VERSION 5.7 ;
  NOWIREEXTENSIONATPIN ON ;
  DIVIDERCHAR "/" ;
  BUSBITCHARS "[]" ;
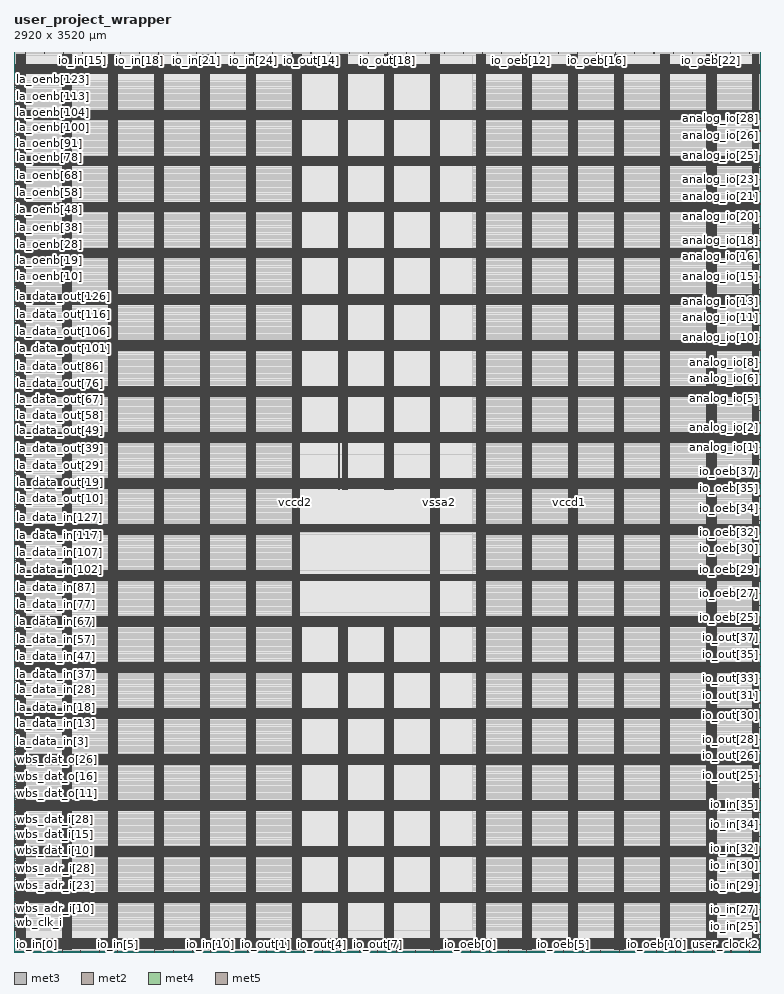
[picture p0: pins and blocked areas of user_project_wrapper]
MACRO user_project_wrapper
  CLASS BLOCK ;
  FOREIGN user_project_wrapper ;
  ORIGIN 0.000 0.000 ;
  SIZE 2920.000 BY 3520.000 ;
  PIN analog_io[0]
    DIRECTION INOUT ;
    USE SIGNAL ;
    PORT
      LAYER met3 ;
        RECT 2916.000 1925.800 2920.000 1926.400 ;
    END
  END analog_io[0]
  PIN analog_io[10]
    DIRECTION INOUT ;
    USE SIGNAL ;
    PORT
      LAYER met3 ;
        RECT 2916.000 2401.800 2920.000 2402.400 ;
    END
  END analog_io[10]
  PIN analog_io[11]
    DIRECTION INOUT ;
    USE SIGNAL ;
    PORT
      LAYER met3 ;
        RECT 2916.000 2449.400 2920.000 2450.000 ;
    END
  END analog_io[11]
  PIN analog_io[12]
    DIRECTION INOUT ;
    USE SIGNAL ;
    PORT
      LAYER met3 ;
        RECT 2916.000 2497.000 2920.000 2497.600 ;
    END
  END analog_io[12]
  PIN analog_io[13]
    DIRECTION INOUT ;
    USE SIGNAL ;
    PORT
      LAYER met3 ;
        RECT 2916.000 2544.600 2920.000 2545.200 ;
    END
  END analog_io[13]
  PIN analog_io[14]
    DIRECTION INOUT ;
    USE SIGNAL ;
    PORT
      LAYER met3 ;
        RECT 2916.000 2592.200 2920.000 2592.800 ;
    END
  END analog_io[14]
  PIN analog_io[15]
    DIRECTION INOUT ;
    USE SIGNAL ;
    PORT
      LAYER met3 ;
        RECT 2916.000 2639.800 2920.000 2640.400 ;
    END
  END analog_io[15]
  PIN analog_io[16]
    DIRECTION INOUT ;
    USE SIGNAL ;
    PORT
      LAYER met3 ;
        RECT 2916.000 2687.400 2920.000 2688.000 ;
    END
  END analog_io[16]
  PIN analog_io[17]
    DIRECTION INOUT ;
    USE SIGNAL ;
    PORT
      LAYER met3 ;
        RECT 2916.000 2735.000 2920.000 2735.600 ;
    END
  END analog_io[17]
  PIN analog_io[18]
    DIRECTION INOUT ;
    USE SIGNAL ;
    PORT
      LAYER met3 ;
        RECT 2916.000 2782.600 2920.000 2783.200 ;
    END
  END analog_io[18]
  PIN analog_io[19]
    DIRECTION INOUT ;
    USE SIGNAL ;
    PORT
      LAYER met3 ;
        RECT 2916.000 2830.200 2920.000 2830.800 ;
    END
  END analog_io[19]
  PIN analog_io[1]
    DIRECTION INOUT ;
    USE SIGNAL ;
    PORT
      LAYER met3 ;
        RECT 2916.000 1973.400 2920.000 1974.000 ;
    END
  END analog_io[1]
  PIN analog_io[20]
    DIRECTION INOUT ;
    USE SIGNAL ;
    PORT
      LAYER met3 ;
        RECT 2916.000 2877.800 2920.000 2878.400 ;
    END
  END analog_io[20]
  PIN analog_io[21]
    DIRECTION INOUT ;
    USE SIGNAL ;
    PORT
      LAYER met3 ;
        RECT 2916.000 2925.400 2920.000 2926.000 ;
    END
  END analog_io[21]
  PIN analog_io[22]
    DIRECTION INOUT ;
    USE SIGNAL ;
    PORT
      LAYER met3 ;
        RECT 2916.000 2973.000 2920.000 2973.600 ;
    END
  END analog_io[22]
  PIN analog_io[23]
    DIRECTION INOUT ;
    USE SIGNAL ;
    PORT
      LAYER met3 ;
        RECT 2916.000 3020.600 2920.000 3021.200 ;
    END
  END analog_io[23]
  PIN analog_io[24]
    DIRECTION INOUT ;
    USE SIGNAL ;
    PORT
      LAYER met3 ;
        RECT 2916.000 3068.200 2920.000 3068.800 ;
    END
  END analog_io[24]
  PIN analog_io[25]
    DIRECTION INOUT ;
    USE SIGNAL ;
    PORT
      LAYER met3 ;
        RECT 2916.000 3115.800 2920.000 3116.400 ;
    END
  END analog_io[25]
  PIN analog_io[26]
    DIRECTION INOUT ;
    USE SIGNAL ;
    PORT
      LAYER met3 ;
        RECT 2916.000 3163.400 2920.000 3164.000 ;
    END
  END analog_io[26]
  PIN analog_io[27]
    DIRECTION INOUT ;
    USE SIGNAL ;
    PORT
      LAYER met3 ;
        RECT 2916.000 3211.000 2920.000 3211.600 ;
    END
  END analog_io[27]
  PIN analog_io[28]
    DIRECTION INOUT ;
    USE SIGNAL ;
    PORT
      LAYER met3 ;
        RECT 2916.000 3258.600 2920.000 3259.200 ;
    END
  END analog_io[28]
  PIN analog_io[2]
    DIRECTION INOUT ;
    USE SIGNAL ;
    PORT
      LAYER met3 ;
        RECT 2916.000 2021.000 2920.000 2021.600 ;
    END
  END analog_io[2]
  PIN analog_io[3]
    DIRECTION INOUT ;
    USE SIGNAL ;
    PORT
      LAYER met3 ;
        RECT 2916.000 2068.600 2920.000 2069.200 ;
    END
  END analog_io[3]
  PIN analog_io[4]
    DIRECTION INOUT ;
    USE SIGNAL ;
    PORT
      LAYER met3 ;
        RECT 2916.000 2116.200 2920.000 2116.800 ;
    END
  END analog_io[4]
  PIN analog_io[5]
    DIRECTION INOUT ;
    USE SIGNAL ;
    PORT
      LAYER met3 ;
        RECT 2916.000 2163.800 2920.000 2164.400 ;
    END
  END analog_io[5]
  PIN analog_io[6]
    DIRECTION INOUT ;
    USE SIGNAL ;
    PORT
      LAYER met3 ;
        RECT 2916.000 2211.400 2920.000 2212.000 ;
    END
  END analog_io[6]
  PIN analog_io[7]
    DIRECTION INOUT ;
    USE SIGNAL ;
    PORT
      LAYER met3 ;
        RECT 2916.000 2259.000 2920.000 2259.600 ;
    END
  END analog_io[7]
  PIN analog_io[8]
    DIRECTION INOUT ;
    USE SIGNAL ;
    PORT
      LAYER met3 ;
        RECT 2916.000 2306.600 2920.000 2307.200 ;
    END
  END analog_io[8]
  PIN analog_io[9]
    DIRECTION INOUT ;
    USE SIGNAL ;
    PORT
      LAYER met3 ;
        RECT 2916.000 2354.200 2920.000 2354.800 ;
    END
  END analog_io[9]
  PIN io_in[0]
    DIRECTION INPUT ;
    USE SIGNAL ;
    PORT
      LAYER met2 ;
        RECT 42.410 0.000 42.690 4.000 ;
    END
  END io_in[0]
  PIN io_in[10]
    DIRECTION INPUT ;
    USE SIGNAL ;
    PORT
      LAYER met2 ;
        RECT 769.210 0.000 769.490 4.000 ;
    END
  END io_in[10]
  PIN io_in[11]
    DIRECTION INPUT ;
    USE SIGNAL ;
    PORT
      LAYER met2 ;
        RECT 841.890 0.000 842.170 4.000 ;
    END
  END io_in[11]
  PIN io_in[12]
    DIRECTION INPUT ;
    USE SIGNAL ;
    PORT
      LAYER met2 ;
        RECT 43.790 3516.000 44.070 3520.000 ;
    END
  END io_in[12]
  PIN io_in[13]
    DIRECTION INPUT ;
    USE SIGNAL ;
    PORT
      LAYER met2 ;
        RECT 118.310 3516.000 118.590 3520.000 ;
    END
  END io_in[13]
  PIN io_in[14]
    DIRECTION INPUT ;
    USE SIGNAL ;
    PORT
      LAYER met2 ;
        RECT 192.830 3516.000 193.110 3520.000 ;
    END
  END io_in[14]
  PIN io_in[15]
    DIRECTION INPUT ;
    USE SIGNAL ;
    PORT
      LAYER met2 ;
        RECT 267.350 3516.000 267.630 3520.000 ;
    END
  END io_in[15]
  PIN io_in[16]
    DIRECTION INPUT ;
    USE SIGNAL ;
    PORT
      LAYER met2 ;
        RECT 341.870 3516.000 342.150 3520.000 ;
    END
  END io_in[16]
  PIN io_in[17]
    DIRECTION INPUT ;
    USE SIGNAL ;
    PORT
      LAYER met2 ;
        RECT 416.390 3516.000 416.670 3520.000 ;
    END
  END io_in[17]
  PIN io_in[18]
    DIRECTION INPUT ;
    USE SIGNAL ;
    PORT
      LAYER met2 ;
        RECT 490.910 3516.000 491.190 3520.000 ;
    END
  END io_in[18]
  PIN io_in[19]
    DIRECTION INPUT ;
    USE SIGNAL ;
    PORT
      LAYER met2 ;
        RECT 565.430 3516.000 565.710 3520.000 ;
    END
  END io_in[19]
  PIN io_in[1]
    DIRECTION INPUT ;
    USE SIGNAL ;
    PORT
      LAYER met2 ;
        RECT 115.090 0.000 115.370 4.000 ;
    END
  END io_in[1]
  PIN io_in[20]
    DIRECTION INPUT ;
    USE SIGNAL ;
    PORT
      LAYER met2 ;
        RECT 639.950 3516.000 640.230 3520.000 ;
    END
  END io_in[20]
  PIN io_in[21]
    DIRECTION INPUT ;
    USE SIGNAL ;
    PORT
      LAYER met2 ;
        RECT 714.470 3516.000 714.750 3520.000 ;
    END
  END io_in[21]
  PIN io_in[22]
    DIRECTION INPUT ;
    USE SIGNAL ;
    PORT
      LAYER met2 ;
        RECT 788.990 3516.000 789.270 3520.000 ;
    END
  END io_in[22]
  PIN io_in[23]
    DIRECTION INPUT ;
    USE SIGNAL ;
    PORT
      LAYER met2 ;
        RECT 863.510 3516.000 863.790 3520.000 ;
    END
  END io_in[23]
  PIN io_in[24]
    DIRECTION INPUT ;
    USE SIGNAL ;
    PORT
      LAYER met2 ;
        RECT 938.030 3516.000 938.310 3520.000 ;
    END
  END io_in[24]
  PIN io_in[25]
    DIRECTION INPUT ;
    USE SIGNAL ;
    PORT
      LAYER met3 ;
        RECT 2916.000 69.400 2920.000 70.000 ;
    END
  END io_in[25]
  PIN io_in[26]
    DIRECTION INPUT ;
    USE SIGNAL ;
    PORT
      LAYER met3 ;
        RECT 2916.000 117.000 2920.000 117.600 ;
    END
  END io_in[26]
  PIN io_in[27]
    DIRECTION INPUT ;
    USE SIGNAL ;
    PORT
      LAYER met3 ;
        RECT 2916.000 164.600 2920.000 165.200 ;
    END
  END io_in[27]
  PIN io_in[28]
    DIRECTION INPUT ;
    USE SIGNAL ;
    PORT
      LAYER met3 ;
        RECT 2916.000 212.200 2920.000 212.800 ;
    END
  END io_in[28]
  PIN io_in[29]
    DIRECTION INPUT ;
    USE SIGNAL ;
    PORT
      LAYER met3 ;
        RECT 2916.000 259.800 2920.000 260.400 ;
    END
  END io_in[29]
  PIN io_in[2]
    DIRECTION INPUT ;
    USE SIGNAL ;
    PORT
      LAYER met2 ;
        RECT 187.770 0.000 188.050 4.000 ;
    END
  END io_in[2]
  PIN io_in[30]
    DIRECTION INPUT ;
    USE SIGNAL ;
    PORT
      LAYER met3 ;
        RECT 2916.000 307.400 2920.000 308.000 ;
    END
  END io_in[30]
  PIN io_in[31]
    DIRECTION INPUT ;
    USE SIGNAL ;
    PORT
      LAYER met3 ;
        RECT 2916.000 355.000 2920.000 355.600 ;
    END
  END io_in[31]
  PIN io_in[32]
    DIRECTION INPUT ;
    USE SIGNAL ;
    PORT
      LAYER met3 ;
        RECT 2916.000 402.600 2920.000 403.200 ;
    END
  END io_in[32]
  PIN io_in[33]
    DIRECTION INPUT ;
    USE SIGNAL ;
    PORT
      LAYER met3 ;
        RECT 2916.000 450.200 2920.000 450.800 ;
    END
  END io_in[33]
  PIN io_in[34]
    DIRECTION INPUT ;
    USE SIGNAL ;
    PORT
      LAYER met3 ;
        RECT 2916.000 497.800 2920.000 498.400 ;
    END
  END io_in[34]
  PIN io_in[35]
    DIRECTION INPUT ;
    USE SIGNAL ;
    PORT
      LAYER met3 ;
        RECT 2916.000 545.400 2920.000 546.000 ;
    END
  END io_in[35]
  PIN io_in[36]
    DIRECTION INPUT ;
    USE SIGNAL ;
    PORT
      LAYER met3 ;
        RECT 2916.000 593.000 2920.000 593.600 ;
    END
  END io_in[36]
  PIN io_in[37]
    DIRECTION INPUT ;
    USE SIGNAL ;
    PORT
      LAYER met3 ;
        RECT 2916.000 640.600 2920.000 641.200 ;
    END
  END io_in[37]
  PIN io_in[3]
    DIRECTION INPUT ;
    USE SIGNAL ;
    PORT
      LAYER met2 ;
        RECT 260.450 0.000 260.730 4.000 ;
    END
  END io_in[3]
  PIN io_in[4]
    DIRECTION INPUT ;
    USE SIGNAL ;
    PORT
      LAYER met2 ;
        RECT 333.130 0.000 333.410 4.000 ;
    END
  END io_in[4]
  PIN io_in[5]
    DIRECTION INPUT ;
    USE SIGNAL ;
    PORT
      LAYER met2 ;
        RECT 405.810 0.000 406.090 4.000 ;
    END
  END io_in[5]
  PIN io_in[6]
    DIRECTION INPUT ;
    USE SIGNAL ;
    PORT
      LAYER met2 ;
        RECT 478.490 0.000 478.770 4.000 ;
    END
  END io_in[6]
  PIN io_in[7]
    DIRECTION INPUT ;
    USE SIGNAL ;
    PORT
      LAYER met2 ;
        RECT 551.170 0.000 551.450 4.000 ;
    END
  END io_in[7]
  PIN io_in[8]
    DIRECTION INPUT ;
    USE SIGNAL ;
    PORT
      LAYER met2 ;
        RECT 623.850 0.000 624.130 4.000 ;
    END
  END io_in[8]
  PIN io_in[9]
    DIRECTION INPUT ;
    USE SIGNAL ;
    PORT
      LAYER met2 ;
        RECT 696.530 0.000 696.810 4.000 ;
    END
  END io_in[9]
  PIN io_oeb[0]
    DIRECTION OUTPUT ;
    USE SIGNAL ;
    ANTENNADIFFAREA 0.891000 ;
    PORT
      LAYER met2 ;
        RECT 1786.730 0.000 1787.010 4.000 ;
    END
  END io_oeb[0]
  PIN io_oeb[10]
    DIRECTION OUTPUT ;
    USE SIGNAL ;
    ANTENNADIFFAREA 0.891000 ;
    PORT
      LAYER met2 ;
        RECT 2513.530 0.000 2513.810 4.000 ;
    END
  END io_oeb[10]
  PIN io_oeb[11]
    DIRECTION OUTPUT ;
    USE SIGNAL ;
    ANTENNADIFFAREA 0.891000 ;
    PORT
      LAYER met2 ;
        RECT 2586.210 0.000 2586.490 4.000 ;
    END
  END io_oeb[11]
  PIN io_oeb[12]
    DIRECTION OUTPUT ;
    USE SIGNAL ;
    ANTENNADIFFAREA 0.891000 ;
    PORT
      LAYER met2 ;
        RECT 1981.310 3516.000 1981.590 3520.000 ;
    END
  END io_oeb[12]
  PIN io_oeb[13]
    DIRECTION OUTPUT ;
    USE SIGNAL ;
    ANTENNADIFFAREA 0.891000 ;
    PORT
      LAYER met2 ;
        RECT 2055.830 3516.000 2056.110 3520.000 ;
    END
  END io_oeb[13]
  PIN io_oeb[14]
    DIRECTION OUTPUT ;
    USE SIGNAL ;
    ANTENNADIFFAREA 0.891000 ;
    PORT
      LAYER met2 ;
        RECT 2130.350 3516.000 2130.630 3520.000 ;
    END
  END io_oeb[14]
  PIN io_oeb[15]
    DIRECTION OUTPUT ;
    USE SIGNAL ;
    ANTENNADIFFAREA 0.891000 ;
    PORT
      LAYER met2 ;
        RECT 2204.870 3516.000 2205.150 3520.000 ;
    END
  END io_oeb[15]
  PIN io_oeb[16]
    DIRECTION OUTPUT ;
    USE SIGNAL ;
    ANTENNADIFFAREA 0.891000 ;
    PORT
      LAYER met2 ;
        RECT 2279.390 3516.000 2279.670 3520.000 ;
    END
  END io_oeb[16]
  PIN io_oeb[17]
    DIRECTION OUTPUT ;
    USE SIGNAL ;
    ANTENNADIFFAREA 0.891000 ;
    PORT
      LAYER met2 ;
        RECT 2353.910 3516.000 2354.190 3520.000 ;
    END
  END io_oeb[17]
  PIN io_oeb[18]
    DIRECTION OUTPUT ;
    USE SIGNAL ;
    ANTENNADIFFAREA 0.891000 ;
    PORT
      LAYER met2 ;
        RECT 2428.430 3516.000 2428.710 3520.000 ;
    END
  END io_oeb[18]
  PIN io_oeb[19]
    DIRECTION OUTPUT ;
    USE SIGNAL ;
    ANTENNADIFFAREA 0.891000 ;
    PORT
      LAYER met2 ;
        RECT 2502.950 3516.000 2503.230 3520.000 ;
    END
  END io_oeb[19]
  PIN io_oeb[1]
    DIRECTION OUTPUT ;
    USE SIGNAL ;
    ANTENNADIFFAREA 0.891000 ;
    PORT
      LAYER met2 ;
        RECT 1859.410 0.000 1859.690 4.000 ;
    END
  END io_oeb[1]
  PIN io_oeb[20]
    DIRECTION OUTPUT ;
    USE SIGNAL ;
    ANTENNADIFFAREA 0.891000 ;
    PORT
      LAYER met2 ;
        RECT 2577.470 3516.000 2577.750 3520.000 ;
    END
  END io_oeb[20]
  PIN io_oeb[21]
    DIRECTION OUTPUT ;
    USE SIGNAL ;
    ANTENNADIFFAREA 0.891000 ;
    PORT
      LAYER met2 ;
        RECT 2651.990 3516.000 2652.270 3520.000 ;
    END
  END io_oeb[21]
  PIN io_oeb[22]
    DIRECTION OUTPUT ;
    USE SIGNAL ;
    ANTENNADIFFAREA 0.891000 ;
    PORT
      LAYER met2 ;
        RECT 2726.510 3516.000 2726.790 3520.000 ;
    END
  END io_oeb[22]
  PIN io_oeb[23]
    DIRECTION OUTPUT ;
    USE SIGNAL ;
    ANTENNADIFFAREA 0.891000 ;
    PORT
      LAYER met2 ;
        RECT 2801.030 3516.000 2801.310 3520.000 ;
    END
  END io_oeb[23]
  PIN io_oeb[24]
    DIRECTION OUTPUT ;
    USE SIGNAL ;
    ANTENNADIFFAREA 0.891000 ;
    PORT
      LAYER met2 ;
        RECT 2875.550 3516.000 2875.830 3520.000 ;
    END
  END io_oeb[24]
  PIN io_oeb[25]
    DIRECTION OUTPUT ;
    USE SIGNAL ;
    ANTENNADIFFAREA 0.891000 ;
    PORT
      LAYER met3 ;
        RECT 2916.000 1307.000 2920.000 1307.600 ;
    END
  END io_oeb[25]
  PIN io_oeb[26]
    DIRECTION OUTPUT ;
    USE SIGNAL ;
    ANTENNADIFFAREA 0.891000 ;
    PORT
      LAYER met3 ;
        RECT 2916.000 1354.600 2920.000 1355.200 ;
    END
  END io_oeb[26]
  PIN io_oeb[27]
    DIRECTION OUTPUT ;
    USE SIGNAL ;
    ANTENNADIFFAREA 0.891000 ;
    PORT
      LAYER met3 ;
        RECT 2916.000 1402.200 2920.000 1402.800 ;
    END
  END io_oeb[27]
  PIN io_oeb[28]
    DIRECTION OUTPUT ;
    USE SIGNAL ;
    ANTENNADIFFAREA 0.891000 ;
    PORT
      LAYER met3 ;
        RECT 2916.000 1449.800 2920.000 1450.400 ;
    END
  END io_oeb[28]
  PIN io_oeb[29]
    DIRECTION OUTPUT ;
    USE SIGNAL ;
    ANTENNADIFFAREA 0.891000 ;
    PORT
      LAYER met3 ;
        RECT 2916.000 1497.400 2920.000 1498.000 ;
    END
  END io_oeb[29]
  PIN io_oeb[2]
    DIRECTION OUTPUT ;
    USE SIGNAL ;
    ANTENNADIFFAREA 0.891000 ;
    PORT
      LAYER met2 ;
        RECT 1932.090 0.000 1932.370 4.000 ;
    END
  END io_oeb[2]
  PIN io_oeb[30]
    DIRECTION OUTPUT ;
    USE SIGNAL ;
    ANTENNADIFFAREA 0.891000 ;
    PORT
      LAYER met3 ;
        RECT 2916.000 1545.000 2920.000 1545.600 ;
    END
  END io_oeb[30]
  PIN io_oeb[31]
    DIRECTION OUTPUT ;
    USE SIGNAL ;
    ANTENNADIFFAREA 0.891000 ;
    PORT
      LAYER met3 ;
        RECT 2916.000 1592.600 2920.000 1593.200 ;
    END
  END io_oeb[31]
  PIN io_oeb[32]
    DIRECTION OUTPUT ;
    USE SIGNAL ;
    ANTENNADIFFAREA 0.891000 ;
    PORT
      LAYER met3 ;
        RECT 2916.000 1640.200 2920.000 1640.800 ;
    END
  END io_oeb[32]
  PIN io_oeb[33]
    DIRECTION OUTPUT ;
    USE SIGNAL ;
    ANTENNADIFFAREA 0.891000 ;
    PORT
      LAYER met3 ;
        RECT 2916.000 1687.800 2920.000 1688.400 ;
    END
  END io_oeb[33]
  PIN io_oeb[34]
    DIRECTION OUTPUT ;
    USE SIGNAL ;
    ANTENNADIFFAREA 0.891000 ;
    PORT
      LAYER met3 ;
        RECT 2916.000 1735.400 2920.000 1736.000 ;
    END
  END io_oeb[34]
  PIN io_oeb[35]
    DIRECTION OUTPUT ;
    USE SIGNAL ;
    ANTENNADIFFAREA 0.891000 ;
    PORT
      LAYER met3 ;
        RECT 2916.000 1783.000 2920.000 1783.600 ;
    END
  END io_oeb[35]
  PIN io_oeb[36]
    DIRECTION OUTPUT ;
    USE SIGNAL ;
    ANTENNADIFFAREA 0.891000 ;
    PORT
      LAYER met3 ;
        RECT 2916.000 1830.600 2920.000 1831.200 ;
    END
  END io_oeb[36]
  PIN io_oeb[37]
    DIRECTION OUTPUT ;
    USE SIGNAL ;
    ANTENNADIFFAREA 0.891000 ;
    PORT
      LAYER met3 ;
        RECT 2916.000 1878.200 2920.000 1878.800 ;
    END
  END io_oeb[37]
  PIN io_oeb[3]
    DIRECTION OUTPUT ;
    USE SIGNAL ;
    ANTENNADIFFAREA 0.891000 ;
    PORT
      LAYER met2 ;
        RECT 2004.770 0.000 2005.050 4.000 ;
    END
  END io_oeb[3]
  PIN io_oeb[4]
    DIRECTION OUTPUT ;
    USE SIGNAL ;
    ANTENNADIFFAREA 0.891000 ;
    PORT
      LAYER met2 ;
        RECT 2077.450 0.000 2077.730 4.000 ;
    END
  END io_oeb[4]
  PIN io_oeb[5]
    DIRECTION OUTPUT ;
    USE SIGNAL ;
    ANTENNADIFFAREA 0.891000 ;
    PORT
      LAYER met2 ;
        RECT 2150.130 0.000 2150.410 4.000 ;
    END
  END io_oeb[5]
  PIN io_oeb[6]
    DIRECTION OUTPUT ;
    USE SIGNAL ;
    ANTENNADIFFAREA 0.891000 ;
    PORT
      LAYER met2 ;
        RECT 2222.810 0.000 2223.090 4.000 ;
    END
  END io_oeb[6]
  PIN io_oeb[7]
    DIRECTION OUTPUT ;
    USE SIGNAL ;
    ANTENNADIFFAREA 0.891000 ;
    PORT
      LAYER met2 ;
        RECT 2295.490 0.000 2295.770 4.000 ;
    END
  END io_oeb[7]
  PIN io_oeb[8]
    DIRECTION OUTPUT ;
    USE SIGNAL ;
    ANTENNADIFFAREA 0.891000 ;
    PORT
      LAYER met2 ;
        RECT 2368.170 0.000 2368.450 4.000 ;
    END
  END io_oeb[8]
  PIN io_oeb[9]
    DIRECTION OUTPUT ;
    USE SIGNAL ;
    ANTENNADIFFAREA 0.891000 ;
    PORT
      LAYER met2 ;
        RECT 2440.850 0.000 2441.130 4.000 ;
    END
  END io_oeb[9]
  PIN io_out[0]
    DIRECTION OUTPUT ;
    USE SIGNAL ;
    PORT
      LAYER met2 ;
        RECT 914.570 0.000 914.850 4.000 ;
    END
  END io_out[0]
  PIN io_out[10]
    DIRECTION OUTPUT ;
    USE SIGNAL ;
    ANTENNADIFFAREA 0.891000 ;
    PORT
      LAYER met2 ;
        RECT 1641.370 0.000 1641.650 4.000 ;
    END
  END io_out[10]
  PIN io_out[11]
    DIRECTION OUTPUT ;
    USE SIGNAL ;
    PORT
      LAYER met2 ;
        RECT 1714.050 0.000 1714.330 4.000 ;
    END
  END io_out[11]
  PIN io_out[12]
    DIRECTION OUTPUT ;
    USE SIGNAL ;
    ANTENNADIFFAREA 0.891000 ;
    PORT
      LAYER met2 ;
        RECT 1012.550 3516.000 1012.830 3520.000 ;
    END
  END io_out[12]
  PIN io_out[13]
    DIRECTION OUTPUT ;
    USE SIGNAL ;
    ANTENNADIFFAREA 0.891000 ;
    PORT
      LAYER met2 ;
        RECT 1087.070 3516.000 1087.350 3520.000 ;
    END
  END io_out[13]
  PIN io_out[14]
    DIRECTION OUTPUT ;
    USE SIGNAL ;
    ANTENNADIFFAREA 0.891000 ;
    PORT
      LAYER met2 ;
        RECT 1161.590 3516.000 1161.870 3520.000 ;
    END
  END io_out[14]
  PIN io_out[15]
    DIRECTION OUTPUT ;
    USE SIGNAL ;
    ANTENNADIFFAREA 0.891000 ;
    PORT
      LAYER met2 ;
        RECT 1236.110 3516.000 1236.390 3520.000 ;
    END
  END io_out[15]
  PIN io_out[16]
    DIRECTION OUTPUT ;
    USE SIGNAL ;
    ANTENNADIFFAREA 0.891000 ;
    PORT
      LAYER met2 ;
        RECT 1310.630 3516.000 1310.910 3520.000 ;
    END
  END io_out[16]
  PIN io_out[17]
    DIRECTION OUTPUT ;
    USE SIGNAL ;
    ANTENNADIFFAREA 0.891000 ;
    PORT
      LAYER met2 ;
        RECT 1385.150 3516.000 1385.430 3520.000 ;
    END
  END io_out[17]
  PIN io_out[18]
    DIRECTION OUTPUT ;
    USE SIGNAL ;
    ANTENNADIFFAREA 0.891000 ;
    PORT
      LAYER met2 ;
        RECT 1459.670 3516.000 1459.950 3520.000 ;
    END
  END io_out[18]
  PIN io_out[19]
    DIRECTION OUTPUT ;
    USE SIGNAL ;
    ANTENNADIFFAREA 0.891000 ;
    PORT
      LAYER met2 ;
        RECT 1534.190 3516.000 1534.470 3520.000 ;
    END
  END io_out[19]
  PIN io_out[1]
    DIRECTION OUTPUT ;
    USE SIGNAL ;
    PORT
      LAYER met2 ;
        RECT 987.250 0.000 987.530 4.000 ;
    END
  END io_out[1]
  PIN io_out[20]
    DIRECTION OUTPUT ;
    USE SIGNAL ;
    ANTENNADIFFAREA 0.891000 ;
    PORT
      LAYER met2 ;
        RECT 1608.710 3516.000 1608.990 3520.000 ;
    END
  END io_out[20]
  PIN io_out[21]
    DIRECTION OUTPUT ;
    USE SIGNAL ;
    PORT
      LAYER met2 ;
        RECT 1683.230 3516.000 1683.510 3520.000 ;
    END
  END io_out[21]
  PIN io_out[22]
    DIRECTION OUTPUT ;
    USE SIGNAL ;
    ANTENNADIFFAREA 0.891000 ;
    PORT
      LAYER met2 ;
        RECT 1757.750 3516.000 1758.030 3520.000 ;
    END
  END io_out[22]
  PIN io_out[23]
    DIRECTION OUTPUT ;
    USE SIGNAL ;
    ANTENNADIFFAREA 0.891000 ;
    PORT
      LAYER met2 ;
        RECT 1832.270 3516.000 1832.550 3520.000 ;
    END
  END io_out[23]
  PIN io_out[24]
    DIRECTION OUTPUT ;
    USE SIGNAL ;
    ANTENNADIFFAREA 0.891000 ;
    PORT
      LAYER met2 ;
        RECT 1906.790 3516.000 1907.070 3520.000 ;
    END
  END io_out[24]
  PIN io_out[25]
    DIRECTION OUTPUT ;
    USE SIGNAL ;
    PORT
      LAYER met3 ;
        RECT 2916.000 688.200 2920.000 688.800 ;
    END
  END io_out[25]
  PIN io_out[26]
    DIRECTION OUTPUT ;
    USE SIGNAL ;
    PORT
      LAYER met3 ;
        RECT 2916.000 735.800 2920.000 736.400 ;
    END
  END io_out[26]
  PIN io_out[27]
    DIRECTION OUTPUT ;
    USE SIGNAL ;
    PORT
      LAYER met3 ;
        RECT 2916.000 783.400 2920.000 784.000 ;
    END
  END io_out[27]
  PIN io_out[28]
    DIRECTION OUTPUT ;
    USE SIGNAL ;
    PORT
      LAYER met3 ;
        RECT 2916.000 831.000 2920.000 831.600 ;
    END
  END io_out[28]
  PIN io_out[29]
    DIRECTION OUTPUT ;
    USE SIGNAL ;
    PORT
      LAYER met3 ;
        RECT 2916.000 878.600 2920.000 879.200 ;
    END
  END io_out[29]
  PIN io_out[2]
    DIRECTION OUTPUT ;
    USE SIGNAL ;
    PORT
      LAYER met2 ;
        RECT 1059.930 0.000 1060.210 4.000 ;
    END
  END io_out[2]
  PIN io_out[30]
    DIRECTION OUTPUT ;
    USE SIGNAL ;
    PORT
      LAYER met3 ;
        RECT 2916.000 926.200 2920.000 926.800 ;
    END
  END io_out[30]
  PIN io_out[31]
    DIRECTION OUTPUT ;
    USE SIGNAL ;
    PORT
      LAYER met3 ;
        RECT 2916.000 973.800 2920.000 974.400 ;
    END
  END io_out[31]
  PIN io_out[32]
    DIRECTION OUTPUT ;
    USE SIGNAL ;
    PORT
      LAYER met3 ;
        RECT 2916.000 1021.400 2920.000 1022.000 ;
    END
  END io_out[32]
  PIN io_out[33]
    DIRECTION OUTPUT ;
    USE SIGNAL ;
    PORT
      LAYER met3 ;
        RECT 2916.000 1069.000 2920.000 1069.600 ;
    END
  END io_out[33]
  PIN io_out[34]
    DIRECTION OUTPUT ;
    USE SIGNAL ;
    PORT
      LAYER met3 ;
        RECT 2916.000 1116.600 2920.000 1117.200 ;
    END
  END io_out[34]
  PIN io_out[35]
    DIRECTION OUTPUT ;
    USE SIGNAL ;
    PORT
      LAYER met3 ;
        RECT 2916.000 1164.200 2920.000 1164.800 ;
    END
  END io_out[35]
  PIN io_out[36]
    DIRECTION OUTPUT ;
    USE SIGNAL ;
    PORT
      LAYER met3 ;
        RECT 2916.000 1211.800 2920.000 1212.400 ;
    END
  END io_out[36]
  PIN io_out[37]
    DIRECTION OUTPUT ;
    USE SIGNAL ;
    PORT
      LAYER met3 ;
        RECT 2916.000 1259.400 2920.000 1260.000 ;
    END
  END io_out[37]
  PIN io_out[3]
    DIRECTION OUTPUT ;
    USE SIGNAL ;
    PORT
      LAYER met2 ;
        RECT 1132.610 0.000 1132.890 4.000 ;
    END
  END io_out[3]
  PIN io_out[4]
    DIRECTION OUTPUT ;
    USE SIGNAL ;
    PORT
      LAYER met2 ;
        RECT 1205.290 0.000 1205.570 4.000 ;
    END
  END io_out[4]
  PIN io_out[5]
    DIRECTION OUTPUT ;
    USE SIGNAL ;
    PORT
      LAYER met2 ;
        RECT 1277.970 0.000 1278.250 4.000 ;
    END
  END io_out[5]
  PIN io_out[6]
    DIRECTION OUTPUT ;
    USE SIGNAL ;
    PORT
      LAYER met2 ;
        RECT 1350.650 0.000 1350.930 4.000 ;
    END
  END io_out[6]
  PIN io_out[7]
    DIRECTION OUTPUT ;
    USE SIGNAL ;
    PORT
      LAYER met2 ;
        RECT 1423.330 0.000 1423.610 4.000 ;
    END
  END io_out[7]
  PIN io_out[8]
    DIRECTION OUTPUT ;
    USE SIGNAL ;
    PORT
      LAYER met2 ;
        RECT 1496.010 0.000 1496.290 4.000 ;
    END
  END io_out[8]
  PIN io_out[9]
    DIRECTION OUTPUT ;
    USE SIGNAL ;
    PORT
      LAYER met2 ;
        RECT 1568.690 0.000 1568.970 4.000 ;
    END
  END io_out[9]
  PIN la_data_in[0]
    DIRECTION INPUT ;
    USE SIGNAL ;
    PORT
      LAYER met3 ;
        RECT 0.000 803.800 4.000 804.400 ;
    END
  END la_data_in[0]
  PIN la_data_in[100]
    DIRECTION INPUT ;
    USE SIGNAL ;
    PORT
      LAYER met3 ;
        RECT 0.000 1483.800 4.000 1484.400 ;
    END
  END la_data_in[100]
  PIN la_data_in[101]
    DIRECTION INPUT ;
    USE SIGNAL ;
    PORT
      LAYER met3 ;
        RECT 0.000 1490.600 4.000 1491.200 ;
    END
  END la_data_in[101]
  PIN la_data_in[102]
    DIRECTION INPUT ;
    USE SIGNAL ;
    PORT
      LAYER met3 ;
        RECT 0.000 1497.400 4.000 1498.000 ;
    END
  END la_data_in[102]
  PIN la_data_in[103]
    DIRECTION INPUT ;
    USE SIGNAL ;
    PORT
      LAYER met3 ;
        RECT 0.000 1504.200 4.000 1504.800 ;
    END
  END la_data_in[103]
  PIN la_data_in[104]
    DIRECTION INPUT ;
    USE SIGNAL ;
    PORT
      LAYER met3 ;
        RECT 0.000 1511.000 4.000 1511.600 ;
    END
  END la_data_in[104]
  PIN la_data_in[105]
    DIRECTION INPUT ;
    USE SIGNAL ;
    PORT
      LAYER met3 ;
        RECT 0.000 1517.800 4.000 1518.400 ;
    END
  END la_data_in[105]
  PIN la_data_in[106]
    DIRECTION INPUT ;
    USE SIGNAL ;
    PORT
      LAYER met3 ;
        RECT 0.000 1524.600 4.000 1525.200 ;
    END
  END la_data_in[106]
  PIN la_data_in[107]
    DIRECTION INPUT ;
    USE SIGNAL ;
    PORT
      LAYER met3 ;
        RECT 0.000 1531.400 4.000 1532.000 ;
    END
  END la_data_in[107]
  PIN la_data_in[108]
    DIRECTION INPUT ;
    USE SIGNAL ;
    PORT
      LAYER met3 ;
        RECT 0.000 1538.200 4.000 1538.800 ;
    END
  END la_data_in[108]
  PIN la_data_in[109]
    DIRECTION INPUT ;
    USE SIGNAL ;
    PORT
      LAYER met3 ;
        RECT 0.000 1545.000 4.000 1545.600 ;
    END
  END la_data_in[109]
  PIN la_data_in[10]
    DIRECTION INPUT ;
    USE SIGNAL ;
    PORT
      LAYER met3 ;
        RECT 0.000 871.800 4.000 872.400 ;
    END
  END la_data_in[10]
  PIN la_data_in[110]
    DIRECTION INPUT ;
    USE SIGNAL ;
    PORT
      LAYER met3 ;
        RECT 0.000 1551.800 4.000 1552.400 ;
    END
  END la_data_in[110]
  PIN la_data_in[111]
    DIRECTION INPUT ;
    USE SIGNAL ;
    PORT
      LAYER met3 ;
        RECT 0.000 1558.600 4.000 1559.200 ;
    END
  END la_data_in[111]
  PIN la_data_in[112]
    DIRECTION INPUT ;
    USE SIGNAL ;
    PORT
      LAYER met3 ;
        RECT 0.000 1565.400 4.000 1566.000 ;
    END
  END la_data_in[112]
  PIN la_data_in[113]
    DIRECTION INPUT ;
    USE SIGNAL ;
    PORT
      LAYER met3 ;
        RECT 0.000 1572.200 4.000 1572.800 ;
    END
  END la_data_in[113]
  PIN la_data_in[114]
    DIRECTION INPUT ;
    USE SIGNAL ;
    PORT
      LAYER met3 ;
        RECT 0.000 1579.000 4.000 1579.600 ;
    END
  END la_data_in[114]
  PIN la_data_in[115]
    DIRECTION INPUT ;
    USE SIGNAL ;
    PORT
      LAYER met3 ;
        RECT 0.000 1585.800 4.000 1586.400 ;
    END
  END la_data_in[115]
  PIN la_data_in[116]
    DIRECTION INPUT ;
    USE SIGNAL ;
    PORT
      LAYER met3 ;
        RECT 0.000 1592.600 4.000 1593.200 ;
    END
  END la_data_in[116]
  PIN la_data_in[117]
    DIRECTION INPUT ;
    USE SIGNAL ;
    PORT
      LAYER met3 ;
        RECT 0.000 1599.400 4.000 1600.000 ;
    END
  END la_data_in[117]
  PIN la_data_in[118]
    DIRECTION INPUT ;
    USE SIGNAL ;
    PORT
      LAYER met3 ;
        RECT 0.000 1606.200 4.000 1606.800 ;
    END
  END la_data_in[118]
  PIN la_data_in[119]
    DIRECTION INPUT ;
    USE SIGNAL ;
    PORT
      LAYER met3 ;
        RECT 0.000 1613.000 4.000 1613.600 ;
    END
  END la_data_in[119]
  PIN la_data_in[11]
    DIRECTION INPUT ;
    USE SIGNAL ;
    PORT
      LAYER met3 ;
        RECT 0.000 878.600 4.000 879.200 ;
    END
  END la_data_in[11]
  PIN la_data_in[120]
    DIRECTION INPUT ;
    USE SIGNAL ;
    PORT
      LAYER met3 ;
        RECT 0.000 1619.800 4.000 1620.400 ;
    END
  END la_data_in[120]
  PIN la_data_in[121]
    DIRECTION INPUT ;
    USE SIGNAL ;
    PORT
      LAYER met3 ;
        RECT 0.000 1626.600 4.000 1627.200 ;
    END
  END la_data_in[121]
  PIN la_data_in[122]
    DIRECTION INPUT ;
    USE SIGNAL ;
    PORT
      LAYER met3 ;
        RECT 0.000 1633.400 4.000 1634.000 ;
    END
  END la_data_in[122]
  PIN la_data_in[123]
    DIRECTION INPUT ;
    USE SIGNAL ;
    PORT
      LAYER met3 ;
        RECT 0.000 1640.200 4.000 1640.800 ;
    END
  END la_data_in[123]
  PIN la_data_in[124]
    DIRECTION INPUT ;
    USE SIGNAL ;
    PORT
      LAYER met3 ;
        RECT 0.000 1647.000 4.000 1647.600 ;
    END
  END la_data_in[124]
  PIN la_data_in[125]
    DIRECTION INPUT ;
    USE SIGNAL ;
    PORT
      LAYER met3 ;
        RECT 0.000 1653.800 4.000 1654.400 ;
    END
  END la_data_in[125]
  PIN la_data_in[126]
    DIRECTION INPUT ;
    USE SIGNAL ;
    PORT
      LAYER met3 ;
        RECT 0.000 1660.600 4.000 1661.200 ;
    END
  END la_data_in[126]
  PIN la_data_in[127]
    DIRECTION INPUT ;
    USE SIGNAL ;
    PORT
      LAYER met3 ;
        RECT 0.000 1667.400 4.000 1668.000 ;
    END
  END la_data_in[127]
  PIN la_data_in[12]
    DIRECTION INPUT ;
    USE SIGNAL ;
    PORT
      LAYER met3 ;
        RECT 0.000 885.400 4.000 886.000 ;
    END
  END la_data_in[12]
  PIN la_data_in[13]
    DIRECTION INPUT ;
    USE SIGNAL ;
    PORT
      LAYER met3 ;
        RECT 0.000 892.200 4.000 892.800 ;
    END
  END la_data_in[13]
  PIN la_data_in[14]
    DIRECTION INPUT ;
    USE SIGNAL ;
    PORT
      LAYER met3 ;
        RECT 0.000 899.000 4.000 899.600 ;
    END
  END la_data_in[14]
  PIN la_data_in[15]
    DIRECTION INPUT ;
    USE SIGNAL ;
    PORT
      LAYER met3 ;
        RECT 0.000 905.800 4.000 906.400 ;
    END
  END la_data_in[15]
  PIN la_data_in[16]
    DIRECTION INPUT ;
    USE SIGNAL ;
    PORT
      LAYER met3 ;
        RECT 0.000 912.600 4.000 913.200 ;
    END
  END la_data_in[16]
  PIN la_data_in[17]
    DIRECTION INPUT ;
    USE SIGNAL ;
    PORT
      LAYER met3 ;
        RECT 0.000 919.400 4.000 920.000 ;
    END
  END la_data_in[17]
  PIN la_data_in[18]
    DIRECTION INPUT ;
    USE SIGNAL ;
    PORT
      LAYER met3 ;
        RECT 0.000 926.200 4.000 926.800 ;
    END
  END la_data_in[18]
  PIN la_data_in[19]
    DIRECTION INPUT ;
    USE SIGNAL ;
    PORT
      LAYER met3 ;
        RECT 0.000 933.000 4.000 933.600 ;
    END
  END la_data_in[19]
  PIN la_data_in[1]
    DIRECTION INPUT ;
    USE SIGNAL ;
    PORT
      LAYER met3 ;
        RECT 0.000 810.600 4.000 811.200 ;
    END
  END la_data_in[1]
  PIN la_data_in[20]
    DIRECTION INPUT ;
    USE SIGNAL ;
    PORT
      LAYER met3 ;
        RECT 0.000 939.800 4.000 940.400 ;
    END
  END la_data_in[20]
  PIN la_data_in[21]
    DIRECTION INPUT ;
    USE SIGNAL ;
    PORT
      LAYER met3 ;
        RECT 0.000 946.600 4.000 947.200 ;
    END
  END la_data_in[21]
  PIN la_data_in[22]
    DIRECTION INPUT ;
    USE SIGNAL ;
    PORT
      LAYER met3 ;
        RECT 0.000 953.400 4.000 954.000 ;
    END
  END la_data_in[22]
  PIN la_data_in[23]
    DIRECTION INPUT ;
    USE SIGNAL ;
    PORT
      LAYER met3 ;
        RECT 0.000 960.200 4.000 960.800 ;
    END
  END la_data_in[23]
  PIN la_data_in[24]
    DIRECTION INPUT ;
    USE SIGNAL ;
    PORT
      LAYER met3 ;
        RECT 0.000 967.000 4.000 967.600 ;
    END
  END la_data_in[24]
  PIN la_data_in[25]
    DIRECTION INPUT ;
    USE SIGNAL ;
    PORT
      LAYER met3 ;
        RECT 0.000 973.800 4.000 974.400 ;
    END
  END la_data_in[25]
  PIN la_data_in[26]
    DIRECTION INPUT ;
    USE SIGNAL ;
    PORT
      LAYER met3 ;
        RECT 0.000 980.600 4.000 981.200 ;
    END
  END la_data_in[26]
  PIN la_data_in[27]
    DIRECTION INPUT ;
    USE SIGNAL ;
    PORT
      LAYER met3 ;
        RECT 0.000 987.400 4.000 988.000 ;
    END
  END la_data_in[27]
  PIN la_data_in[28]
    DIRECTION INPUT ;
    USE SIGNAL ;
    PORT
      LAYER met3 ;
        RECT 0.000 994.200 4.000 994.800 ;
    END
  END la_data_in[28]
  PIN la_data_in[29]
    DIRECTION INPUT ;
    USE SIGNAL ;
    PORT
      LAYER met3 ;
        RECT 0.000 1001.000 4.000 1001.600 ;
    END
  END la_data_in[29]
  PIN la_data_in[2]
    DIRECTION INPUT ;
    USE SIGNAL ;
    PORT
      LAYER met3 ;
        RECT 0.000 817.400 4.000 818.000 ;
    END
  END la_data_in[2]
  PIN la_data_in[30]
    DIRECTION INPUT ;
    USE SIGNAL ;
    PORT
      LAYER met3 ;
        RECT 0.000 1007.800 4.000 1008.400 ;
    END
  END la_data_in[30]
  PIN la_data_in[31]
    DIRECTION INPUT ;
    USE SIGNAL ;
    PORT
      LAYER met3 ;
        RECT 0.000 1014.600 4.000 1015.200 ;
    END
  END la_data_in[31]
  PIN la_data_in[32]
    DIRECTION INPUT ;
    USE SIGNAL ;
    PORT
      LAYER met3 ;
        RECT 0.000 1021.400 4.000 1022.000 ;
    END
  END la_data_in[32]
  PIN la_data_in[33]
    DIRECTION INPUT ;
    USE SIGNAL ;
    PORT
      LAYER met3 ;
        RECT 0.000 1028.200 4.000 1028.800 ;
    END
  END la_data_in[33]
  PIN la_data_in[34]
    DIRECTION INPUT ;
    USE SIGNAL ;
    PORT
      LAYER met3 ;
        RECT 0.000 1035.000 4.000 1035.600 ;
    END
  END la_data_in[34]
  PIN la_data_in[35]
    DIRECTION INPUT ;
    USE SIGNAL ;
    PORT
      LAYER met3 ;
        RECT 0.000 1041.800 4.000 1042.400 ;
    END
  END la_data_in[35]
  PIN la_data_in[36]
    DIRECTION INPUT ;
    USE SIGNAL ;
    PORT
      LAYER met3 ;
        RECT 0.000 1048.600 4.000 1049.200 ;
    END
  END la_data_in[36]
  PIN la_data_in[37]
    DIRECTION INPUT ;
    USE SIGNAL ;
    PORT
      LAYER met3 ;
        RECT 0.000 1055.400 4.000 1056.000 ;
    END
  END la_data_in[37]
  PIN la_data_in[38]
    DIRECTION INPUT ;
    USE SIGNAL ;
    PORT
      LAYER met3 ;
        RECT 0.000 1062.200 4.000 1062.800 ;
    END
  END la_data_in[38]
  PIN la_data_in[39]
    DIRECTION INPUT ;
    USE SIGNAL ;
    PORT
      LAYER met3 ;
        RECT 0.000 1069.000 4.000 1069.600 ;
    END
  END la_data_in[39]
  PIN la_data_in[3]
    DIRECTION INPUT ;
    USE SIGNAL ;
    PORT
      LAYER met3 ;
        RECT 0.000 824.200 4.000 824.800 ;
    END
  END la_data_in[3]
  PIN la_data_in[40]
    DIRECTION INPUT ;
    USE SIGNAL ;
    PORT
      LAYER met3 ;
        RECT 0.000 1075.800 4.000 1076.400 ;
    END
  END la_data_in[40]
  PIN la_data_in[41]
    DIRECTION INPUT ;
    USE SIGNAL ;
    PORT
      LAYER met3 ;
        RECT 0.000 1082.600 4.000 1083.200 ;
    END
  END la_data_in[41]
  PIN la_data_in[42]
    DIRECTION INPUT ;
    USE SIGNAL ;
    PORT
      LAYER met3 ;
        RECT 0.000 1089.400 4.000 1090.000 ;
    END
  END la_data_in[42]
  PIN la_data_in[43]
    DIRECTION INPUT ;
    USE SIGNAL ;
    PORT
      LAYER met3 ;
        RECT 0.000 1096.200 4.000 1096.800 ;
    END
  END la_data_in[43]
  PIN la_data_in[44]
    DIRECTION INPUT ;
    USE SIGNAL ;
    PORT
      LAYER met3 ;
        RECT 0.000 1103.000 4.000 1103.600 ;
    END
  END la_data_in[44]
  PIN la_data_in[45]
    DIRECTION INPUT ;
    USE SIGNAL ;
    PORT
      LAYER met3 ;
        RECT 0.000 1109.800 4.000 1110.400 ;
    END
  END la_data_in[45]
  PIN la_data_in[46]
    DIRECTION INPUT ;
    USE SIGNAL ;
    PORT
      LAYER met3 ;
        RECT 0.000 1116.600 4.000 1117.200 ;
    END
  END la_data_in[46]
  PIN la_data_in[47]
    DIRECTION INPUT ;
    USE SIGNAL ;
    PORT
      LAYER met3 ;
        RECT 0.000 1123.400 4.000 1124.000 ;
    END
  END la_data_in[47]
  PIN la_data_in[48]
    DIRECTION INPUT ;
    USE SIGNAL ;
    PORT
      LAYER met3 ;
        RECT 0.000 1130.200 4.000 1130.800 ;
    END
  END la_data_in[48]
  PIN la_data_in[49]
    DIRECTION INPUT ;
    USE SIGNAL ;
    PORT
      LAYER met3 ;
        RECT 0.000 1137.000 4.000 1137.600 ;
    END
  END la_data_in[49]
  PIN la_data_in[4]
    DIRECTION INPUT ;
    USE SIGNAL ;
    PORT
      LAYER met3 ;
        RECT 0.000 831.000 4.000 831.600 ;
    END
  END la_data_in[4]
  PIN la_data_in[50]
    DIRECTION INPUT ;
    USE SIGNAL ;
    PORT
      LAYER met3 ;
        RECT 0.000 1143.800 4.000 1144.400 ;
    END
  END la_data_in[50]
  PIN la_data_in[51]
    DIRECTION INPUT ;
    USE SIGNAL ;
    PORT
      LAYER met3 ;
        RECT 0.000 1150.600 4.000 1151.200 ;
    END
  END la_data_in[51]
  PIN la_data_in[52]
    DIRECTION INPUT ;
    USE SIGNAL ;
    PORT
      LAYER met3 ;
        RECT 0.000 1157.400 4.000 1158.000 ;
    END
  END la_data_in[52]
  PIN la_data_in[53]
    DIRECTION INPUT ;
    USE SIGNAL ;
    PORT
      LAYER met3 ;
        RECT 0.000 1164.200 4.000 1164.800 ;
    END
  END la_data_in[53]
  PIN la_data_in[54]
    DIRECTION INPUT ;
    USE SIGNAL ;
    PORT
      LAYER met3 ;
        RECT 0.000 1171.000 4.000 1171.600 ;
    END
  END la_data_in[54]
  PIN la_data_in[55]
    DIRECTION INPUT ;
    USE SIGNAL ;
    PORT
      LAYER met3 ;
        RECT 0.000 1177.800 4.000 1178.400 ;
    END
  END la_data_in[55]
  PIN la_data_in[56]
    DIRECTION INPUT ;
    USE SIGNAL ;
    PORT
      LAYER met3 ;
        RECT 0.000 1184.600 4.000 1185.200 ;
    END
  END la_data_in[56]
  PIN la_data_in[57]
    DIRECTION INPUT ;
    USE SIGNAL ;
    PORT
      LAYER met3 ;
        RECT 0.000 1191.400 4.000 1192.000 ;
    END
  END la_data_in[57]
  PIN la_data_in[58]
    DIRECTION INPUT ;
    USE SIGNAL ;
    PORT
      LAYER met3 ;
        RECT 0.000 1198.200 4.000 1198.800 ;
    END
  END la_data_in[58]
  PIN la_data_in[59]
    DIRECTION INPUT ;
    USE SIGNAL ;
    PORT
      LAYER met3 ;
        RECT 0.000 1205.000 4.000 1205.600 ;
    END
  END la_data_in[59]
  PIN la_data_in[5]
    DIRECTION INPUT ;
    USE SIGNAL ;
    PORT
      LAYER met3 ;
        RECT 0.000 837.800 4.000 838.400 ;
    END
  END la_data_in[5]
  PIN la_data_in[60]
    DIRECTION INPUT ;
    USE SIGNAL ;
    PORT
      LAYER met3 ;
        RECT 0.000 1211.800 4.000 1212.400 ;
    END
  END la_data_in[60]
  PIN la_data_in[61]
    DIRECTION INPUT ;
    USE SIGNAL ;
    PORT
      LAYER met3 ;
        RECT 0.000 1218.600 4.000 1219.200 ;
    END
  END la_data_in[61]
  PIN la_data_in[62]
    DIRECTION INPUT ;
    USE SIGNAL ;
    PORT
      LAYER met3 ;
        RECT 0.000 1225.400 4.000 1226.000 ;
    END
  END la_data_in[62]
  PIN la_data_in[63]
    DIRECTION INPUT ;
    USE SIGNAL ;
    PORT
      LAYER met3 ;
        RECT 0.000 1232.200 4.000 1232.800 ;
    END
  END la_data_in[63]
  PIN la_data_in[64]
    DIRECTION INPUT ;
    USE SIGNAL ;
    PORT
      LAYER met3 ;
        RECT 0.000 1239.000 4.000 1239.600 ;
    END
  END la_data_in[64]
  PIN la_data_in[65]
    DIRECTION INPUT ;
    USE SIGNAL ;
    PORT
      LAYER met3 ;
        RECT 0.000 1245.800 4.000 1246.400 ;
    END
  END la_data_in[65]
  PIN la_data_in[66]
    DIRECTION INPUT ;
    USE SIGNAL ;
    PORT
      LAYER met3 ;
        RECT 0.000 1252.600 4.000 1253.200 ;
    END
  END la_data_in[66]
  PIN la_data_in[67]
    DIRECTION INPUT ;
    USE SIGNAL ;
    PORT
      LAYER met3 ;
        RECT 0.000 1259.400 4.000 1260.000 ;
    END
  END la_data_in[67]
  PIN la_data_in[68]
    DIRECTION INPUT ;
    USE SIGNAL ;
    PORT
      LAYER met3 ;
        RECT 0.000 1266.200 4.000 1266.800 ;
    END
  END la_data_in[68]
  PIN la_data_in[69]
    DIRECTION INPUT ;
    USE SIGNAL ;
    PORT
      LAYER met3 ;
        RECT 0.000 1273.000 4.000 1273.600 ;
    END
  END la_data_in[69]
  PIN la_data_in[6]
    DIRECTION INPUT ;
    USE SIGNAL ;
    PORT
      LAYER met3 ;
        RECT 0.000 844.600 4.000 845.200 ;
    END
  END la_data_in[6]
  PIN la_data_in[70]
    DIRECTION INPUT ;
    USE SIGNAL ;
    PORT
      LAYER met3 ;
        RECT 0.000 1279.800 4.000 1280.400 ;
    END
  END la_data_in[70]
  PIN la_data_in[71]
    DIRECTION INPUT ;
    USE SIGNAL ;
    PORT
      LAYER met3 ;
        RECT 0.000 1286.600 4.000 1287.200 ;
    END
  END la_data_in[71]
  PIN la_data_in[72]
    DIRECTION INPUT ;
    USE SIGNAL ;
    PORT
      LAYER met3 ;
        RECT 0.000 1293.400 4.000 1294.000 ;
    END
  END la_data_in[72]
  PIN la_data_in[73]
    DIRECTION INPUT ;
    USE SIGNAL ;
    PORT
      LAYER met3 ;
        RECT 0.000 1300.200 4.000 1300.800 ;
    END
  END la_data_in[73]
  PIN la_data_in[74]
    DIRECTION INPUT ;
    USE SIGNAL ;
    PORT
      LAYER met3 ;
        RECT 0.000 1307.000 4.000 1307.600 ;
    END
  END la_data_in[74]
  PIN la_data_in[75]
    DIRECTION INPUT ;
    USE SIGNAL ;
    PORT
      LAYER met3 ;
        RECT 0.000 1313.800 4.000 1314.400 ;
    END
  END la_data_in[75]
  PIN la_data_in[76]
    DIRECTION INPUT ;
    USE SIGNAL ;
    PORT
      LAYER met3 ;
        RECT 0.000 1320.600 4.000 1321.200 ;
    END
  END la_data_in[76]
  PIN la_data_in[77]
    DIRECTION INPUT ;
    USE SIGNAL ;
    PORT
      LAYER met3 ;
        RECT 0.000 1327.400 4.000 1328.000 ;
    END
  END la_data_in[77]
  PIN la_data_in[78]
    DIRECTION INPUT ;
    USE SIGNAL ;
    PORT
      LAYER met3 ;
        RECT 0.000 1334.200 4.000 1334.800 ;
    END
  END la_data_in[78]
  PIN la_data_in[79]
    DIRECTION INPUT ;
    USE SIGNAL ;
    PORT
      LAYER met3 ;
        RECT 0.000 1341.000 4.000 1341.600 ;
    END
  END la_data_in[79]
  PIN la_data_in[7]
    DIRECTION INPUT ;
    USE SIGNAL ;
    PORT
      LAYER met3 ;
        RECT 0.000 851.400 4.000 852.000 ;
    END
  END la_data_in[7]
  PIN la_data_in[80]
    DIRECTION INPUT ;
    USE SIGNAL ;
    PORT
      LAYER met3 ;
        RECT 0.000 1347.800 4.000 1348.400 ;
    END
  END la_data_in[80]
  PIN la_data_in[81]
    DIRECTION INPUT ;
    USE SIGNAL ;
    PORT
      LAYER met3 ;
        RECT 0.000 1354.600 4.000 1355.200 ;
    END
  END la_data_in[81]
  PIN la_data_in[82]
    DIRECTION INPUT ;
    USE SIGNAL ;
    PORT
      LAYER met3 ;
        RECT 0.000 1361.400 4.000 1362.000 ;
    END
  END la_data_in[82]
  PIN la_data_in[83]
    DIRECTION INPUT ;
    USE SIGNAL ;
    PORT
      LAYER met3 ;
        RECT 0.000 1368.200 4.000 1368.800 ;
    END
  END la_data_in[83]
  PIN la_data_in[84]
    DIRECTION INPUT ;
    USE SIGNAL ;
    PORT
      LAYER met3 ;
        RECT 0.000 1375.000 4.000 1375.600 ;
    END
  END la_data_in[84]
  PIN la_data_in[85]
    DIRECTION INPUT ;
    USE SIGNAL ;
    PORT
      LAYER met3 ;
        RECT 0.000 1381.800 4.000 1382.400 ;
    END
  END la_data_in[85]
  PIN la_data_in[86]
    DIRECTION INPUT ;
    USE SIGNAL ;
    PORT
      LAYER met3 ;
        RECT 0.000 1388.600 4.000 1389.200 ;
    END
  END la_data_in[86]
  PIN la_data_in[87]
    DIRECTION INPUT ;
    USE SIGNAL ;
    PORT
      LAYER met3 ;
        RECT 0.000 1395.400 4.000 1396.000 ;
    END
  END la_data_in[87]
  PIN la_data_in[88]
    DIRECTION INPUT ;
    USE SIGNAL ;
    PORT
      LAYER met3 ;
        RECT 0.000 1402.200 4.000 1402.800 ;
    END
  END la_data_in[88]
  PIN la_data_in[89]
    DIRECTION INPUT ;
    USE SIGNAL ;
    PORT
      LAYER met3 ;
        RECT 0.000 1409.000 4.000 1409.600 ;
    END
  END la_data_in[89]
  PIN la_data_in[8]
    DIRECTION INPUT ;
    USE SIGNAL ;
    PORT
      LAYER met3 ;
        RECT 0.000 858.200 4.000 858.800 ;
    END
  END la_data_in[8]
  PIN la_data_in[90]
    DIRECTION INPUT ;
    USE SIGNAL ;
    PORT
      LAYER met3 ;
        RECT 0.000 1415.800 4.000 1416.400 ;
    END
  END la_data_in[90]
  PIN la_data_in[91]
    DIRECTION INPUT ;
    USE SIGNAL ;
    PORT
      LAYER met3 ;
        RECT 0.000 1422.600 4.000 1423.200 ;
    END
  END la_data_in[91]
  PIN la_data_in[92]
    DIRECTION INPUT ;
    USE SIGNAL ;
    PORT
      LAYER met3 ;
        RECT 0.000 1429.400 4.000 1430.000 ;
    END
  END la_data_in[92]
  PIN la_data_in[93]
    DIRECTION INPUT ;
    USE SIGNAL ;
    PORT
      LAYER met3 ;
        RECT 0.000 1436.200 4.000 1436.800 ;
    END
  END la_data_in[93]
  PIN la_data_in[94]
    DIRECTION INPUT ;
    USE SIGNAL ;
    PORT
      LAYER met3 ;
        RECT 0.000 1443.000 4.000 1443.600 ;
    END
  END la_data_in[94]
  PIN la_data_in[95]
    DIRECTION INPUT ;
    USE SIGNAL ;
    PORT
      LAYER met3 ;
        RECT 0.000 1449.800 4.000 1450.400 ;
    END
  END la_data_in[95]
  PIN la_data_in[96]
    DIRECTION INPUT ;
    USE SIGNAL ;
    PORT
      LAYER met3 ;
        RECT 0.000 1456.600 4.000 1457.200 ;
    END
  END la_data_in[96]
  PIN la_data_in[97]
    DIRECTION INPUT ;
    USE SIGNAL ;
    PORT
      LAYER met3 ;
        RECT 0.000 1463.400 4.000 1464.000 ;
    END
  END la_data_in[97]
  PIN la_data_in[98]
    DIRECTION INPUT ;
    USE SIGNAL ;
    PORT
      LAYER met3 ;
        RECT 0.000 1470.200 4.000 1470.800 ;
    END
  END la_data_in[98]
  PIN la_data_in[99]
    DIRECTION INPUT ;
    USE SIGNAL ;
    PORT
      LAYER met3 ;
        RECT 0.000 1477.000 4.000 1477.600 ;
    END
  END la_data_in[99]
  PIN la_data_in[9]
    DIRECTION INPUT ;
    USE SIGNAL ;
    PORT
      LAYER met3 ;
        RECT 0.000 865.000 4.000 865.600 ;
    END
  END la_data_in[9]
  PIN la_data_out[0]
    DIRECTION OUTPUT ;
    USE SIGNAL ;
    PORT
      LAYER met3 ;
        RECT 0.000 1674.200 4.000 1674.800 ;
    END
  END la_data_out[0]
  PIN la_data_out[100]
    DIRECTION OUTPUT ;
    USE SIGNAL ;
    PORT
      LAYER met3 ;
        RECT 0.000 2354.200 4.000 2354.800 ;
    END
  END la_data_out[100]
  PIN la_data_out[101]
    DIRECTION OUTPUT ;
    USE SIGNAL ;
    PORT
      LAYER met3 ;
        RECT 0.000 2361.000 4.000 2361.600 ;
    END
  END la_data_out[101]
  PIN la_data_out[102]
    DIRECTION OUTPUT ;
    USE SIGNAL ;
    PORT
      LAYER met3 ;
        RECT 0.000 2367.800 4.000 2368.400 ;
    END
  END la_data_out[102]
  PIN la_data_out[103]
    DIRECTION OUTPUT ;
    USE SIGNAL ;
    PORT
      LAYER met3 ;
        RECT 0.000 2374.600 4.000 2375.200 ;
    END
  END la_data_out[103]
  PIN la_data_out[104]
    DIRECTION OUTPUT ;
    USE SIGNAL ;
    PORT
      LAYER met3 ;
        RECT 0.000 2381.400 4.000 2382.000 ;
    END
  END la_data_out[104]
  PIN la_data_out[105]
    DIRECTION OUTPUT ;
    USE SIGNAL ;
    PORT
      LAYER met3 ;
        RECT 0.000 2388.200 4.000 2388.800 ;
    END
  END la_data_out[105]
  PIN la_data_out[106]
    DIRECTION OUTPUT ;
    USE SIGNAL ;
    PORT
      LAYER met3 ;
        RECT 0.000 2395.000 4.000 2395.600 ;
    END
  END la_data_out[106]
  PIN la_data_out[107]
    DIRECTION OUTPUT ;
    USE SIGNAL ;
    PORT
      LAYER met3 ;
        RECT 0.000 2401.800 4.000 2402.400 ;
    END
  END la_data_out[107]
  PIN la_data_out[108]
    DIRECTION OUTPUT ;
    USE SIGNAL ;
    PORT
      LAYER met3 ;
        RECT 0.000 2408.600 4.000 2409.200 ;
    END
  END la_data_out[108]
  PIN la_data_out[109]
    DIRECTION OUTPUT ;
    USE SIGNAL ;
    PORT
      LAYER met3 ;
        RECT 0.000 2415.400 4.000 2416.000 ;
    END
  END la_data_out[109]
  PIN la_data_out[10]
    DIRECTION OUTPUT ;
    USE SIGNAL ;
    PORT
      LAYER met3 ;
        RECT 0.000 1742.200 4.000 1742.800 ;
    END
  END la_data_out[10]
  PIN la_data_out[110]
    DIRECTION OUTPUT ;
    USE SIGNAL ;
    PORT
      LAYER met3 ;
        RECT 0.000 2422.200 4.000 2422.800 ;
    END
  END la_data_out[110]
  PIN la_data_out[111]
    DIRECTION OUTPUT ;
    USE SIGNAL ;
    PORT
      LAYER met3 ;
        RECT 0.000 2429.000 4.000 2429.600 ;
    END
  END la_data_out[111]
  PIN la_data_out[112]
    DIRECTION OUTPUT ;
    USE SIGNAL ;
    PORT
      LAYER met3 ;
        RECT 0.000 2435.800 4.000 2436.400 ;
    END
  END la_data_out[112]
  PIN la_data_out[113]
    DIRECTION OUTPUT ;
    USE SIGNAL ;
    PORT
      LAYER met3 ;
        RECT 0.000 2442.600 4.000 2443.200 ;
    END
  END la_data_out[113]
  PIN la_data_out[114]
    DIRECTION OUTPUT ;
    USE SIGNAL ;
    PORT
      LAYER met3 ;
        RECT 0.000 2449.400 4.000 2450.000 ;
    END
  END la_data_out[114]
  PIN la_data_out[115]
    DIRECTION OUTPUT ;
    USE SIGNAL ;
    PORT
      LAYER met3 ;
        RECT 0.000 2456.200 4.000 2456.800 ;
    END
  END la_data_out[115]
  PIN la_data_out[116]
    DIRECTION OUTPUT ;
    USE SIGNAL ;
    PORT
      LAYER met3 ;
        RECT 0.000 2463.000 4.000 2463.600 ;
    END
  END la_data_out[116]
  PIN la_data_out[117]
    DIRECTION OUTPUT ;
    USE SIGNAL ;
    PORT
      LAYER met3 ;
        RECT 0.000 2469.800 4.000 2470.400 ;
    END
  END la_data_out[117]
  PIN la_data_out[118]
    DIRECTION OUTPUT ;
    USE SIGNAL ;
    PORT
      LAYER met3 ;
        RECT 0.000 2476.600 4.000 2477.200 ;
    END
  END la_data_out[118]
  PIN la_data_out[119]
    DIRECTION OUTPUT ;
    USE SIGNAL ;
    PORT
      LAYER met3 ;
        RECT 0.000 2483.400 4.000 2484.000 ;
    END
  END la_data_out[119]
  PIN la_data_out[11]
    DIRECTION OUTPUT ;
    USE SIGNAL ;
    PORT
      LAYER met3 ;
        RECT 0.000 1749.000 4.000 1749.600 ;
    END
  END la_data_out[11]
  PIN la_data_out[120]
    DIRECTION OUTPUT ;
    USE SIGNAL ;
    PORT
      LAYER met3 ;
        RECT 0.000 2490.200 4.000 2490.800 ;
    END
  END la_data_out[120]
  PIN la_data_out[121]
    DIRECTION OUTPUT ;
    USE SIGNAL ;
    PORT
      LAYER met3 ;
        RECT 0.000 2497.000 4.000 2497.600 ;
    END
  END la_data_out[121]
  PIN la_data_out[122]
    DIRECTION OUTPUT ;
    USE SIGNAL ;
    PORT
      LAYER met3 ;
        RECT 0.000 2503.800 4.000 2504.400 ;
    END
  END la_data_out[122]
  PIN la_data_out[123]
    DIRECTION OUTPUT ;
    USE SIGNAL ;
    PORT
      LAYER met3 ;
        RECT 0.000 2510.600 4.000 2511.200 ;
    END
  END la_data_out[123]
  PIN la_data_out[124]
    DIRECTION OUTPUT ;
    USE SIGNAL ;
    PORT
      LAYER met3 ;
        RECT 0.000 2517.400 4.000 2518.000 ;
    END
  END la_data_out[124]
  PIN la_data_out[125]
    DIRECTION OUTPUT ;
    USE SIGNAL ;
    PORT
      LAYER met3 ;
        RECT 0.000 2524.200 4.000 2524.800 ;
    END
  END la_data_out[125]
  PIN la_data_out[126]
    DIRECTION OUTPUT ;
    USE SIGNAL ;
    PORT
      LAYER met3 ;
        RECT 0.000 2531.000 4.000 2531.600 ;
    END
  END la_data_out[126]
  PIN la_data_out[127]
    DIRECTION OUTPUT ;
    USE SIGNAL ;
    PORT
      LAYER met3 ;
        RECT 0.000 2537.800 4.000 2538.400 ;
    END
  END la_data_out[127]
  PIN la_data_out[12]
    DIRECTION OUTPUT ;
    USE SIGNAL ;
    PORT
      LAYER met3 ;
        RECT 0.000 1755.800 4.000 1756.400 ;
    END
  END la_data_out[12]
  PIN la_data_out[13]
    DIRECTION OUTPUT ;
    USE SIGNAL ;
    PORT
      LAYER met3 ;
        RECT 0.000 1762.600 4.000 1763.200 ;
    END
  END la_data_out[13]
  PIN la_data_out[14]
    DIRECTION OUTPUT ;
    USE SIGNAL ;
    PORT
      LAYER met3 ;
        RECT 0.000 1769.400 4.000 1770.000 ;
    END
  END la_data_out[14]
  PIN la_data_out[15]
    DIRECTION OUTPUT ;
    USE SIGNAL ;
    PORT
      LAYER met3 ;
        RECT 0.000 1776.200 4.000 1776.800 ;
    END
  END la_data_out[15]
  PIN la_data_out[16]
    DIRECTION OUTPUT ;
    USE SIGNAL ;
    PORT
      LAYER met3 ;
        RECT 0.000 1783.000 4.000 1783.600 ;
    END
  END la_data_out[16]
  PIN la_data_out[17]
    DIRECTION OUTPUT ;
    USE SIGNAL ;
    PORT
      LAYER met3 ;
        RECT 0.000 1789.800 4.000 1790.400 ;
    END
  END la_data_out[17]
  PIN la_data_out[18]
    DIRECTION OUTPUT ;
    USE SIGNAL ;
    PORT
      LAYER met3 ;
        RECT 0.000 1796.600 4.000 1797.200 ;
    END
  END la_data_out[18]
  PIN la_data_out[19]
    DIRECTION OUTPUT ;
    USE SIGNAL ;
    PORT
      LAYER met3 ;
        RECT 0.000 1803.400 4.000 1804.000 ;
    END
  END la_data_out[19]
  PIN la_data_out[1]
    DIRECTION OUTPUT ;
    USE SIGNAL ;
    PORT
      LAYER met3 ;
        RECT 0.000 1681.000 4.000 1681.600 ;
    END
  END la_data_out[1]
  PIN la_data_out[20]
    DIRECTION OUTPUT ;
    USE SIGNAL ;
    PORT
      LAYER met3 ;
        RECT 0.000 1810.200 4.000 1810.800 ;
    END
  END la_data_out[20]
  PIN la_data_out[21]
    DIRECTION OUTPUT ;
    USE SIGNAL ;
    PORT
      LAYER met3 ;
        RECT 0.000 1817.000 4.000 1817.600 ;
    END
  END la_data_out[21]
  PIN la_data_out[22]
    DIRECTION OUTPUT ;
    USE SIGNAL ;
    PORT
      LAYER met3 ;
        RECT 0.000 1823.800 4.000 1824.400 ;
    END
  END la_data_out[22]
  PIN la_data_out[23]
    DIRECTION OUTPUT ;
    USE SIGNAL ;
    PORT
      LAYER met3 ;
        RECT 0.000 1830.600 4.000 1831.200 ;
    END
  END la_data_out[23]
  PIN la_data_out[24]
    DIRECTION OUTPUT ;
    USE SIGNAL ;
    PORT
      LAYER met3 ;
        RECT 0.000 1837.400 4.000 1838.000 ;
    END
  END la_data_out[24]
  PIN la_data_out[25]
    DIRECTION OUTPUT ;
    USE SIGNAL ;
    PORT
      LAYER met3 ;
        RECT 0.000 1844.200 4.000 1844.800 ;
    END
  END la_data_out[25]
  PIN la_data_out[26]
    DIRECTION OUTPUT ;
    USE SIGNAL ;
    PORT
      LAYER met3 ;
        RECT 0.000 1851.000 4.000 1851.600 ;
    END
  END la_data_out[26]
  PIN la_data_out[27]
    DIRECTION OUTPUT ;
    USE SIGNAL ;
    PORT
      LAYER met3 ;
        RECT 0.000 1857.800 4.000 1858.400 ;
    END
  END la_data_out[27]
  PIN la_data_out[28]
    DIRECTION OUTPUT ;
    USE SIGNAL ;
    PORT
      LAYER met3 ;
        RECT 0.000 1864.600 4.000 1865.200 ;
    END
  END la_data_out[28]
  PIN la_data_out[29]
    DIRECTION OUTPUT ;
    USE SIGNAL ;
    PORT
      LAYER met3 ;
        RECT 0.000 1871.400 4.000 1872.000 ;
    END
  END la_data_out[29]
  PIN la_data_out[2]
    DIRECTION OUTPUT ;
    USE SIGNAL ;
    PORT
      LAYER met3 ;
        RECT 0.000 1687.800 4.000 1688.400 ;
    END
  END la_data_out[2]
  PIN la_data_out[30]
    DIRECTION OUTPUT ;
    USE SIGNAL ;
    PORT
      LAYER met3 ;
        RECT 0.000 1878.200 4.000 1878.800 ;
    END
  END la_data_out[30]
  PIN la_data_out[31]
    DIRECTION OUTPUT ;
    USE SIGNAL ;
    PORT
      LAYER met3 ;
        RECT 0.000 1885.000 4.000 1885.600 ;
    END
  END la_data_out[31]
  PIN la_data_out[32]
    DIRECTION OUTPUT ;
    USE SIGNAL ;
    PORT
      LAYER met3 ;
        RECT 0.000 1891.800 4.000 1892.400 ;
    END
  END la_data_out[32]
  PIN la_data_out[33]
    DIRECTION OUTPUT ;
    USE SIGNAL ;
    PORT
      LAYER met3 ;
        RECT 0.000 1898.600 4.000 1899.200 ;
    END
  END la_data_out[33]
  PIN la_data_out[34]
    DIRECTION OUTPUT ;
    USE SIGNAL ;
    PORT
      LAYER met3 ;
        RECT 0.000 1905.400 4.000 1906.000 ;
    END
  END la_data_out[34]
  PIN la_data_out[35]
    DIRECTION OUTPUT ;
    USE SIGNAL ;
    PORT
      LAYER met3 ;
        RECT 0.000 1912.200 4.000 1912.800 ;
    END
  END la_data_out[35]
  PIN la_data_out[36]
    DIRECTION OUTPUT ;
    USE SIGNAL ;
    PORT
      LAYER met3 ;
        RECT 0.000 1919.000 4.000 1919.600 ;
    END
  END la_data_out[36]
  PIN la_data_out[37]
    DIRECTION OUTPUT ;
    USE SIGNAL ;
    PORT
      LAYER met3 ;
        RECT 0.000 1925.800 4.000 1926.400 ;
    END
  END la_data_out[37]
  PIN la_data_out[38]
    DIRECTION OUTPUT ;
    USE SIGNAL ;
    PORT
      LAYER met3 ;
        RECT 0.000 1932.600 4.000 1933.200 ;
    END
  END la_data_out[38]
  PIN la_data_out[39]
    DIRECTION OUTPUT ;
    USE SIGNAL ;
    PORT
      LAYER met3 ;
        RECT 0.000 1939.400 4.000 1940.000 ;
    END
  END la_data_out[39]
  PIN la_data_out[3]
    DIRECTION OUTPUT ;
    USE SIGNAL ;
    PORT
      LAYER met3 ;
        RECT 0.000 1694.600 4.000 1695.200 ;
    END
  END la_data_out[3]
  PIN la_data_out[40]
    DIRECTION OUTPUT ;
    USE SIGNAL ;
    PORT
      LAYER met3 ;
        RECT 0.000 1946.200 4.000 1946.800 ;
    END
  END la_data_out[40]
  PIN la_data_out[41]
    DIRECTION OUTPUT ;
    USE SIGNAL ;
    PORT
      LAYER met3 ;
        RECT 0.000 1953.000 4.000 1953.600 ;
    END
  END la_data_out[41]
  PIN la_data_out[42]
    DIRECTION OUTPUT ;
    USE SIGNAL ;
    PORT
      LAYER met3 ;
        RECT 0.000 1959.800 4.000 1960.400 ;
    END
  END la_data_out[42]
  PIN la_data_out[43]
    DIRECTION OUTPUT ;
    USE SIGNAL ;
    PORT
      LAYER met3 ;
        RECT 0.000 1966.600 4.000 1967.200 ;
    END
  END la_data_out[43]
  PIN la_data_out[44]
    DIRECTION OUTPUT ;
    USE SIGNAL ;
    PORT
      LAYER met3 ;
        RECT 0.000 1973.400 4.000 1974.000 ;
    END
  END la_data_out[44]
  PIN la_data_out[45]
    DIRECTION OUTPUT ;
    USE SIGNAL ;
    PORT
      LAYER met3 ;
        RECT 0.000 1980.200 4.000 1980.800 ;
    END
  END la_data_out[45]
  PIN la_data_out[46]
    DIRECTION OUTPUT ;
    USE SIGNAL ;
    PORT
      LAYER met3 ;
        RECT 0.000 1987.000 4.000 1987.600 ;
    END
  END la_data_out[46]
  PIN la_data_out[47]
    DIRECTION OUTPUT ;
    USE SIGNAL ;
    PORT
      LAYER met3 ;
        RECT 0.000 1993.800 4.000 1994.400 ;
    END
  END la_data_out[47]
  PIN la_data_out[48]
    DIRECTION OUTPUT ;
    USE SIGNAL ;
    PORT
      LAYER met3 ;
        RECT 0.000 2000.600 4.000 2001.200 ;
    END
  END la_data_out[48]
  PIN la_data_out[49]
    DIRECTION OUTPUT ;
    USE SIGNAL ;
    PORT
      LAYER met3 ;
        RECT 0.000 2007.400 4.000 2008.000 ;
    END
  END la_data_out[49]
  PIN la_data_out[4]
    DIRECTION OUTPUT ;
    USE SIGNAL ;
    PORT
      LAYER met3 ;
        RECT 0.000 1701.400 4.000 1702.000 ;
    END
  END la_data_out[4]
  PIN la_data_out[50]
    DIRECTION OUTPUT ;
    USE SIGNAL ;
    PORT
      LAYER met3 ;
        RECT 0.000 2014.200 4.000 2014.800 ;
    END
  END la_data_out[50]
  PIN la_data_out[51]
    DIRECTION OUTPUT ;
    USE SIGNAL ;
    PORT
      LAYER met3 ;
        RECT 0.000 2021.000 4.000 2021.600 ;
    END
  END la_data_out[51]
  PIN la_data_out[52]
    DIRECTION OUTPUT ;
    USE SIGNAL ;
    PORT
      LAYER met3 ;
        RECT 0.000 2027.800 4.000 2028.400 ;
    END
  END la_data_out[52]
  PIN la_data_out[53]
    DIRECTION OUTPUT ;
    USE SIGNAL ;
    PORT
      LAYER met3 ;
        RECT 0.000 2034.600 4.000 2035.200 ;
    END
  END la_data_out[53]
  PIN la_data_out[54]
    DIRECTION OUTPUT ;
    USE SIGNAL ;
    PORT
      LAYER met3 ;
        RECT 0.000 2041.400 4.000 2042.000 ;
    END
  END la_data_out[54]
  PIN la_data_out[55]
    DIRECTION OUTPUT ;
    USE SIGNAL ;
    PORT
      LAYER met3 ;
        RECT 0.000 2048.200 4.000 2048.800 ;
    END
  END la_data_out[55]
  PIN la_data_out[56]
    DIRECTION OUTPUT ;
    USE SIGNAL ;
    PORT
      LAYER met3 ;
        RECT 0.000 2055.000 4.000 2055.600 ;
    END
  END la_data_out[56]
  PIN la_data_out[57]
    DIRECTION OUTPUT ;
    USE SIGNAL ;
    PORT
      LAYER met3 ;
        RECT 0.000 2061.800 4.000 2062.400 ;
    END
  END la_data_out[57]
  PIN la_data_out[58]
    DIRECTION OUTPUT ;
    USE SIGNAL ;
    PORT
      LAYER met3 ;
        RECT 0.000 2068.600 4.000 2069.200 ;
    END
  END la_data_out[58]
  PIN la_data_out[59]
    DIRECTION OUTPUT ;
    USE SIGNAL ;
    PORT
      LAYER met3 ;
        RECT 0.000 2075.400 4.000 2076.000 ;
    END
  END la_data_out[59]
  PIN la_data_out[5]
    DIRECTION OUTPUT ;
    USE SIGNAL ;
    PORT
      LAYER met3 ;
        RECT 0.000 1708.200 4.000 1708.800 ;
    END
  END la_data_out[5]
  PIN la_data_out[60]
    DIRECTION OUTPUT ;
    USE SIGNAL ;
    PORT
      LAYER met3 ;
        RECT 0.000 2082.200 4.000 2082.800 ;
    END
  END la_data_out[60]
  PIN la_data_out[61]
    DIRECTION OUTPUT ;
    USE SIGNAL ;
    PORT
      LAYER met3 ;
        RECT 0.000 2089.000 4.000 2089.600 ;
    END
  END la_data_out[61]
  PIN la_data_out[62]
    DIRECTION OUTPUT ;
    USE SIGNAL ;
    PORT
      LAYER met3 ;
        RECT 0.000 2095.800 4.000 2096.400 ;
    END
  END la_data_out[62]
  PIN la_data_out[63]
    DIRECTION OUTPUT ;
    USE SIGNAL ;
    PORT
      LAYER met3 ;
        RECT 0.000 2102.600 4.000 2103.200 ;
    END
  END la_data_out[63]
  PIN la_data_out[64]
    DIRECTION OUTPUT ;
    USE SIGNAL ;
    PORT
      LAYER met3 ;
        RECT 0.000 2109.400 4.000 2110.000 ;
    END
  END la_data_out[64]
  PIN la_data_out[65]
    DIRECTION OUTPUT ;
    USE SIGNAL ;
    PORT
      LAYER met3 ;
        RECT 0.000 2116.200 4.000 2116.800 ;
    END
  END la_data_out[65]
  PIN la_data_out[66]
    DIRECTION OUTPUT ;
    USE SIGNAL ;
    PORT
      LAYER met3 ;
        RECT 0.000 2123.000 4.000 2123.600 ;
    END
  END la_data_out[66]
  PIN la_data_out[67]
    DIRECTION OUTPUT ;
    USE SIGNAL ;
    PORT
      LAYER met3 ;
        RECT 0.000 2129.800 4.000 2130.400 ;
    END
  END la_data_out[67]
  PIN la_data_out[68]
    DIRECTION OUTPUT ;
    USE SIGNAL ;
    PORT
      LAYER met3 ;
        RECT 0.000 2136.600 4.000 2137.200 ;
    END
  END la_data_out[68]
  PIN la_data_out[69]
    DIRECTION OUTPUT ;
    USE SIGNAL ;
    PORT
      LAYER met3 ;
        RECT 0.000 2143.400 4.000 2144.000 ;
    END
  END la_data_out[69]
  PIN la_data_out[6]
    DIRECTION OUTPUT ;
    USE SIGNAL ;
    PORT
      LAYER met3 ;
        RECT 0.000 1715.000 4.000 1715.600 ;
    END
  END la_data_out[6]
  PIN la_data_out[70]
    DIRECTION OUTPUT ;
    USE SIGNAL ;
    PORT
      LAYER met3 ;
        RECT 0.000 2150.200 4.000 2150.800 ;
    END
  END la_data_out[70]
  PIN la_data_out[71]
    DIRECTION OUTPUT ;
    USE SIGNAL ;
    PORT
      LAYER met3 ;
        RECT 0.000 2157.000 4.000 2157.600 ;
    END
  END la_data_out[71]
  PIN la_data_out[72]
    DIRECTION OUTPUT ;
    USE SIGNAL ;
    PORT
      LAYER met3 ;
        RECT 0.000 2163.800 4.000 2164.400 ;
    END
  END la_data_out[72]
  PIN la_data_out[73]
    DIRECTION OUTPUT ;
    USE SIGNAL ;
    PORT
      LAYER met3 ;
        RECT 0.000 2170.600 4.000 2171.200 ;
    END
  END la_data_out[73]
  PIN la_data_out[74]
    DIRECTION OUTPUT ;
    USE SIGNAL ;
    PORT
      LAYER met3 ;
        RECT 0.000 2177.400 4.000 2178.000 ;
    END
  END la_data_out[74]
  PIN la_data_out[75]
    DIRECTION OUTPUT ;
    USE SIGNAL ;
    PORT
      LAYER met3 ;
        RECT 0.000 2184.200 4.000 2184.800 ;
    END
  END la_data_out[75]
  PIN la_data_out[76]
    DIRECTION OUTPUT ;
    USE SIGNAL ;
    PORT
      LAYER met3 ;
        RECT 0.000 2191.000 4.000 2191.600 ;
    END
  END la_data_out[76]
  PIN la_data_out[77]
    DIRECTION OUTPUT ;
    USE SIGNAL ;
    PORT
      LAYER met3 ;
        RECT 0.000 2197.800 4.000 2198.400 ;
    END
  END la_data_out[77]
  PIN la_data_out[78]
    DIRECTION OUTPUT ;
    USE SIGNAL ;
    PORT
      LAYER met3 ;
        RECT 0.000 2204.600 4.000 2205.200 ;
    END
  END la_data_out[78]
  PIN la_data_out[79]
    DIRECTION OUTPUT ;
    USE SIGNAL ;
    PORT
      LAYER met3 ;
        RECT 0.000 2211.400 4.000 2212.000 ;
    END
  END la_data_out[79]
  PIN la_data_out[7]
    DIRECTION OUTPUT ;
    USE SIGNAL ;
    PORT
      LAYER met3 ;
        RECT 0.000 1721.800 4.000 1722.400 ;
    END
  END la_data_out[7]
  PIN la_data_out[80]
    DIRECTION OUTPUT ;
    USE SIGNAL ;
    PORT
      LAYER met3 ;
        RECT 0.000 2218.200 4.000 2218.800 ;
    END
  END la_data_out[80]
  PIN la_data_out[81]
    DIRECTION OUTPUT ;
    USE SIGNAL ;
    PORT
      LAYER met3 ;
        RECT 0.000 2225.000 4.000 2225.600 ;
    END
  END la_data_out[81]
  PIN la_data_out[82]
    DIRECTION OUTPUT ;
    USE SIGNAL ;
    PORT
      LAYER met3 ;
        RECT 0.000 2231.800 4.000 2232.400 ;
    END
  END la_data_out[82]
  PIN la_data_out[83]
    DIRECTION OUTPUT ;
    USE SIGNAL ;
    PORT
      LAYER met3 ;
        RECT 0.000 2238.600 4.000 2239.200 ;
    END
  END la_data_out[83]
  PIN la_data_out[84]
    DIRECTION OUTPUT ;
    USE SIGNAL ;
    PORT
      LAYER met3 ;
        RECT 0.000 2245.400 4.000 2246.000 ;
    END
  END la_data_out[84]
  PIN la_data_out[85]
    DIRECTION OUTPUT ;
    USE SIGNAL ;
    PORT
      LAYER met3 ;
        RECT 0.000 2252.200 4.000 2252.800 ;
    END
  END la_data_out[85]
  PIN la_data_out[86]
    DIRECTION OUTPUT ;
    USE SIGNAL ;
    PORT
      LAYER met3 ;
        RECT 0.000 2259.000 4.000 2259.600 ;
    END
  END la_data_out[86]
  PIN la_data_out[87]
    DIRECTION OUTPUT ;
    USE SIGNAL ;
    PORT
      LAYER met3 ;
        RECT 0.000 2265.800 4.000 2266.400 ;
    END
  END la_data_out[87]
  PIN la_data_out[88]
    DIRECTION OUTPUT ;
    USE SIGNAL ;
    PORT
      LAYER met3 ;
        RECT 0.000 2272.600 4.000 2273.200 ;
    END
  END la_data_out[88]
  PIN la_data_out[89]
    DIRECTION OUTPUT ;
    USE SIGNAL ;
    PORT
      LAYER met3 ;
        RECT 0.000 2279.400 4.000 2280.000 ;
    END
  END la_data_out[89]
  PIN la_data_out[8]
    DIRECTION OUTPUT ;
    USE SIGNAL ;
    PORT
      LAYER met3 ;
        RECT 0.000 1728.600 4.000 1729.200 ;
    END
  END la_data_out[8]
  PIN la_data_out[90]
    DIRECTION OUTPUT ;
    USE SIGNAL ;
    PORT
      LAYER met3 ;
        RECT 0.000 2286.200 4.000 2286.800 ;
    END
  END la_data_out[90]
  PIN la_data_out[91]
    DIRECTION OUTPUT ;
    USE SIGNAL ;
    PORT
      LAYER met3 ;
        RECT 0.000 2293.000 4.000 2293.600 ;
    END
  END la_data_out[91]
  PIN la_data_out[92]
    DIRECTION OUTPUT ;
    USE SIGNAL ;
    PORT
      LAYER met3 ;
        RECT 0.000 2299.800 4.000 2300.400 ;
    END
  END la_data_out[92]
  PIN la_data_out[93]
    DIRECTION OUTPUT ;
    USE SIGNAL ;
    PORT
      LAYER met3 ;
        RECT 0.000 2306.600 4.000 2307.200 ;
    END
  END la_data_out[93]
  PIN la_data_out[94]
    DIRECTION OUTPUT ;
    USE SIGNAL ;
    PORT
      LAYER met3 ;
        RECT 0.000 2313.400 4.000 2314.000 ;
    END
  END la_data_out[94]
  PIN la_data_out[95]
    DIRECTION OUTPUT ;
    USE SIGNAL ;
    PORT
      LAYER met3 ;
        RECT 0.000 2320.200 4.000 2320.800 ;
    END
  END la_data_out[95]
  PIN la_data_out[96]
    DIRECTION OUTPUT ;
    USE SIGNAL ;
    PORT
      LAYER met3 ;
        RECT 0.000 2327.000 4.000 2327.600 ;
    END
  END la_data_out[96]
  PIN la_data_out[97]
    DIRECTION OUTPUT ;
    USE SIGNAL ;
    PORT
      LAYER met3 ;
        RECT 0.000 2333.800 4.000 2334.400 ;
    END
  END la_data_out[97]
  PIN la_data_out[98]
    DIRECTION OUTPUT ;
    USE SIGNAL ;
    PORT
      LAYER met3 ;
        RECT 0.000 2340.600 4.000 2341.200 ;
    END
  END la_data_out[98]
  PIN la_data_out[99]
    DIRECTION OUTPUT ;
    USE SIGNAL ;
    PORT
      LAYER met3 ;
        RECT 0.000 2347.400 4.000 2348.000 ;
    END
  END la_data_out[99]
  PIN la_data_out[9]
    DIRECTION OUTPUT ;
    USE SIGNAL ;
    PORT
      LAYER met3 ;
        RECT 0.000 1735.400 4.000 1736.000 ;
    END
  END la_data_out[9]
  PIN la_oenb[0]
    DIRECTION INPUT ;
    USE SIGNAL ;
    PORT
      LAYER met3 ;
        RECT 0.000 2544.600 4.000 2545.200 ;
    END
  END la_oenb[0]
  PIN la_oenb[100]
    DIRECTION INPUT ;
    USE SIGNAL ;
    PORT
      LAYER met3 ;
        RECT 0.000 3224.600 4.000 3225.200 ;
    END
  END la_oenb[100]
  PIN la_oenb[101]
    DIRECTION INPUT ;
    USE SIGNAL ;
    PORT
      LAYER met3 ;
        RECT 0.000 3231.400 4.000 3232.000 ;
    END
  END la_oenb[101]
  PIN la_oenb[102]
    DIRECTION INPUT ;
    USE SIGNAL ;
    PORT
      LAYER met3 ;
        RECT 0.000 3238.200 4.000 3238.800 ;
    END
  END la_oenb[102]
  PIN la_oenb[103]
    DIRECTION INPUT ;
    USE SIGNAL ;
    PORT
      LAYER met3 ;
        RECT 0.000 3245.000 4.000 3245.600 ;
    END
  END la_oenb[103]
  PIN la_oenb[104]
    DIRECTION INPUT ;
    USE SIGNAL ;
    PORT
      LAYER met3 ;
        RECT 0.000 3251.800 4.000 3252.400 ;
    END
  END la_oenb[104]
  PIN la_oenb[105]
    DIRECTION INPUT ;
    USE SIGNAL ;
    PORT
      LAYER met3 ;
        RECT 0.000 3258.600 4.000 3259.200 ;
    END
  END la_oenb[105]
  PIN la_oenb[106]
    DIRECTION INPUT ;
    USE SIGNAL ;
    PORT
      LAYER met3 ;
        RECT 0.000 3265.400 4.000 3266.000 ;
    END
  END la_oenb[106]
  PIN la_oenb[107]
    DIRECTION INPUT ;
    USE SIGNAL ;
    PORT
      LAYER met3 ;
        RECT 0.000 3272.200 4.000 3272.800 ;
    END
  END la_oenb[107]
  PIN la_oenb[108]
    DIRECTION INPUT ;
    USE SIGNAL ;
    PORT
      LAYER met3 ;
        RECT 0.000 3279.000 4.000 3279.600 ;
    END
  END la_oenb[108]
  PIN la_oenb[109]
    DIRECTION INPUT ;
    USE SIGNAL ;
    PORT
      LAYER met3 ;
        RECT 0.000 3285.800 4.000 3286.400 ;
    END
  END la_oenb[109]
  PIN la_oenb[10]
    DIRECTION INPUT ;
    USE SIGNAL ;
    PORT
      LAYER met3 ;
        RECT 0.000 2612.600 4.000 2613.200 ;
    END
  END la_oenb[10]
  PIN la_oenb[110]
    DIRECTION INPUT ;
    USE SIGNAL ;
    PORT
      LAYER met3 ;
        RECT 0.000 3292.600 4.000 3293.200 ;
    END
  END la_oenb[110]
  PIN la_oenb[111]
    DIRECTION INPUT ;
    USE SIGNAL ;
    PORT
      LAYER met3 ;
        RECT 0.000 3299.400 4.000 3300.000 ;
    END
  END la_oenb[111]
  PIN la_oenb[112]
    DIRECTION INPUT ;
    USE SIGNAL ;
    PORT
      LAYER met3 ;
        RECT 0.000 3306.200 4.000 3306.800 ;
    END
  END la_oenb[112]
  PIN la_oenb[113]
    DIRECTION INPUT ;
    USE SIGNAL ;
    PORT
      LAYER met3 ;
        RECT 0.000 3313.000 4.000 3313.600 ;
    END
  END la_oenb[113]
  PIN la_oenb[114]
    DIRECTION INPUT ;
    USE SIGNAL ;
    PORT
      LAYER met3 ;
        RECT 0.000 3319.800 4.000 3320.400 ;
    END
  END la_oenb[114]
  PIN la_oenb[115]
    DIRECTION INPUT ;
    USE SIGNAL ;
    PORT
      LAYER met3 ;
        RECT 0.000 3326.600 4.000 3327.200 ;
    END
  END la_oenb[115]
  PIN la_oenb[116]
    DIRECTION INPUT ;
    USE SIGNAL ;
    PORT
      LAYER met3 ;
        RECT 0.000 3333.400 4.000 3334.000 ;
    END
  END la_oenb[116]
  PIN la_oenb[117]
    DIRECTION INPUT ;
    USE SIGNAL ;
    PORT
      LAYER met3 ;
        RECT 0.000 3340.200 4.000 3340.800 ;
    END
  END la_oenb[117]
  PIN la_oenb[118]
    DIRECTION INPUT ;
    USE SIGNAL ;
    PORT
      LAYER met3 ;
        RECT 0.000 3347.000 4.000 3347.600 ;
    END
  END la_oenb[118]
  PIN la_oenb[119]
    DIRECTION INPUT ;
    USE SIGNAL ;
    PORT
      LAYER met3 ;
        RECT 0.000 3353.800 4.000 3354.400 ;
    END
  END la_oenb[119]
  PIN la_oenb[11]
    DIRECTION INPUT ;
    USE SIGNAL ;
    PORT
      LAYER met3 ;
        RECT 0.000 2619.400 4.000 2620.000 ;
    END
  END la_oenb[11]
  PIN la_oenb[120]
    DIRECTION INPUT ;
    USE SIGNAL ;
    PORT
      LAYER met3 ;
        RECT 0.000 3360.600 4.000 3361.200 ;
    END
  END la_oenb[120]
  PIN la_oenb[121]
    DIRECTION INPUT ;
    USE SIGNAL ;
    PORT
      LAYER met3 ;
        RECT 0.000 3367.400 4.000 3368.000 ;
    END
  END la_oenb[121]
  PIN la_oenb[122]
    DIRECTION INPUT ;
    USE SIGNAL ;
    PORT
      LAYER met3 ;
        RECT 0.000 3374.200 4.000 3374.800 ;
    END
  END la_oenb[122]
  PIN la_oenb[123]
    DIRECTION INPUT ;
    USE SIGNAL ;
    PORT
      LAYER met3 ;
        RECT 0.000 3381.000 4.000 3381.600 ;
    END
  END la_oenb[123]
  PIN la_oenb[124]
    DIRECTION INPUT ;
    USE SIGNAL ;
    PORT
      LAYER met3 ;
        RECT 0.000 3387.800 4.000 3388.400 ;
    END
  END la_oenb[124]
  PIN la_oenb[125]
    DIRECTION INPUT ;
    USE SIGNAL ;
    PORT
      LAYER met3 ;
        RECT 0.000 3394.600 4.000 3395.200 ;
    END
  END la_oenb[125]
  PIN la_oenb[126]
    DIRECTION INPUT ;
    USE SIGNAL ;
    PORT
      LAYER met3 ;
        RECT 0.000 3401.400 4.000 3402.000 ;
    END
  END la_oenb[126]
  PIN la_oenb[127]
    DIRECTION INPUT ;
    USE SIGNAL ;
    PORT
      LAYER met3 ;
        RECT 0.000 3408.200 4.000 3408.800 ;
    END
  END la_oenb[127]
  PIN la_oenb[12]
    DIRECTION INPUT ;
    USE SIGNAL ;
    PORT
      LAYER met3 ;
        RECT 0.000 2626.200 4.000 2626.800 ;
    END
  END la_oenb[12]
  PIN la_oenb[13]
    DIRECTION INPUT ;
    USE SIGNAL ;
    PORT
      LAYER met3 ;
        RECT 0.000 2633.000 4.000 2633.600 ;
    END
  END la_oenb[13]
  PIN la_oenb[14]
    DIRECTION INPUT ;
    USE SIGNAL ;
    PORT
      LAYER met3 ;
        RECT 0.000 2639.800 4.000 2640.400 ;
    END
  END la_oenb[14]
  PIN la_oenb[15]
    DIRECTION INPUT ;
    USE SIGNAL ;
    PORT
      LAYER met3 ;
        RECT 0.000 2646.600 4.000 2647.200 ;
    END
  END la_oenb[15]
  PIN la_oenb[16]
    DIRECTION INPUT ;
    USE SIGNAL ;
    PORT
      LAYER met3 ;
        RECT 0.000 2653.400 4.000 2654.000 ;
    END
  END la_oenb[16]
  PIN la_oenb[17]
    DIRECTION INPUT ;
    USE SIGNAL ;
    PORT
      LAYER met3 ;
        RECT 0.000 2660.200 4.000 2660.800 ;
    END
  END la_oenb[17]
  PIN la_oenb[18]
    DIRECTION INPUT ;
    USE SIGNAL ;
    PORT
      LAYER met3 ;
        RECT 0.000 2667.000 4.000 2667.600 ;
    END
  END la_oenb[18]
  PIN la_oenb[19]
    DIRECTION INPUT ;
    USE SIGNAL ;
    PORT
      LAYER met3 ;
        RECT 0.000 2673.800 4.000 2674.400 ;
    END
  END la_oenb[19]
  PIN la_oenb[1]
    DIRECTION INPUT ;
    USE SIGNAL ;
    PORT
      LAYER met3 ;
        RECT 0.000 2551.400 4.000 2552.000 ;
    END
  END la_oenb[1]
  PIN la_oenb[20]
    DIRECTION INPUT ;
    USE SIGNAL ;
    PORT
      LAYER met3 ;
        RECT 0.000 2680.600 4.000 2681.200 ;
    END
  END la_oenb[20]
  PIN la_oenb[21]
    DIRECTION INPUT ;
    USE SIGNAL ;
    PORT
      LAYER met3 ;
        RECT 0.000 2687.400 4.000 2688.000 ;
    END
  END la_oenb[21]
  PIN la_oenb[22]
    DIRECTION INPUT ;
    USE SIGNAL ;
    PORT
      LAYER met3 ;
        RECT 0.000 2694.200 4.000 2694.800 ;
    END
  END la_oenb[22]
  PIN la_oenb[23]
    DIRECTION INPUT ;
    USE SIGNAL ;
    PORT
      LAYER met3 ;
        RECT 0.000 2701.000 4.000 2701.600 ;
    END
  END la_oenb[23]
  PIN la_oenb[24]
    DIRECTION INPUT ;
    USE SIGNAL ;
    PORT
      LAYER met3 ;
        RECT 0.000 2707.800 4.000 2708.400 ;
    END
  END la_oenb[24]
  PIN la_oenb[25]
    DIRECTION INPUT ;
    USE SIGNAL ;
    PORT
      LAYER met3 ;
        RECT 0.000 2714.600 4.000 2715.200 ;
    END
  END la_oenb[25]
  PIN la_oenb[26]
    DIRECTION INPUT ;
    USE SIGNAL ;
    PORT
      LAYER met3 ;
        RECT 0.000 2721.400 4.000 2722.000 ;
    END
  END la_oenb[26]
  PIN la_oenb[27]
    DIRECTION INPUT ;
    USE SIGNAL ;
    PORT
      LAYER met3 ;
        RECT 0.000 2728.200 4.000 2728.800 ;
    END
  END la_oenb[27]
  PIN la_oenb[28]
    DIRECTION INPUT ;
    USE SIGNAL ;
    PORT
      LAYER met3 ;
        RECT 0.000 2735.000 4.000 2735.600 ;
    END
  END la_oenb[28]
  PIN la_oenb[29]
    DIRECTION INPUT ;
    USE SIGNAL ;
    PORT
      LAYER met3 ;
        RECT 0.000 2741.800 4.000 2742.400 ;
    END
  END la_oenb[29]
  PIN la_oenb[2]
    DIRECTION INPUT ;
    USE SIGNAL ;
    PORT
      LAYER met3 ;
        RECT 0.000 2558.200 4.000 2558.800 ;
    END
  END la_oenb[2]
  PIN la_oenb[30]
    DIRECTION INPUT ;
    USE SIGNAL ;
    PORT
      LAYER met3 ;
        RECT 0.000 2748.600 4.000 2749.200 ;
    END
  END la_oenb[30]
  PIN la_oenb[31]
    DIRECTION INPUT ;
    USE SIGNAL ;
    PORT
      LAYER met3 ;
        RECT 0.000 2755.400 4.000 2756.000 ;
    END
  END la_oenb[31]
  PIN la_oenb[32]
    DIRECTION INPUT ;
    USE SIGNAL ;
    PORT
      LAYER met3 ;
        RECT 0.000 2762.200 4.000 2762.800 ;
    END
  END la_oenb[32]
  PIN la_oenb[33]
    DIRECTION INPUT ;
    USE SIGNAL ;
    PORT
      LAYER met3 ;
        RECT 0.000 2769.000 4.000 2769.600 ;
    END
  END la_oenb[33]
  PIN la_oenb[34]
    DIRECTION INPUT ;
    USE SIGNAL ;
    PORT
      LAYER met3 ;
        RECT 0.000 2775.800 4.000 2776.400 ;
    END
  END la_oenb[34]
  PIN la_oenb[35]
    DIRECTION INPUT ;
    USE SIGNAL ;
    PORT
      LAYER met3 ;
        RECT 0.000 2782.600 4.000 2783.200 ;
    END
  END la_oenb[35]
  PIN la_oenb[36]
    DIRECTION INPUT ;
    USE SIGNAL ;
    PORT
      LAYER met3 ;
        RECT 0.000 2789.400 4.000 2790.000 ;
    END
  END la_oenb[36]
  PIN la_oenb[37]
    DIRECTION INPUT ;
    USE SIGNAL ;
    PORT
      LAYER met3 ;
        RECT 0.000 2796.200 4.000 2796.800 ;
    END
  END la_oenb[37]
  PIN la_oenb[38]
    DIRECTION INPUT ;
    USE SIGNAL ;
    PORT
      LAYER met3 ;
        RECT 0.000 2803.000 4.000 2803.600 ;
    END
  END la_oenb[38]
  PIN la_oenb[39]
    DIRECTION INPUT ;
    USE SIGNAL ;
    PORT
      LAYER met3 ;
        RECT 0.000 2809.800 4.000 2810.400 ;
    END
  END la_oenb[39]
  PIN la_oenb[3]
    DIRECTION INPUT ;
    USE SIGNAL ;
    PORT
      LAYER met3 ;
        RECT 0.000 2565.000 4.000 2565.600 ;
    END
  END la_oenb[3]
  PIN la_oenb[40]
    DIRECTION INPUT ;
    USE SIGNAL ;
    PORT
      LAYER met3 ;
        RECT 0.000 2816.600 4.000 2817.200 ;
    END
  END la_oenb[40]
  PIN la_oenb[41]
    DIRECTION INPUT ;
    USE SIGNAL ;
    PORT
      LAYER met3 ;
        RECT 0.000 2823.400 4.000 2824.000 ;
    END
  END la_oenb[41]
  PIN la_oenb[42]
    DIRECTION INPUT ;
    USE SIGNAL ;
    PORT
      LAYER met3 ;
        RECT 0.000 2830.200 4.000 2830.800 ;
    END
  END la_oenb[42]
  PIN la_oenb[43]
    DIRECTION INPUT ;
    USE SIGNAL ;
    PORT
      LAYER met3 ;
        RECT 0.000 2837.000 4.000 2837.600 ;
    END
  END la_oenb[43]
  PIN la_oenb[44]
    DIRECTION INPUT ;
    USE SIGNAL ;
    PORT
      LAYER met3 ;
        RECT 0.000 2843.800 4.000 2844.400 ;
    END
  END la_oenb[44]
  PIN la_oenb[45]
    DIRECTION INPUT ;
    USE SIGNAL ;
    PORT
      LAYER met3 ;
        RECT 0.000 2850.600 4.000 2851.200 ;
    END
  END la_oenb[45]
  PIN la_oenb[46]
    DIRECTION INPUT ;
    USE SIGNAL ;
    PORT
      LAYER met3 ;
        RECT 0.000 2857.400 4.000 2858.000 ;
    END
  END la_oenb[46]
  PIN la_oenb[47]
    DIRECTION INPUT ;
    USE SIGNAL ;
    PORT
      LAYER met3 ;
        RECT 0.000 2864.200 4.000 2864.800 ;
    END
  END la_oenb[47]
  PIN la_oenb[48]
    DIRECTION INPUT ;
    USE SIGNAL ;
    PORT
      LAYER met3 ;
        RECT 0.000 2871.000 4.000 2871.600 ;
    END
  END la_oenb[48]
  PIN la_oenb[49]
    DIRECTION INPUT ;
    USE SIGNAL ;
    PORT
      LAYER met3 ;
        RECT 0.000 2877.800 4.000 2878.400 ;
    END
  END la_oenb[49]
  PIN la_oenb[4]
    DIRECTION INPUT ;
    USE SIGNAL ;
    PORT
      LAYER met3 ;
        RECT 0.000 2571.800 4.000 2572.400 ;
    END
  END la_oenb[4]
  PIN la_oenb[50]
    DIRECTION INPUT ;
    USE SIGNAL ;
    PORT
      LAYER met3 ;
        RECT 0.000 2884.600 4.000 2885.200 ;
    END
  END la_oenb[50]
  PIN la_oenb[51]
    DIRECTION INPUT ;
    USE SIGNAL ;
    PORT
      LAYER met3 ;
        RECT 0.000 2891.400 4.000 2892.000 ;
    END
  END la_oenb[51]
  PIN la_oenb[52]
    DIRECTION INPUT ;
    USE SIGNAL ;
    PORT
      LAYER met3 ;
        RECT 0.000 2898.200 4.000 2898.800 ;
    END
  END la_oenb[52]
  PIN la_oenb[53]
    DIRECTION INPUT ;
    USE SIGNAL ;
    PORT
      LAYER met3 ;
        RECT 0.000 2905.000 4.000 2905.600 ;
    END
  END la_oenb[53]
  PIN la_oenb[54]
    DIRECTION INPUT ;
    USE SIGNAL ;
    PORT
      LAYER met3 ;
        RECT 0.000 2911.800 4.000 2912.400 ;
    END
  END la_oenb[54]
  PIN la_oenb[55]
    DIRECTION INPUT ;
    USE SIGNAL ;
    PORT
      LAYER met3 ;
        RECT 0.000 2918.600 4.000 2919.200 ;
    END
  END la_oenb[55]
  PIN la_oenb[56]
    DIRECTION INPUT ;
    USE SIGNAL ;
    PORT
      LAYER met3 ;
        RECT 0.000 2925.400 4.000 2926.000 ;
    END
  END la_oenb[56]
  PIN la_oenb[57]
    DIRECTION INPUT ;
    USE SIGNAL ;
    PORT
      LAYER met3 ;
        RECT 0.000 2932.200 4.000 2932.800 ;
    END
  END la_oenb[57]
  PIN la_oenb[58]
    DIRECTION INPUT ;
    USE SIGNAL ;
    PORT
      LAYER met3 ;
        RECT 0.000 2939.000 4.000 2939.600 ;
    END
  END la_oenb[58]
  PIN la_oenb[59]
    DIRECTION INPUT ;
    USE SIGNAL ;
    PORT
      LAYER met3 ;
        RECT 0.000 2945.800 4.000 2946.400 ;
    END
  END la_oenb[59]
  PIN la_oenb[5]
    DIRECTION INPUT ;
    USE SIGNAL ;
    PORT
      LAYER met3 ;
        RECT 0.000 2578.600 4.000 2579.200 ;
    END
  END la_oenb[5]
  PIN la_oenb[60]
    DIRECTION INPUT ;
    USE SIGNAL ;
    PORT
      LAYER met3 ;
        RECT 0.000 2952.600 4.000 2953.200 ;
    END
  END la_oenb[60]
  PIN la_oenb[61]
    DIRECTION INPUT ;
    USE SIGNAL ;
    PORT
      LAYER met3 ;
        RECT 0.000 2959.400 4.000 2960.000 ;
    END
  END la_oenb[61]
  PIN la_oenb[62]
    DIRECTION INPUT ;
    USE SIGNAL ;
    PORT
      LAYER met3 ;
        RECT 0.000 2966.200 4.000 2966.800 ;
    END
  END la_oenb[62]
  PIN la_oenb[63]
    DIRECTION INPUT ;
    USE SIGNAL ;
    PORT
      LAYER met3 ;
        RECT 0.000 2973.000 4.000 2973.600 ;
    END
  END la_oenb[63]
  PIN la_oenb[64]
    DIRECTION INPUT ;
    USE SIGNAL ;
    PORT
      LAYER met3 ;
        RECT 0.000 2979.800 4.000 2980.400 ;
    END
  END la_oenb[64]
  PIN la_oenb[65]
    DIRECTION INPUT ;
    USE SIGNAL ;
    PORT
      LAYER met3 ;
        RECT 0.000 2986.600 4.000 2987.200 ;
    END
  END la_oenb[65]
  PIN la_oenb[66]
    DIRECTION INPUT ;
    USE SIGNAL ;
    PORT
      LAYER met3 ;
        RECT 0.000 2993.400 4.000 2994.000 ;
    END
  END la_oenb[66]
  PIN la_oenb[67]
    DIRECTION INPUT ;
    USE SIGNAL ;
    PORT
      LAYER met3 ;
        RECT 0.000 3000.200 4.000 3000.800 ;
    END
  END la_oenb[67]
  PIN la_oenb[68]
    DIRECTION INPUT ;
    USE SIGNAL ;
    PORT
      LAYER met3 ;
        RECT 0.000 3007.000 4.000 3007.600 ;
    END
  END la_oenb[68]
  PIN la_oenb[69]
    DIRECTION INPUT ;
    USE SIGNAL ;
    PORT
      LAYER met3 ;
        RECT 0.000 3013.800 4.000 3014.400 ;
    END
  END la_oenb[69]
  PIN la_oenb[6]
    DIRECTION INPUT ;
    USE SIGNAL ;
    PORT
      LAYER met3 ;
        RECT 0.000 2585.400 4.000 2586.000 ;
    END
  END la_oenb[6]
  PIN la_oenb[70]
    DIRECTION INPUT ;
    USE SIGNAL ;
    PORT
      LAYER met3 ;
        RECT 0.000 3020.600 4.000 3021.200 ;
    END
  END la_oenb[70]
  PIN la_oenb[71]
    DIRECTION INPUT ;
    USE SIGNAL ;
    PORT
      LAYER met3 ;
        RECT 0.000 3027.400 4.000 3028.000 ;
    END
  END la_oenb[71]
  PIN la_oenb[72]
    DIRECTION INPUT ;
    USE SIGNAL ;
    PORT
      LAYER met3 ;
        RECT 0.000 3034.200 4.000 3034.800 ;
    END
  END la_oenb[72]
  PIN la_oenb[73]
    DIRECTION INPUT ;
    USE SIGNAL ;
    PORT
      LAYER met3 ;
        RECT 0.000 3041.000 4.000 3041.600 ;
    END
  END la_oenb[73]
  PIN la_oenb[74]
    DIRECTION INPUT ;
    USE SIGNAL ;
    PORT
      LAYER met3 ;
        RECT 0.000 3047.800 4.000 3048.400 ;
    END
  END la_oenb[74]
  PIN la_oenb[75]
    DIRECTION INPUT ;
    USE SIGNAL ;
    PORT
      LAYER met3 ;
        RECT 0.000 3054.600 4.000 3055.200 ;
    END
  END la_oenb[75]
  PIN la_oenb[76]
    DIRECTION INPUT ;
    USE SIGNAL ;
    PORT
      LAYER met3 ;
        RECT 0.000 3061.400 4.000 3062.000 ;
    END
  END la_oenb[76]
  PIN la_oenb[77]
    DIRECTION INPUT ;
    USE SIGNAL ;
    PORT
      LAYER met3 ;
        RECT 0.000 3068.200 4.000 3068.800 ;
    END
  END la_oenb[77]
  PIN la_oenb[78]
    DIRECTION INPUT ;
    USE SIGNAL ;
    PORT
      LAYER met3 ;
        RECT 0.000 3075.000 4.000 3075.600 ;
    END
  END la_oenb[78]
  PIN la_oenb[79]
    DIRECTION INPUT ;
    USE SIGNAL ;
    PORT
      LAYER met3 ;
        RECT 0.000 3081.800 4.000 3082.400 ;
    END
  END la_oenb[79]
  PIN la_oenb[7]
    DIRECTION INPUT ;
    USE SIGNAL ;
    PORT
      LAYER met3 ;
        RECT 0.000 2592.200 4.000 2592.800 ;
    END
  END la_oenb[7]
  PIN la_oenb[80]
    DIRECTION INPUT ;
    USE SIGNAL ;
    PORT
      LAYER met3 ;
        RECT 0.000 3088.600 4.000 3089.200 ;
    END
  END la_oenb[80]
  PIN la_oenb[81]
    DIRECTION INPUT ;
    USE SIGNAL ;
    PORT
      LAYER met3 ;
        RECT 0.000 3095.400 4.000 3096.000 ;
    END
  END la_oenb[81]
  PIN la_oenb[82]
    DIRECTION INPUT ;
    USE SIGNAL ;
    PORT
      LAYER met3 ;
        RECT 0.000 3102.200 4.000 3102.800 ;
    END
  END la_oenb[82]
  PIN la_oenb[83]
    DIRECTION INPUT ;
    USE SIGNAL ;
    PORT
      LAYER met3 ;
        RECT 0.000 3109.000 4.000 3109.600 ;
    END
  END la_oenb[83]
  PIN la_oenb[84]
    DIRECTION INPUT ;
    USE SIGNAL ;
    PORT
      LAYER met3 ;
        RECT 0.000 3115.800 4.000 3116.400 ;
    END
  END la_oenb[84]
  PIN la_oenb[85]
    DIRECTION INPUT ;
    USE SIGNAL ;
    PORT
      LAYER met3 ;
        RECT 0.000 3122.600 4.000 3123.200 ;
    END
  END la_oenb[85]
  PIN la_oenb[86]
    DIRECTION INPUT ;
    USE SIGNAL ;
    PORT
      LAYER met3 ;
        RECT 0.000 3129.400 4.000 3130.000 ;
    END
  END la_oenb[86]
  PIN la_oenb[87]
    DIRECTION INPUT ;
    USE SIGNAL ;
    PORT
      LAYER met3 ;
        RECT 0.000 3136.200 4.000 3136.800 ;
    END
  END la_oenb[87]
  PIN la_oenb[88]
    DIRECTION INPUT ;
    USE SIGNAL ;
    PORT
      LAYER met3 ;
        RECT 0.000 3143.000 4.000 3143.600 ;
    END
  END la_oenb[88]
  PIN la_oenb[89]
    DIRECTION INPUT ;
    USE SIGNAL ;
    PORT
      LAYER met3 ;
        RECT 0.000 3149.800 4.000 3150.400 ;
    END
  END la_oenb[89]
  PIN la_oenb[8]
    DIRECTION INPUT ;
    USE SIGNAL ;
    PORT
      LAYER met3 ;
        RECT 0.000 2599.000 4.000 2599.600 ;
    END
  END la_oenb[8]
  PIN la_oenb[90]
    DIRECTION INPUT ;
    USE SIGNAL ;
    PORT
      LAYER met3 ;
        RECT 0.000 3156.600 4.000 3157.200 ;
    END
  END la_oenb[90]
  PIN la_oenb[91]
    DIRECTION INPUT ;
    USE SIGNAL ;
    PORT
      LAYER met3 ;
        RECT 0.000 3163.400 4.000 3164.000 ;
    END
  END la_oenb[91]
  PIN la_oenb[92]
    DIRECTION INPUT ;
    USE SIGNAL ;
    PORT
      LAYER met3 ;
        RECT 0.000 3170.200 4.000 3170.800 ;
    END
  END la_oenb[92]
  PIN la_oenb[93]
    DIRECTION INPUT ;
    USE SIGNAL ;
    PORT
      LAYER met3 ;
        RECT 0.000 3177.000 4.000 3177.600 ;
    END
  END la_oenb[93]
  PIN la_oenb[94]
    DIRECTION INPUT ;
    USE SIGNAL ;
    PORT
      LAYER met3 ;
        RECT 0.000 3183.800 4.000 3184.400 ;
    END
  END la_oenb[94]
  PIN la_oenb[95]
    DIRECTION INPUT ;
    USE SIGNAL ;
    PORT
      LAYER met3 ;
        RECT 0.000 3190.600 4.000 3191.200 ;
    END
  END la_oenb[95]
  PIN la_oenb[96]
    DIRECTION INPUT ;
    USE SIGNAL ;
    PORT
      LAYER met3 ;
        RECT 0.000 3197.400 4.000 3198.000 ;
    END
  END la_oenb[96]
  PIN la_oenb[97]
    DIRECTION INPUT ;
    USE SIGNAL ;
    PORT
      LAYER met3 ;
        RECT 0.000 3204.200 4.000 3204.800 ;
    END
  END la_oenb[97]
  PIN la_oenb[98]
    DIRECTION INPUT ;
    USE SIGNAL ;
    PORT
      LAYER met3 ;
        RECT 0.000 3211.000 4.000 3211.600 ;
    END
  END la_oenb[98]
  PIN la_oenb[99]
    DIRECTION INPUT ;
    USE SIGNAL ;
    PORT
      LAYER met3 ;
        RECT 0.000 3217.800 4.000 3218.400 ;
    END
  END la_oenb[99]
  PIN la_oenb[9]
    DIRECTION INPUT ;
    USE SIGNAL ;
    PORT
      LAYER met3 ;
        RECT 0.000 2605.800 4.000 2606.400 ;
    END
  END la_oenb[9]
  PIN user_clock2
    DIRECTION INPUT ;
    USE SIGNAL ;
    PORT
      LAYER met2 ;
        RECT 2876.930 0.000 2877.210 4.000 ;
    END
  END user_clock2
  PIN user_irq[0]
    DIRECTION OUTPUT ;
    USE SIGNAL ;
    PORT
      LAYER met2 ;
        RECT 2658.890 0.000 2659.170 4.000 ;
    END
  END user_irq[0]
  PIN user_irq[1]
    DIRECTION OUTPUT ;
    USE SIGNAL ;
    PORT
      LAYER met2 ;
        RECT 2731.570 0.000 2731.850 4.000 ;
    END
  END user_irq[1]
  PIN user_irq[2]
    DIRECTION OUTPUT ;
    USE SIGNAL ;
    PORT
      LAYER met2 ;
        RECT 2804.250 0.000 2804.530 4.000 ;
    END
  END user_irq[2]
  PIN vccd1
    DIRECTION INOUT ;
    USE POWER ;
    PORT
      LAYER met4 ;
        RECT 8.970 10.880 12.070 3508.800 ;
    END
    PORT
      LAYER met4 ;
        RECT 188.970 10.880 192.070 3508.800 ;
    END
    PORT
      LAYER met4 ;
        RECT 368.970 10.880 372.070 3508.800 ;
    END
    PORT
      LAYER met4 ;
        RECT 548.970 10.880 552.070 3508.800 ;
    END
    PORT
      LAYER met4 ;
        RECT 728.970 10.880 732.070 3508.800 ;
    END
    PORT
      LAYER met4 ;
        RECT 908.970 10.880 912.070 3508.800 ;
    END
    PORT
      LAYER met4 ;
        RECT 1088.970 10.880 1092.070 3508.800 ;
    END
    PORT
      LAYER met4 ;
        RECT 1268.970 10.880 1272.070 1302.015 ;
    END
    PORT
      LAYER met4 ;
        RECT 1268.970 1807.305 1272.070 3508.800 ;
    END
    PORT
      LAYER met4 ;
        RECT 1448.970 10.880 1452.070 1302.015 ;
    END
    PORT
      LAYER met4 ;
        RECT 1448.970 1807.305 1452.070 3508.800 ;
    END
    PORT
      LAYER met4 ;
        RECT 1628.970 10.880 1632.070 3508.800 ;
    END
    PORT
      LAYER met4 ;
        RECT 1808.970 10.880 1812.070 3508.800 ;
    END
    PORT
      LAYER met4 ;
        RECT 1988.970 10.880 1992.070 3508.800 ;
    END
    PORT
      LAYER met4 ;
        RECT 2168.970 10.880 2172.070 3508.800 ;
    END
    PORT
      LAYER met4 ;
        RECT 2348.970 10.880 2352.070 3508.800 ;
    END
    PORT
      LAYER met4 ;
        RECT 2528.970 10.880 2532.070 3508.800 ;
    END
    PORT
      LAYER met4 ;
        RECT 2708.970 10.880 2712.070 3508.800 ;
    END
    PORT
      LAYER met4 ;
        RECT 2888.970 10.880 2892.070 3508.800 ;
    END
    PORT
      LAYER met5 ;
        RECT 5.520 14.330 2914.100 17.430 ;
    END
    PORT
      LAYER met5 ;
        RECT 5.520 194.330 2914.100 197.430 ;
    END
    PORT
      LAYER met5 ;
        RECT 5.520 374.330 2914.100 377.430 ;
    END
    PORT
      LAYER met5 ;
        RECT 5.520 554.330 2914.100 557.430 ;
    END
    PORT
      LAYER met5 ;
        RECT 5.520 734.330 2914.100 737.430 ;
    END
    PORT
      LAYER met5 ;
        RECT 5.520 914.330 2914.100 917.430 ;
    END
    PORT
      LAYER met5 ;
        RECT 5.520 1094.330 2914.100 1097.430 ;
    END
    PORT
      LAYER met5 ;
        RECT 5.520 1274.330 2914.100 1277.430 ;
    END
    PORT
      LAYER met5 ;
        RECT 5.520 1454.330 2914.100 1457.430 ;
    END
    PORT
      LAYER met5 ;
        RECT 5.520 1634.330 1092.080 1637.430 ;
    END
    PORT
      LAYER met5 ;
        RECT 5.520 1814.330 2914.100 1817.430 ;
    END
    PORT
      LAYER met5 ;
        RECT 5.520 1994.330 2914.100 1997.430 ;
    END
    PORT
      LAYER met5 ;
        RECT 5.520 2174.330 2914.100 2177.430 ;
    END
    PORT
      LAYER met5 ;
        RECT 5.520 2354.330 2914.100 2357.430 ;
    END
    PORT
      LAYER met5 ;
        RECT 5.520 2534.330 2914.100 2537.430 ;
    END
    PORT
      LAYER met5 ;
        RECT 5.520 2714.330 2914.100 2717.430 ;
    END
    PORT
      LAYER met5 ;
        RECT 5.520 2894.330 2914.100 2897.430 ;
    END
    PORT
      LAYER met5 ;
        RECT 5.520 3074.330 2914.100 3077.430 ;
    END
    PORT
      LAYER met5 ;
        RECT 5.520 3254.330 2914.100 3257.430 ;
    END
    PORT
      LAYER met5 ;
        RECT 5.520 3434.330 2914.100 3437.430 ;
    END
    PORT
      LAYER met5 ;
        RECT 1807.580 1634.330 2914.100 1637.430 ;
    END
  END vccd1
  PIN vccd2
    DIRECTION INOUT ;
    USE SIGNAL ;
    PORT
      LAYER met4 ;
        RECT 18.570 10.880 21.670 3508.800 ;
    END
    PORT
      LAYER met4 ;
        RECT 198.570 10.880 201.670 3508.800 ;
    END
    PORT
      LAYER met4 ;
        RECT 378.570 10.880 381.670 3508.800 ;
    END
    PORT
      LAYER met4 ;
        RECT 558.570 10.880 561.670 3508.800 ;
    END
    PORT
      LAYER met4 ;
        RECT 738.570 10.880 741.670 3508.800 ;
    END
    PORT
      LAYER met4 ;
        RECT 918.570 10.880 921.670 3508.800 ;
    END
    PORT
      LAYER met4 ;
        RECT 1098.570 10.880 1101.670 3508.800 ;
    END
    PORT
      LAYER met4 ;
        RECT 1278.570 10.880 1281.670 1299.940 ;
    END
    PORT
      LAYER met4 ;
        RECT 1278.570 1999.100 1281.670 3508.800 ;
    END
    PORT
      LAYER met4 ;
        RECT 1458.570 10.880 1461.670 1302.015 ;
    END
    PORT
      LAYER met4 ;
        RECT 1458.570 1807.305 1461.670 3508.800 ;
    END
    PORT
      LAYER met4 ;
        RECT 1638.570 10.880 1641.670 3508.800 ;
    END
    PORT
      LAYER met4 ;
        RECT 1818.570 10.880 1821.670 3508.800 ;
    END
    PORT
      LAYER met4 ;
        RECT 1998.570 10.880 2001.670 3508.800 ;
    END
    PORT
      LAYER met4 ;
        RECT 2178.570 10.880 2181.670 3508.800 ;
    END
    PORT
      LAYER met4 ;
        RECT 2358.570 10.880 2361.670 3508.800 ;
    END
    PORT
      LAYER met4 ;
        RECT 2538.570 10.880 2541.670 3508.800 ;
    END
    PORT
      LAYER met4 ;
        RECT 2718.570 10.880 2721.670 3508.800 ;
    END
    PORT
      LAYER met4 ;
        RECT 2898.570 10.880 2901.670 3508.800 ;
    END
    PORT
      LAYER met5 ;
        RECT 5.520 23.930 2914.100 27.030 ;
    END
    PORT
      LAYER met5 ;
        RECT 5.520 203.930 2914.100 207.030 ;
    END
    PORT
      LAYER met5 ;
        RECT 5.520 383.930 2914.100 387.030 ;
    END
    PORT
      LAYER met5 ;
        RECT 5.520 563.930 2914.100 567.030 ;
    END
    PORT
      LAYER met5 ;
        RECT 5.520 743.930 2914.100 747.030 ;
    END
    PORT
      LAYER met5 ;
        RECT 5.520 923.930 2914.100 927.030 ;
    END
    PORT
      LAYER met5 ;
        RECT 5.520 1103.930 2914.100 1107.030 ;
    END
    PORT
      LAYER met5 ;
        RECT 5.520 1283.930 2914.100 1287.030 ;
    END
    PORT
      LAYER met5 ;
        RECT 5.520 1463.930 2914.100 1467.030 ;
    END
    PORT
      LAYER met5 ;
        RECT 5.520 1643.930 2914.100 1647.030 ;
    END
    PORT
      LAYER met5 ;
        RECT 5.520 1823.930 2914.100 1827.030 ;
    END
    PORT
      LAYER met5 ;
        RECT 5.520 2003.930 2914.100 2007.030 ;
    END
    PORT
      LAYER met5 ;
        RECT 5.520 2183.930 2914.100 2187.030 ;
    END
    PORT
      LAYER met5 ;
        RECT 5.520 2363.930 2914.100 2367.030 ;
    END
    PORT
      LAYER met5 ;
        RECT 5.520 2543.930 2914.100 2547.030 ;
    END
    PORT
      LAYER met5 ;
        RECT 5.520 2723.930 2914.100 2727.030 ;
    END
    PORT
      LAYER met5 ;
        RECT 5.520 2903.930 2914.100 2907.030 ;
    END
    PORT
      LAYER met5 ;
        RECT 5.520 3083.930 2914.100 3087.030 ;
    END
    PORT
      LAYER met5 ;
        RECT 5.520 3263.930 2914.100 3267.030 ;
    END
    PORT
      LAYER met5 ;
        RECT 5.520 3443.930 2914.100 3447.030 ;
    END
  END vccd2
  PIN vdda1
    DIRECTION INOUT ;
    USE SIGNAL ;
    PORT
      LAYER met4 ;
        RECT 28.170 10.880 31.270 3508.800 ;
    END
    PORT
      LAYER met4 ;
        RECT 208.170 10.880 211.270 3508.800 ;
    END
    PORT
      LAYER met4 ;
        RECT 388.170 10.880 391.270 3508.800 ;
    END
    PORT
      LAYER met4 ;
        RECT 568.170 10.880 571.270 3508.800 ;
    END
    PORT
      LAYER met4 ;
        RECT 748.170 10.880 751.270 3508.800 ;
    END
    PORT
      LAYER met4 ;
        RECT 928.170 10.880 931.270 3508.800 ;
    END
    PORT
      LAYER met4 ;
        RECT 1108.170 10.880 1111.270 3508.800 ;
    END
    PORT
      LAYER met4 ;
        RECT 1288.170 10.880 1291.270 1302.015 ;
    END
    PORT
      LAYER met4 ;
        RECT 1288.170 1807.305 1291.270 3508.800 ;
    END
    PORT
      LAYER met4 ;
        RECT 1468.170 10.880 1471.270 1302.015 ;
    END
    PORT
      LAYER met4 ;
        RECT 1468.170 1807.305 1471.270 3508.800 ;
    END
    PORT
      LAYER met4 ;
        RECT 1648.170 10.880 1651.270 3508.800 ;
    END
    PORT
      LAYER met4 ;
        RECT 1828.170 10.880 1831.270 3508.800 ;
    END
    PORT
      LAYER met4 ;
        RECT 2008.170 10.880 2011.270 3508.800 ;
    END
    PORT
      LAYER met4 ;
        RECT 2188.170 10.880 2191.270 3508.800 ;
    END
    PORT
      LAYER met4 ;
        RECT 2368.170 10.880 2371.270 3508.800 ;
    END
    PORT
      LAYER met4 ;
        RECT 2548.170 10.880 2551.270 3508.800 ;
    END
    PORT
      LAYER met4 ;
        RECT 2728.170 10.880 2731.270 3508.800 ;
    END
    PORT
      LAYER met4 ;
        RECT 2908.170 10.880 2911.270 3508.800 ;
    END
    PORT
      LAYER met5 ;
        RECT 5.520 33.530 2914.100 36.630 ;
    END
    PORT
      LAYER met5 ;
        RECT 5.520 213.530 2914.100 216.630 ;
    END
    PORT
      LAYER met5 ;
        RECT 5.520 393.530 2914.100 396.630 ;
    END
    PORT
      LAYER met5 ;
        RECT 5.520 573.530 2914.100 576.630 ;
    END
    PORT
      LAYER met5 ;
        RECT 5.520 753.530 2914.100 756.630 ;
    END
    PORT
      LAYER met5 ;
        RECT 5.520 933.530 2914.100 936.630 ;
    END
    PORT
      LAYER met5 ;
        RECT 5.520 1113.530 2914.100 1116.630 ;
    END
    PORT
      LAYER met5 ;
        RECT 5.520 1293.530 2914.100 1296.630 ;
    END
    PORT
      LAYER met5 ;
        RECT 5.520 1473.530 2914.100 1476.630 ;
    END
    PORT
      LAYER met5 ;
        RECT 5.520 1653.530 2914.100 1656.630 ;
    END
    PORT
      LAYER met5 ;
        RECT 5.520 1833.530 2914.100 1836.630 ;
    END
    PORT
      LAYER met5 ;
        RECT 5.520 2013.530 2914.100 2016.630 ;
    END
    PORT
      LAYER met5 ;
        RECT 5.520 2193.530 2914.100 2196.630 ;
    END
    PORT
      LAYER met5 ;
        RECT 5.520 2373.530 2914.100 2376.630 ;
    END
    PORT
      LAYER met5 ;
        RECT 5.520 2553.530 2914.100 2556.630 ;
    END
    PORT
      LAYER met5 ;
        RECT 5.520 2733.530 2914.100 2736.630 ;
    END
    PORT
      LAYER met5 ;
        RECT 5.520 2913.530 2914.100 2916.630 ;
    END
    PORT
      LAYER met5 ;
        RECT 5.520 3093.530 2914.100 3096.630 ;
    END
    PORT
      LAYER met5 ;
        RECT 5.520 3273.530 2914.100 3276.630 ;
    END
    PORT
      LAYER met5 ;
        RECT 5.520 3453.530 2914.100 3456.630 ;
    END
  END vdda1
  PIN vdda2
    DIRECTION INOUT ;
    USE SIGNAL ;
    PORT
      LAYER met4 ;
        RECT 37.770 10.880 40.870 3508.800 ;
    END
    PORT
      LAYER met4 ;
        RECT 217.770 10.880 220.870 3508.800 ;
    END
    PORT
      LAYER met4 ;
        RECT 397.770 10.880 400.870 3508.800 ;
    END
    PORT
      LAYER met4 ;
        RECT 577.770 10.880 580.870 3508.800 ;
    END
    PORT
      LAYER met4 ;
        RECT 757.770 10.880 760.870 3508.800 ;
    END
    PORT
      LAYER met4 ;
        RECT 937.770 10.880 940.870 3508.800 ;
    END
    PORT
      LAYER met4 ;
        RECT 1117.770 10.880 1120.870 1299.940 ;
    END
    PORT
      LAYER met4 ;
        RECT 1117.770 1999.100 1120.870 3508.800 ;
    END
    PORT
      LAYER met4 ;
        RECT 1297.770 10.880 1300.870 1302.015 ;
    END
    PORT
      LAYER met4 ;
        RECT 1297.770 1807.305 1300.870 3508.800 ;
    END
    PORT
      LAYER met4 ;
        RECT 1477.770 10.880 1480.870 1302.015 ;
    END
    PORT
      LAYER met4 ;
        RECT 1477.770 1807.305 1480.870 3508.800 ;
    END
    PORT
      LAYER met4 ;
        RECT 1657.770 10.880 1660.870 3508.800 ;
    END
    PORT
      LAYER met4 ;
        RECT 1837.770 10.880 1840.870 3508.800 ;
    END
    PORT
      LAYER met4 ;
        RECT 2017.770 10.880 2020.870 3508.800 ;
    END
    PORT
      LAYER met4 ;
        RECT 2197.770 10.880 2200.870 3508.800 ;
    END
    PORT
      LAYER met4 ;
        RECT 2377.770 10.880 2380.870 3508.800 ;
    END
    PORT
      LAYER met4 ;
        RECT 2557.770 10.880 2560.870 3508.800 ;
    END
    PORT
      LAYER met4 ;
        RECT 2737.770 10.880 2740.870 3508.800 ;
    END
    PORT
      LAYER met5 ;
        RECT 5.520 43.130 2914.100 46.230 ;
    END
    PORT
      LAYER met5 ;
        RECT 5.520 223.130 2914.100 226.230 ;
    END
    PORT
      LAYER met5 ;
        RECT 5.520 403.130 2914.100 406.230 ;
    END
    PORT
      LAYER met5 ;
        RECT 5.520 583.130 2914.100 586.230 ;
    END
    PORT
      LAYER met5 ;
        RECT 5.520 763.130 2914.100 766.230 ;
    END
    PORT
      LAYER met5 ;
        RECT 5.520 943.130 2914.100 946.230 ;
    END
    PORT
      LAYER met5 ;
        RECT 5.520 1123.130 2914.100 1126.230 ;
    END
    PORT
      LAYER met5 ;
        RECT 5.520 1303.130 2914.100 1306.230 ;
    END
    PORT
      LAYER met5 ;
        RECT 5.520 1483.130 1092.080 1486.230 ;
    END
    PORT
      LAYER met5 ;
        RECT 5.520 1663.130 2914.100 1666.230 ;
    END
    PORT
      LAYER met5 ;
        RECT 5.520 1843.130 2914.100 1846.230 ;
    END
    PORT
      LAYER met5 ;
        RECT 5.520 2023.130 2914.100 2026.230 ;
    END
    PORT
      LAYER met5 ;
        RECT 5.520 2203.130 2914.100 2206.230 ;
    END
    PORT
      LAYER met5 ;
        RECT 5.520 2383.130 2914.100 2386.230 ;
    END
    PORT
      LAYER met5 ;
        RECT 5.520 2563.130 2914.100 2566.230 ;
    END
    PORT
      LAYER met5 ;
        RECT 5.520 2743.130 2914.100 2746.230 ;
    END
    PORT
      LAYER met5 ;
        RECT 5.520 2923.130 2914.100 2926.230 ;
    END
    PORT
      LAYER met5 ;
        RECT 5.520 3103.130 2914.100 3106.230 ;
    END
    PORT
      LAYER met5 ;
        RECT 5.520 3283.130 2914.100 3286.230 ;
    END
    PORT
      LAYER met5 ;
        RECT 5.520 3463.130 2914.100 3466.230 ;
    END
    PORT
      LAYER met5 ;
        RECT 1807.580 1483.130 2914.100 1486.230 ;
    END
  END vdda2
  PIN vssa1
    DIRECTION INOUT ;
    USE SIGNAL ;
    PORT
      LAYER met4 ;
        RECT 32.970 10.880 36.070 3508.800 ;
    END
    PORT
      LAYER met4 ;
        RECT 212.970 10.880 216.070 3508.800 ;
    END
    PORT
      LAYER met4 ;
        RECT 392.970 10.880 396.070 3508.800 ;
    END
    PORT
      LAYER met4 ;
        RECT 572.970 10.880 576.070 3508.800 ;
    END
    PORT
      LAYER met4 ;
        RECT 752.970 10.880 756.070 3508.800 ;
    END
    PORT
      LAYER met4 ;
        RECT 932.970 10.880 936.070 3508.800 ;
    END
    PORT
      LAYER met4 ;
        RECT 1112.970 10.880 1116.070 3508.800 ;
    END
    PORT
      LAYER met4 ;
        RECT 1292.970 10.880 1296.070 1302.015 ;
    END
    PORT
      LAYER met4 ;
        RECT 1292.970 1807.305 1296.070 3508.800 ;
    END
    PORT
      LAYER met4 ;
        RECT 1472.970 10.880 1476.070 1302.015 ;
    END
    PORT
      LAYER met4 ;
        RECT 1472.970 1807.305 1476.070 3508.800 ;
    END
    PORT
      LAYER met4 ;
        RECT 1652.970 10.880 1656.070 3508.800 ;
    END
    PORT
      LAYER met4 ;
        RECT 1832.970 10.880 1836.070 3508.800 ;
    END
    PORT
      LAYER met4 ;
        RECT 2012.970 10.880 2016.070 3508.800 ;
    END
    PORT
      LAYER met4 ;
        RECT 2192.970 10.880 2196.070 3508.800 ;
    END
    PORT
      LAYER met4 ;
        RECT 2372.970 10.880 2376.070 3508.800 ;
    END
    PORT
      LAYER met4 ;
        RECT 2552.970 10.880 2556.070 3508.800 ;
    END
    PORT
      LAYER met4 ;
        RECT 2732.970 10.880 2736.070 3508.800 ;
    END
    PORT
      LAYER met5 ;
        RECT 5.520 38.330 2914.100 41.430 ;
    END
    PORT
      LAYER met5 ;
        RECT 5.520 218.330 2914.100 221.430 ;
    END
    PORT
      LAYER met5 ;
        RECT 5.520 398.330 2914.100 401.430 ;
    END
    PORT
      LAYER met5 ;
        RECT 5.520 578.330 2914.100 581.430 ;
    END
    PORT
      LAYER met5 ;
        RECT 5.520 758.330 2914.100 761.430 ;
    END
    PORT
      LAYER met5 ;
        RECT 5.520 938.330 2914.100 941.430 ;
    END
    PORT
      LAYER met5 ;
        RECT 5.520 1118.330 2914.100 1121.430 ;
    END
    PORT
      LAYER met5 ;
        RECT 5.520 1298.330 2914.100 1301.430 ;
    END
    PORT
      LAYER met5 ;
        RECT 5.520 1478.330 1092.080 1481.430 ;
    END
    PORT
      LAYER met5 ;
        RECT 5.520 1658.330 2914.100 1661.430 ;
    END
    PORT
      LAYER met5 ;
        RECT 5.520 1838.330 2914.100 1841.430 ;
    END
    PORT
      LAYER met5 ;
        RECT 5.520 2018.330 2914.100 2021.430 ;
    END
    PORT
      LAYER met5 ;
        RECT 5.520 2198.330 2914.100 2201.430 ;
    END
    PORT
      LAYER met5 ;
        RECT 5.520 2378.330 2914.100 2381.430 ;
    END
    PORT
      LAYER met5 ;
        RECT 5.520 2558.330 2914.100 2561.430 ;
    END
    PORT
      LAYER met5 ;
        RECT 5.520 2738.330 2914.100 2741.430 ;
    END
    PORT
      LAYER met5 ;
        RECT 5.520 2918.330 2914.100 2921.430 ;
    END
    PORT
      LAYER met5 ;
        RECT 5.520 3098.330 2914.100 3101.430 ;
    END
    PORT
      LAYER met5 ;
        RECT 5.520 3278.330 2914.100 3281.430 ;
    END
    PORT
      LAYER met5 ;
        RECT 5.520 3458.330 2914.100 3461.430 ;
    END
    PORT
      LAYER met5 ;
        RECT 1807.580 1478.330 2914.100 1481.430 ;
    END
  END vssa1
  PIN vssa2
    DIRECTION INOUT ;
    USE SIGNAL ;
    PORT
      LAYER met4 ;
        RECT 42.570 10.880 45.670 3508.800 ;
    END
    PORT
      LAYER met4 ;
        RECT 222.570 10.880 225.670 3508.800 ;
    END
    PORT
      LAYER met4 ;
        RECT 402.570 10.880 405.670 3508.800 ;
    END
    PORT
      LAYER met4 ;
        RECT 582.570 10.880 585.670 3508.800 ;
    END
    PORT
      LAYER met4 ;
        RECT 762.570 10.880 765.670 3508.800 ;
    END
    PORT
      LAYER met4 ;
        RECT 942.570 10.880 945.670 3508.800 ;
    END
    PORT
      LAYER met4 ;
        RECT 1122.570 10.880 1125.670 1299.940 ;
    END
    PORT
      LAYER met4 ;
        RECT 1122.570 1999.100 1125.670 3508.800 ;
    END
    PORT
      LAYER met4 ;
        RECT 1302.570 10.880 1305.670 1302.015 ;
    END
    PORT
      LAYER met4 ;
        RECT 1302.570 1807.305 1305.670 3508.800 ;
    END
    PORT
      LAYER met4 ;
        RECT 1482.570 10.880 1485.670 1302.015 ;
    END
    PORT
      LAYER met4 ;
        RECT 1482.570 1807.305 1485.670 3508.800 ;
    END
    PORT
      LAYER met4 ;
        RECT 1662.570 10.880 1665.670 3508.800 ;
    END
    PORT
      LAYER met4 ;
        RECT 1842.570 10.880 1845.670 3508.800 ;
    END
    PORT
      LAYER met4 ;
        RECT 2022.570 10.880 2025.670 3508.800 ;
    END
    PORT
      LAYER met4 ;
        RECT 2202.570 10.880 2205.670 3508.800 ;
    END
    PORT
      LAYER met4 ;
        RECT 2382.570 10.880 2385.670 3508.800 ;
    END
    PORT
      LAYER met4 ;
        RECT 2562.570 10.880 2565.670 3508.800 ;
    END
    PORT
      LAYER met4 ;
        RECT 2742.570 10.880 2745.670 3508.800 ;
    END
    PORT
      LAYER met5 ;
        RECT 5.520 47.930 2914.100 51.030 ;
    END
    PORT
      LAYER met5 ;
        RECT 5.520 227.930 2914.100 231.030 ;
    END
    PORT
      LAYER met5 ;
        RECT 5.520 407.930 2914.100 411.030 ;
    END
    PORT
      LAYER met5 ;
        RECT 5.520 587.930 2914.100 591.030 ;
    END
    PORT
      LAYER met5 ;
        RECT 5.520 767.930 2914.100 771.030 ;
    END
    PORT
      LAYER met5 ;
        RECT 5.520 947.930 2914.100 951.030 ;
    END
    PORT
      LAYER met5 ;
        RECT 5.520 1127.930 2914.100 1131.030 ;
    END
    PORT
      LAYER met5 ;
        RECT 5.520 1307.930 2914.100 1311.030 ;
    END
    PORT
      LAYER met5 ;
        RECT 5.520 1487.930 1092.080 1491.030 ;
    END
    PORT
      LAYER met5 ;
        RECT 5.520 1667.930 2914.100 1671.030 ;
    END
    PORT
      LAYER met5 ;
        RECT 5.520 1847.930 2914.100 1851.030 ;
    END
    PORT
      LAYER met5 ;
        RECT 5.520 2027.930 2914.100 2031.030 ;
    END
    PORT
      LAYER met5 ;
        RECT 5.520 2207.930 2914.100 2211.030 ;
    END
    PORT
      LAYER met5 ;
        RECT 5.520 2387.930 2914.100 2391.030 ;
    END
    PORT
      LAYER met5 ;
        RECT 5.520 2567.930 2914.100 2571.030 ;
    END
    PORT
      LAYER met5 ;
        RECT 5.520 2747.930 2914.100 2751.030 ;
    END
    PORT
      LAYER met5 ;
        RECT 5.520 2927.930 2914.100 2931.030 ;
    END
    PORT
      LAYER met5 ;
        RECT 5.520 3107.930 2914.100 3111.030 ;
    END
    PORT
      LAYER met5 ;
        RECT 5.520 3287.930 2914.100 3291.030 ;
    END
    PORT
      LAYER met5 ;
        RECT 5.520 3467.930 2914.100 3471.030 ;
    END
    PORT
      LAYER met5 ;
        RECT 1807.580 1487.930 2914.100 1491.030 ;
    END
  END vssa2
  PIN vssd1
    DIRECTION INOUT ;
    USE GROUND ;
    PORT
      LAYER met4 ;
        RECT 13.770 10.880 16.870 3508.800 ;
    END
    PORT
      LAYER met4 ;
        RECT 193.770 10.880 196.870 3508.800 ;
    END
    PORT
      LAYER met4 ;
        RECT 373.770 10.880 376.870 3508.800 ;
    END
    PORT
      LAYER met4 ;
        RECT 553.770 10.880 556.870 3508.800 ;
    END
    PORT
      LAYER met4 ;
        RECT 733.770 10.880 736.870 3508.800 ;
    END
    PORT
      LAYER met4 ;
        RECT 913.770 10.880 916.870 3508.800 ;
    END
    PORT
      LAYER met4 ;
        RECT 1093.770 10.880 1096.870 3508.800 ;
    END
    PORT
      LAYER met4 ;
        RECT 1273.770 10.880 1276.870 1299.940 ;
    END
    PORT
      LAYER met4 ;
        RECT 1273.770 1999.100 1276.870 3508.800 ;
    END
    PORT
      LAYER met4 ;
        RECT 1453.770 10.880 1456.870 1302.015 ;
    END
    PORT
      LAYER met4 ;
        RECT 1453.770 1807.305 1456.870 3508.800 ;
    END
    PORT
      LAYER met4 ;
        RECT 1633.770 10.880 1636.870 3508.800 ;
    END
    PORT
      LAYER met4 ;
        RECT 1813.770 10.880 1816.870 3508.800 ;
    END
    PORT
      LAYER met4 ;
        RECT 1993.770 10.880 1996.870 3508.800 ;
    END
    PORT
      LAYER met4 ;
        RECT 2173.770 10.880 2176.870 3508.800 ;
    END
    PORT
      LAYER met4 ;
        RECT 2353.770 10.880 2356.870 3508.800 ;
    END
    PORT
      LAYER met4 ;
        RECT 2533.770 10.880 2536.870 3508.800 ;
    END
    PORT
      LAYER met4 ;
        RECT 2713.770 10.880 2716.870 3508.800 ;
    END
    PORT
      LAYER met4 ;
        RECT 2893.770 10.880 2896.870 3508.800 ;
    END
    PORT
      LAYER met5 ;
        RECT 5.520 19.130 2914.100 22.230 ;
    END
    PORT
      LAYER met5 ;
        RECT 5.520 199.130 2914.100 202.230 ;
    END
    PORT
      LAYER met5 ;
        RECT 5.520 379.130 2914.100 382.230 ;
    END
    PORT
      LAYER met5 ;
        RECT 5.520 559.130 2914.100 562.230 ;
    END
    PORT
      LAYER met5 ;
        RECT 5.520 739.130 2914.100 742.230 ;
    END
    PORT
      LAYER met5 ;
        RECT 5.520 919.130 2914.100 922.230 ;
    END
    PORT
      LAYER met5 ;
        RECT 5.520 1099.130 2914.100 1102.230 ;
    END
    PORT
      LAYER met5 ;
        RECT 5.520 1279.130 2914.100 1282.230 ;
    END
    PORT
      LAYER met5 ;
        RECT 5.520 1459.130 2914.100 1462.230 ;
    END
    PORT
      LAYER met5 ;
        RECT 5.520 1639.130 1092.080 1642.230 ;
    END
    PORT
      LAYER met5 ;
        RECT 5.520 1819.130 2914.100 1822.230 ;
    END
    PORT
      LAYER met5 ;
        RECT 5.520 1999.130 2914.100 2002.230 ;
    END
    PORT
      LAYER met5 ;
        RECT 5.520 2179.130 2914.100 2182.230 ;
    END
    PORT
      LAYER met5 ;
        RECT 5.520 2359.130 2914.100 2362.230 ;
    END
    PORT
      LAYER met5 ;
        RECT 5.520 2539.130 2914.100 2542.230 ;
    END
    PORT
      LAYER met5 ;
        RECT 5.520 2719.130 2914.100 2722.230 ;
    END
    PORT
      LAYER met5 ;
        RECT 5.520 2899.130 2914.100 2902.230 ;
    END
    PORT
      LAYER met5 ;
        RECT 5.520 3079.130 2914.100 3082.230 ;
    END
    PORT
      LAYER met5 ;
        RECT 5.520 3259.130 2914.100 3262.230 ;
    END
    PORT
      LAYER met5 ;
        RECT 5.520 3439.130 2914.100 3442.230 ;
    END
    PORT
      LAYER met5 ;
        RECT 1807.580 1639.130 2914.100 1642.230 ;
    END
  END vssd1
  PIN vssd2
    DIRECTION INOUT ;
    USE SIGNAL ;
    PORT
      LAYER met4 ;
        RECT 23.370 10.880 26.470 3508.800 ;
    END
    PORT
      LAYER met4 ;
        RECT 203.370 10.880 206.470 3508.800 ;
    END
    PORT
      LAYER met4 ;
        RECT 383.370 10.880 386.470 3508.800 ;
    END
    PORT
      LAYER met4 ;
        RECT 563.370 10.880 566.470 3508.800 ;
    END
    PORT
      LAYER met4 ;
        RECT 743.370 10.880 746.470 3508.800 ;
    END
    PORT
      LAYER met4 ;
        RECT 923.370 10.880 926.470 3508.800 ;
    END
    PORT
      LAYER met4 ;
        RECT 1103.370 10.880 1106.470 3508.800 ;
    END
    PORT
      LAYER met4 ;
        RECT 1283.370 10.880 1286.470 1302.015 ;
    END
    PORT
      LAYER met4 ;
        RECT 1283.370 1807.305 1286.470 3508.800 ;
    END
    PORT
      LAYER met4 ;
        RECT 1463.370 10.880 1466.470 1302.015 ;
    END
    PORT
      LAYER met4 ;
        RECT 1463.370 1807.305 1466.470 3508.800 ;
    END
    PORT
      LAYER met4 ;
        RECT 1643.370 10.880 1646.470 3508.800 ;
    END
    PORT
      LAYER met4 ;
        RECT 1823.370 10.880 1826.470 3508.800 ;
    END
    PORT
      LAYER met4 ;
        RECT 2003.370 10.880 2006.470 3508.800 ;
    END
    PORT
      LAYER met4 ;
        RECT 2183.370 10.880 2186.470 3508.800 ;
    END
    PORT
      LAYER met4 ;
        RECT 2363.370 10.880 2366.470 3508.800 ;
    END
    PORT
      LAYER met4 ;
        RECT 2543.370 10.880 2546.470 3508.800 ;
    END
    PORT
      LAYER met4 ;
        RECT 2723.370 10.880 2726.470 3508.800 ;
    END
    PORT
      LAYER met4 ;
        RECT 2903.370 10.880 2906.470 3508.800 ;
    END
    PORT
      LAYER met5 ;
        RECT 5.520 28.730 2914.100 31.830 ;
    END
    PORT
      LAYER met5 ;
        RECT 5.520 208.730 2914.100 211.830 ;
    END
    PORT
      LAYER met5 ;
        RECT 5.520 388.730 2914.100 391.830 ;
    END
    PORT
      LAYER met5 ;
        RECT 5.520 568.730 2914.100 571.830 ;
    END
    PORT
      LAYER met5 ;
        RECT 5.520 748.730 2914.100 751.830 ;
    END
    PORT
      LAYER met5 ;
        RECT 5.520 928.730 2914.100 931.830 ;
    END
    PORT
      LAYER met5 ;
        RECT 5.520 1108.730 2914.100 1111.830 ;
    END
    PORT
      LAYER met5 ;
        RECT 5.520 1288.730 2914.100 1291.830 ;
    END
    PORT
      LAYER met5 ;
        RECT 5.520 1468.730 2914.100 1471.830 ;
    END
    PORT
      LAYER met5 ;
        RECT 5.520 1648.730 2914.100 1651.830 ;
    END
    PORT
      LAYER met5 ;
        RECT 5.520 1828.730 2914.100 1831.830 ;
    END
    PORT
      LAYER met5 ;
        RECT 5.520 2008.730 2914.100 2011.830 ;
    END
    PORT
      LAYER met5 ;
        RECT 5.520 2188.730 2914.100 2191.830 ;
    END
    PORT
      LAYER met5 ;
        RECT 5.520 2368.730 2914.100 2371.830 ;
    END
    PORT
      LAYER met5 ;
        RECT 5.520 2548.730 2914.100 2551.830 ;
    END
    PORT
      LAYER met5 ;
        RECT 5.520 2728.730 2914.100 2731.830 ;
    END
    PORT
      LAYER met5 ;
        RECT 5.520 2908.730 2914.100 2911.830 ;
    END
    PORT
      LAYER met5 ;
        RECT 5.520 3088.730 2914.100 3091.830 ;
    END
    PORT
      LAYER met5 ;
        RECT 5.520 3268.730 2914.100 3271.830 ;
    END
    PORT
      LAYER met5 ;
        RECT 5.520 3448.730 2914.100 3451.830 ;
    END
  END vssd2
  PIN wb_clk_i
    DIRECTION INPUT ;
    USE SIGNAL ;
    PORT
      LAYER met3 ;
        RECT 0.000 83.000 4.000 83.600 ;
    END
  END wb_clk_i
  PIN wb_rst_i
    DIRECTION INPUT ;
    USE SIGNAL ;
    ANTENNAGATEAREA 0.990000 ;
    PORT
      LAYER met3 ;
        RECT 0.000 89.800 4.000 90.400 ;
    END
  END wb_rst_i
  PIN wbs_ack_o
    DIRECTION OUTPUT ;
    USE SIGNAL ;
    PORT
      LAYER met3 ;
        RECT 0.000 96.600 4.000 97.200 ;
    END
  END wbs_ack_o
  PIN wbs_adr_i[0]
    DIRECTION INPUT ;
    USE SIGNAL ;
    PORT
      LAYER met3 ;
        RECT 0.000 103.400 4.000 104.000 ;
    END
  END wbs_adr_i[0]
  PIN wbs_adr_i[10]
    DIRECTION INPUT ;
    USE SIGNAL ;
    PORT
      LAYER met3 ;
        RECT 0.000 171.400 4.000 172.000 ;
    END
  END wbs_adr_i[10]
  PIN wbs_adr_i[11]
    DIRECTION INPUT ;
    USE SIGNAL ;
    PORT
      LAYER met3 ;
        RECT 0.000 178.200 4.000 178.800 ;
    END
  END wbs_adr_i[11]
  PIN wbs_adr_i[12]
    DIRECTION INPUT ;
    USE SIGNAL ;
    PORT
      LAYER met3 ;
        RECT 0.000 185.000 4.000 185.600 ;
    END
  END wbs_adr_i[12]
  PIN wbs_adr_i[13]
    DIRECTION INPUT ;
    USE SIGNAL ;
    PORT
      LAYER met3 ;
        RECT 0.000 191.800 4.000 192.400 ;
    END
  END wbs_adr_i[13]
  PIN wbs_adr_i[14]
    DIRECTION INPUT ;
    USE SIGNAL ;
    PORT
      LAYER met3 ;
        RECT 0.000 198.600 4.000 199.200 ;
    END
  END wbs_adr_i[14]
  PIN wbs_adr_i[15]
    DIRECTION INPUT ;
    USE SIGNAL ;
    PORT
      LAYER met3 ;
        RECT 0.000 205.400 4.000 206.000 ;
    END
  END wbs_adr_i[15]
  PIN wbs_adr_i[16]
    DIRECTION INPUT ;
    USE SIGNAL ;
    PORT
      LAYER met3 ;
        RECT 0.000 212.200 4.000 212.800 ;
    END
  END wbs_adr_i[16]
  PIN wbs_adr_i[17]
    DIRECTION INPUT ;
    USE SIGNAL ;
    PORT
      LAYER met3 ;
        RECT 0.000 219.000 4.000 219.600 ;
    END
  END wbs_adr_i[17]
  PIN wbs_adr_i[18]
    DIRECTION INPUT ;
    USE SIGNAL ;
    PORT
      LAYER met3 ;
        RECT 0.000 225.800 4.000 226.400 ;
    END
  END wbs_adr_i[18]
  PIN wbs_adr_i[19]
    DIRECTION INPUT ;
    USE SIGNAL ;
    PORT
      LAYER met3 ;
        RECT 0.000 232.600 4.000 233.200 ;
    END
  END wbs_adr_i[19]
  PIN wbs_adr_i[1]
    DIRECTION INPUT ;
    USE SIGNAL ;
    PORT
      LAYER met3 ;
        RECT 0.000 110.200 4.000 110.800 ;
    END
  END wbs_adr_i[1]
  PIN wbs_adr_i[20]
    DIRECTION INPUT ;
    USE SIGNAL ;
    PORT
      LAYER met3 ;
        RECT 0.000 239.400 4.000 240.000 ;
    END
  END wbs_adr_i[20]
  PIN wbs_adr_i[21]
    DIRECTION INPUT ;
    USE SIGNAL ;
    PORT
      LAYER met3 ;
        RECT 0.000 246.200 4.000 246.800 ;
    END
  END wbs_adr_i[21]
  PIN wbs_adr_i[22]
    DIRECTION INPUT ;
    USE SIGNAL ;
    PORT
      LAYER met3 ;
        RECT 0.000 253.000 4.000 253.600 ;
    END
  END wbs_adr_i[22]
  PIN wbs_adr_i[23]
    DIRECTION INPUT ;
    USE SIGNAL ;
    PORT
      LAYER met3 ;
        RECT 0.000 259.800 4.000 260.400 ;
    END
  END wbs_adr_i[23]
  PIN wbs_adr_i[24]
    DIRECTION INPUT ;
    USE SIGNAL ;
    PORT
      LAYER met3 ;
        RECT 0.000 266.600 4.000 267.200 ;
    END
  END wbs_adr_i[24]
  PIN wbs_adr_i[25]
    DIRECTION INPUT ;
    USE SIGNAL ;
    PORT
      LAYER met3 ;
        RECT 0.000 273.400 4.000 274.000 ;
    END
  END wbs_adr_i[25]
  PIN wbs_adr_i[26]
    DIRECTION INPUT ;
    USE SIGNAL ;
    PORT
      LAYER met3 ;
        RECT 0.000 280.200 4.000 280.800 ;
    END
  END wbs_adr_i[26]
  PIN wbs_adr_i[27]
    DIRECTION INPUT ;
    USE SIGNAL ;
    PORT
      LAYER met3 ;
        RECT 0.000 287.000 4.000 287.600 ;
    END
  END wbs_adr_i[27]
  PIN wbs_adr_i[28]
    DIRECTION INPUT ;
    USE SIGNAL ;
    PORT
      LAYER met3 ;
        RECT 0.000 293.800 4.000 294.400 ;
    END
  END wbs_adr_i[28]
  PIN wbs_adr_i[29]
    DIRECTION INPUT ;
    USE SIGNAL ;
    PORT
      LAYER met3 ;
        RECT 0.000 300.600 4.000 301.200 ;
    END
  END wbs_adr_i[29]
  PIN wbs_adr_i[2]
    DIRECTION INPUT ;
    USE SIGNAL ;
    PORT
      LAYER met3 ;
        RECT 0.000 117.000 4.000 117.600 ;
    END
  END wbs_adr_i[2]
  PIN wbs_adr_i[30]
    DIRECTION INPUT ;
    USE SIGNAL ;
    PORT
      LAYER met3 ;
        RECT 0.000 307.400 4.000 308.000 ;
    END
  END wbs_adr_i[30]
  PIN wbs_adr_i[31]
    DIRECTION INPUT ;
    USE SIGNAL ;
    PORT
      LAYER met3 ;
        RECT 0.000 314.200 4.000 314.800 ;
    END
  END wbs_adr_i[31]
  PIN wbs_adr_i[3]
    DIRECTION INPUT ;
    USE SIGNAL ;
    PORT
      LAYER met3 ;
        RECT 0.000 123.800 4.000 124.400 ;
    END
  END wbs_adr_i[3]
  PIN wbs_adr_i[4]
    DIRECTION INPUT ;
    USE SIGNAL ;
    PORT
      LAYER met3 ;
        RECT 0.000 130.600 4.000 131.200 ;
    END
  END wbs_adr_i[4]
  PIN wbs_adr_i[5]
    DIRECTION INPUT ;
    USE SIGNAL ;
    PORT
      LAYER met3 ;
        RECT 0.000 137.400 4.000 138.000 ;
    END
  END wbs_adr_i[5]
  PIN wbs_adr_i[6]
    DIRECTION INPUT ;
    USE SIGNAL ;
    PORT
      LAYER met3 ;
        RECT 0.000 144.200 4.000 144.800 ;
    END
  END wbs_adr_i[6]
  PIN wbs_adr_i[7]
    DIRECTION INPUT ;
    USE SIGNAL ;
    PORT
      LAYER met3 ;
        RECT 0.000 151.000 4.000 151.600 ;
    END
  END wbs_adr_i[7]
  PIN wbs_adr_i[8]
    DIRECTION INPUT ;
    USE SIGNAL ;
    PORT
      LAYER met3 ;
        RECT 0.000 157.800 4.000 158.400 ;
    END
  END wbs_adr_i[8]
  PIN wbs_adr_i[9]
    DIRECTION INPUT ;
    USE SIGNAL ;
    PORT
      LAYER met3 ;
        RECT 0.000 164.600 4.000 165.200 ;
    END
  END wbs_adr_i[9]
  PIN wbs_cyc_i
    DIRECTION INPUT ;
    USE SIGNAL ;
    PORT
      LAYER met3 ;
        RECT 0.000 321.000 4.000 321.600 ;
    END
  END wbs_cyc_i
  PIN wbs_dat_i[0]
    DIRECTION INPUT ;
    USE SIGNAL ;
    PORT
      LAYER met3 ;
        RECT 0.000 327.800 4.000 328.400 ;
    END
  END wbs_dat_i[0]
  PIN wbs_dat_i[10]
    DIRECTION INPUT ;
    USE SIGNAL ;
    PORT
      LAYER met3 ;
        RECT 0.000 395.800 4.000 396.400 ;
    END
  END wbs_dat_i[10]
  PIN wbs_dat_i[11]
    DIRECTION INPUT ;
    USE SIGNAL ;
    PORT
      LAYER met3 ;
        RECT 0.000 402.600 4.000 403.200 ;
    END
  END wbs_dat_i[11]
  PIN wbs_dat_i[12]
    DIRECTION INPUT ;
    USE SIGNAL ;
    PORT
      LAYER met3 ;
        RECT 0.000 409.400 4.000 410.000 ;
    END
  END wbs_dat_i[12]
  PIN wbs_dat_i[13]
    DIRECTION INPUT ;
    USE SIGNAL ;
    PORT
      LAYER met3 ;
        RECT 0.000 416.200 4.000 416.800 ;
    END
  END wbs_dat_i[13]
  PIN wbs_dat_i[14]
    DIRECTION INPUT ;
    USE SIGNAL ;
    PORT
      LAYER met3 ;
        RECT 0.000 423.000 4.000 423.600 ;
    END
  END wbs_dat_i[14]
  PIN wbs_dat_i[15]
    DIRECTION INPUT ;
    USE SIGNAL ;
    PORT
      LAYER met3 ;
        RECT 0.000 429.800 4.000 430.400 ;
    END
  END wbs_dat_i[15]
  PIN wbs_dat_i[16]
    DIRECTION INPUT ;
    USE SIGNAL ;
    PORT
      LAYER met3 ;
        RECT 0.000 436.600 4.000 437.200 ;
    END
  END wbs_dat_i[16]
  PIN wbs_dat_i[17]
    DIRECTION INPUT ;
    USE SIGNAL ;
    PORT
      LAYER met3 ;
        RECT 0.000 443.400 4.000 444.000 ;
    END
  END wbs_dat_i[17]
  PIN wbs_dat_i[18]
    DIRECTION INPUT ;
    USE SIGNAL ;
    PORT
      LAYER met3 ;
        RECT 0.000 450.200 4.000 450.800 ;
    END
  END wbs_dat_i[18]
  PIN wbs_dat_i[19]
    DIRECTION INPUT ;
    USE SIGNAL ;
    PORT
      LAYER met3 ;
        RECT 0.000 457.000 4.000 457.600 ;
    END
  END wbs_dat_i[19]
  PIN wbs_dat_i[1]
    DIRECTION INPUT ;
    USE SIGNAL ;
    PORT
      LAYER met3 ;
        RECT 0.000 334.600 4.000 335.200 ;
    END
  END wbs_dat_i[1]
  PIN wbs_dat_i[20]
    DIRECTION INPUT ;
    USE SIGNAL ;
    PORT
      LAYER met3 ;
        RECT 0.000 463.800 4.000 464.400 ;
    END
  END wbs_dat_i[20]
  PIN wbs_dat_i[21]
    DIRECTION INPUT ;
    USE SIGNAL ;
    PORT
      LAYER met3 ;
        RECT 0.000 470.600 4.000 471.200 ;
    END
  END wbs_dat_i[21]
  PIN wbs_dat_i[22]
    DIRECTION INPUT ;
    USE SIGNAL ;
    PORT
      LAYER met3 ;
        RECT 0.000 477.400 4.000 478.000 ;
    END
  END wbs_dat_i[22]
  PIN wbs_dat_i[23]
    DIRECTION INPUT ;
    USE SIGNAL ;
    PORT
      LAYER met3 ;
        RECT 0.000 484.200 4.000 484.800 ;
    END
  END wbs_dat_i[23]
  PIN wbs_dat_i[24]
    DIRECTION INPUT ;
    USE SIGNAL ;
    PORT
      LAYER met3 ;
        RECT 0.000 491.000 4.000 491.600 ;
    END
  END wbs_dat_i[24]
  PIN wbs_dat_i[25]
    DIRECTION INPUT ;
    USE SIGNAL ;
    PORT
      LAYER met3 ;
        RECT 0.000 497.800 4.000 498.400 ;
    END
  END wbs_dat_i[25]
  PIN wbs_dat_i[26]
    DIRECTION INPUT ;
    USE SIGNAL ;
    PORT
      LAYER met3 ;
        RECT 0.000 504.600 4.000 505.200 ;
    END
  END wbs_dat_i[26]
  PIN wbs_dat_i[27]
    DIRECTION INPUT ;
    USE SIGNAL ;
    PORT
      LAYER met3 ;
        RECT 0.000 511.400 4.000 512.000 ;
    END
  END wbs_dat_i[27]
  PIN wbs_dat_i[28]
    DIRECTION INPUT ;
    USE SIGNAL ;
    PORT
      LAYER met3 ;
        RECT 0.000 518.200 4.000 518.800 ;
    END
  END wbs_dat_i[28]
  PIN wbs_dat_i[29]
    DIRECTION INPUT ;
    USE SIGNAL ;
    PORT
      LAYER met3 ;
        RECT 0.000 525.000 4.000 525.600 ;
    END
  END wbs_dat_i[29]
  PIN wbs_dat_i[2]
    DIRECTION INPUT ;
    USE SIGNAL ;
    PORT
      LAYER met3 ;
        RECT 0.000 341.400 4.000 342.000 ;
    END
  END wbs_dat_i[2]
  PIN wbs_dat_i[30]
    DIRECTION INPUT ;
    USE SIGNAL ;
    PORT
      LAYER met3 ;
        RECT 0.000 531.800 4.000 532.400 ;
    END
  END wbs_dat_i[30]
  PIN wbs_dat_i[31]
    DIRECTION INPUT ;
    USE SIGNAL ;
    PORT
      LAYER met3 ;
        RECT 0.000 538.600 4.000 539.200 ;
    END
  END wbs_dat_i[31]
  PIN wbs_dat_i[3]
    DIRECTION INPUT ;
    USE SIGNAL ;
    PORT
      LAYER met3 ;
        RECT 0.000 348.200 4.000 348.800 ;
    END
  END wbs_dat_i[3]
  PIN wbs_dat_i[4]
    DIRECTION INPUT ;
    USE SIGNAL ;
    PORT
      LAYER met3 ;
        RECT 0.000 355.000 4.000 355.600 ;
    END
  END wbs_dat_i[4]
  PIN wbs_dat_i[5]
    DIRECTION INPUT ;
    USE SIGNAL ;
    PORT
      LAYER met3 ;
        RECT 0.000 361.800 4.000 362.400 ;
    END
  END wbs_dat_i[5]
  PIN wbs_dat_i[6]
    DIRECTION INPUT ;
    USE SIGNAL ;
    PORT
      LAYER met3 ;
        RECT 0.000 368.600 4.000 369.200 ;
    END
  END wbs_dat_i[6]
  PIN wbs_dat_i[7]
    DIRECTION INPUT ;
    USE SIGNAL ;
    PORT
      LAYER met3 ;
        RECT 0.000 375.400 4.000 376.000 ;
    END
  END wbs_dat_i[7]
  PIN wbs_dat_i[8]
    DIRECTION INPUT ;
    USE SIGNAL ;
    PORT
      LAYER met3 ;
        RECT 0.000 382.200 4.000 382.800 ;
    END
  END wbs_dat_i[8]
  PIN wbs_dat_i[9]
    DIRECTION INPUT ;
    USE SIGNAL ;
    PORT
      LAYER met3 ;
        RECT 0.000 389.000 4.000 389.600 ;
    END
  END wbs_dat_i[9]
  PIN wbs_dat_o[0]
    DIRECTION OUTPUT ;
    USE SIGNAL ;
    PORT
      LAYER met3 ;
        RECT 0.000 545.400 4.000 546.000 ;
    END
  END wbs_dat_o[0]
  PIN wbs_dat_o[10]
    DIRECTION OUTPUT ;
    USE SIGNAL ;
    PORT
      LAYER met3 ;
        RECT 0.000 613.400 4.000 614.000 ;
    END
  END wbs_dat_o[10]
  PIN wbs_dat_o[11]
    DIRECTION OUTPUT ;
    USE SIGNAL ;
    PORT
      LAYER met3 ;
        RECT 0.000 620.200 4.000 620.800 ;
    END
  END wbs_dat_o[11]
  PIN wbs_dat_o[12]
    DIRECTION OUTPUT ;
    USE SIGNAL ;
    PORT
      LAYER met3 ;
        RECT 0.000 627.000 4.000 627.600 ;
    END
  END wbs_dat_o[12]
  PIN wbs_dat_o[13]
    DIRECTION OUTPUT ;
    USE SIGNAL ;
    PORT
      LAYER met3 ;
        RECT 0.000 633.800 4.000 634.400 ;
    END
  END wbs_dat_o[13]
  PIN wbs_dat_o[14]
    DIRECTION OUTPUT ;
    USE SIGNAL ;
    PORT
      LAYER met3 ;
        RECT 0.000 640.600 4.000 641.200 ;
    END
  END wbs_dat_o[14]
  PIN wbs_dat_o[15]
    DIRECTION OUTPUT ;
    USE SIGNAL ;
    PORT
      LAYER met3 ;
        RECT 0.000 647.400 4.000 648.000 ;
    END
  END wbs_dat_o[15]
  PIN wbs_dat_o[16]
    DIRECTION OUTPUT ;
    USE SIGNAL ;
    PORT
      LAYER met3 ;
        RECT 0.000 654.200 4.000 654.800 ;
    END
  END wbs_dat_o[16]
  PIN wbs_dat_o[17]
    DIRECTION OUTPUT ;
    USE SIGNAL ;
    PORT
      LAYER met3 ;
        RECT 0.000 661.000 4.000 661.600 ;
    END
  END wbs_dat_o[17]
  PIN wbs_dat_o[18]
    DIRECTION OUTPUT ;
    USE SIGNAL ;
    PORT
      LAYER met3 ;
        RECT 0.000 667.800 4.000 668.400 ;
    END
  END wbs_dat_o[18]
  PIN wbs_dat_o[19]
    DIRECTION OUTPUT ;
    USE SIGNAL ;
    PORT
      LAYER met3 ;
        RECT 0.000 674.600 4.000 675.200 ;
    END
  END wbs_dat_o[19]
  PIN wbs_dat_o[1]
    DIRECTION OUTPUT ;
    USE SIGNAL ;
    PORT
      LAYER met3 ;
        RECT 0.000 552.200 4.000 552.800 ;
    END
  END wbs_dat_o[1]
  PIN wbs_dat_o[20]
    DIRECTION OUTPUT ;
    USE SIGNAL ;
    PORT
      LAYER met3 ;
        RECT 0.000 681.400 4.000 682.000 ;
    END
  END wbs_dat_o[20]
  PIN wbs_dat_o[21]
    DIRECTION OUTPUT ;
    USE SIGNAL ;
    PORT
      LAYER met3 ;
        RECT 0.000 688.200 4.000 688.800 ;
    END
  END wbs_dat_o[21]
  PIN wbs_dat_o[22]
    DIRECTION OUTPUT ;
    USE SIGNAL ;
    PORT
      LAYER met3 ;
        RECT 0.000 695.000 4.000 695.600 ;
    END
  END wbs_dat_o[22]
  PIN wbs_dat_o[23]
    DIRECTION OUTPUT ;
    USE SIGNAL ;
    PORT
      LAYER met3 ;
        RECT 0.000 701.800 4.000 702.400 ;
    END
  END wbs_dat_o[23]
  PIN wbs_dat_o[24]
    DIRECTION OUTPUT ;
    USE SIGNAL ;
    PORT
      LAYER met3 ;
        RECT 0.000 708.600 4.000 709.200 ;
    END
  END wbs_dat_o[24]
  PIN wbs_dat_o[25]
    DIRECTION OUTPUT ;
    USE SIGNAL ;
    PORT
      LAYER met3 ;
        RECT 0.000 715.400 4.000 716.000 ;
    END
  END wbs_dat_o[25]
  PIN wbs_dat_o[26]
    DIRECTION OUTPUT ;
    USE SIGNAL ;
    PORT
      LAYER met3 ;
        RECT 0.000 722.200 4.000 722.800 ;
    END
  END wbs_dat_o[26]
  PIN wbs_dat_o[27]
    DIRECTION OUTPUT ;
    USE SIGNAL ;
    PORT
      LAYER met3 ;
        RECT 0.000 729.000 4.000 729.600 ;
    END
  END wbs_dat_o[27]
  PIN wbs_dat_o[28]
    DIRECTION OUTPUT ;
    USE SIGNAL ;
    PORT
      LAYER met3 ;
        RECT 0.000 735.800 4.000 736.400 ;
    END
  END wbs_dat_o[28]
  PIN wbs_dat_o[29]
    DIRECTION OUTPUT ;
    USE SIGNAL ;
    PORT
      LAYER met3 ;
        RECT 0.000 742.600 4.000 743.200 ;
    END
  END wbs_dat_o[29]
  PIN wbs_dat_o[2]
    DIRECTION OUTPUT ;
    USE SIGNAL ;
    PORT
      LAYER met3 ;
        RECT 0.000 559.000 4.000 559.600 ;
    END
  END wbs_dat_o[2]
  PIN wbs_dat_o[30]
    DIRECTION OUTPUT ;
    USE SIGNAL ;
    PORT
      LAYER met3 ;
        RECT 0.000 749.400 4.000 750.000 ;
    END
  END wbs_dat_o[30]
  PIN wbs_dat_o[31]
    DIRECTION OUTPUT ;
    USE SIGNAL ;
    PORT
      LAYER met3 ;
        RECT 0.000 756.200 4.000 756.800 ;
    END
  END wbs_dat_o[31]
  PIN wbs_dat_o[3]
    DIRECTION OUTPUT ;
    USE SIGNAL ;
    PORT
      LAYER met3 ;
        RECT 0.000 565.800 4.000 566.400 ;
    END
  END wbs_dat_o[3]
  PIN wbs_dat_o[4]
    DIRECTION OUTPUT ;
    USE SIGNAL ;
    PORT
      LAYER met3 ;
        RECT 0.000 572.600 4.000 573.200 ;
    END
  END wbs_dat_o[4]
  PIN wbs_dat_o[5]
    DIRECTION OUTPUT ;
    USE SIGNAL ;
    PORT
      LAYER met3 ;
        RECT 0.000 579.400 4.000 580.000 ;
    END
  END wbs_dat_o[5]
  PIN wbs_dat_o[6]
    DIRECTION OUTPUT ;
    USE SIGNAL ;
    PORT
      LAYER met3 ;
        RECT 0.000 586.200 4.000 586.800 ;
    END
  END wbs_dat_o[6]
  PIN wbs_dat_o[7]
    DIRECTION OUTPUT ;
    USE SIGNAL ;
    PORT
      LAYER met3 ;
        RECT 0.000 593.000 4.000 593.600 ;
    END
  END wbs_dat_o[7]
  PIN wbs_dat_o[8]
    DIRECTION OUTPUT ;
    USE SIGNAL ;
    PORT
      LAYER met3 ;
        RECT 0.000 599.800 4.000 600.400 ;
    END
  END wbs_dat_o[8]
  PIN wbs_dat_o[9]
    DIRECTION OUTPUT ;
    USE SIGNAL ;
    PORT
      LAYER met3 ;
        RECT 0.000 606.600 4.000 607.200 ;
    END
  END wbs_dat_o[9]
  PIN wbs_sel_i[0]
    DIRECTION INPUT ;
    USE SIGNAL ;
    PORT
      LAYER met3 ;
        RECT 0.000 763.000 4.000 763.600 ;
    END
  END wbs_sel_i[0]
  PIN wbs_sel_i[1]
    DIRECTION INPUT ;
    USE SIGNAL ;
    PORT
      LAYER met3 ;
        RECT 0.000 769.800 4.000 770.400 ;
    END
  END wbs_sel_i[1]
  PIN wbs_sel_i[2]
    DIRECTION INPUT ;
    USE SIGNAL ;
    PORT
      LAYER met3 ;
        RECT 0.000 776.600 4.000 777.200 ;
    END
  END wbs_sel_i[2]
  PIN wbs_sel_i[3]
    DIRECTION INPUT ;
    USE SIGNAL ;
    PORT
      LAYER met3 ;
        RECT 0.000 783.400 4.000 784.000 ;
    END
  END wbs_sel_i[3]
  PIN wbs_stb_i
    DIRECTION INPUT ;
    USE SIGNAL ;
    PORT
      LAYER met3 ;
        RECT 0.000 790.200 4.000 790.800 ;
    END
  END wbs_stb_i
  PIN wbs_we_i
    DIRECTION INPUT ;
    USE SIGNAL ;
    PORT
      LAYER met3 ;
        RECT 0.000 797.000 4.000 797.600 ;
    END
  END wbs_we_i
  OBS
      LAYER nwell ;
        RECT 5.330 10.795 2914.290 3508.885 ;
      LAYER li1 ;
        RECT 5.520 10.795 2914.100 3508.885 ;
      LAYER met1 ;
        RECT 5.520 10.640 2914.100 3509.040 ;
      LAYER met2 ;
        RECT 5.610 3515.720 43.510 3516.690 ;
        RECT 44.350 3515.720 118.030 3516.690 ;
        RECT 118.870 3515.720 192.550 3516.690 ;
        RECT 193.390 3515.720 267.070 3516.690 ;
        RECT 267.910 3515.720 341.590 3516.690 ;
        RECT 342.430 3515.720 416.110 3516.690 ;
        RECT 416.950 3515.720 490.630 3516.690 ;
        RECT 491.470 3515.720 565.150 3516.690 ;
        RECT 565.990 3515.720 639.670 3516.690 ;
        RECT 640.510 3515.720 714.190 3516.690 ;
        RECT 715.030 3515.720 788.710 3516.690 ;
        RECT 789.550 3515.720 863.230 3516.690 ;
        RECT 864.070 3515.720 937.750 3516.690 ;
        RECT 938.590 3515.720 1012.270 3516.690 ;
        RECT 1013.110 3515.720 1086.790 3516.690 ;
        RECT 1087.630 3515.720 1161.310 3516.690 ;
        RECT 1162.150 3515.720 1235.830 3516.690 ;
        RECT 1236.670 3515.720 1310.350 3516.690 ;
        RECT 1311.190 3515.720 1384.870 3516.690 ;
        RECT 1385.710 3515.720 1459.390 3516.690 ;
        RECT 1460.230 3515.720 1533.910 3516.690 ;
        RECT 1534.750 3515.720 1608.430 3516.690 ;
        RECT 1609.270 3515.720 1682.950 3516.690 ;
        RECT 1683.790 3515.720 1757.470 3516.690 ;
        RECT 1758.310 3515.720 1831.990 3516.690 ;
        RECT 1832.830 3515.720 1906.510 3516.690 ;
        RECT 1907.350 3515.720 1981.030 3516.690 ;
        RECT 1981.870 3515.720 2055.550 3516.690 ;
        RECT 2056.390 3515.720 2130.070 3516.690 ;
        RECT 2130.910 3515.720 2204.590 3516.690 ;
        RECT 2205.430 3515.720 2279.110 3516.690 ;
        RECT 2279.950 3515.720 2353.630 3516.690 ;
        RECT 2354.470 3515.720 2428.150 3516.690 ;
        RECT 2428.990 3515.720 2502.670 3516.690 ;
        RECT 2503.510 3515.720 2577.190 3516.690 ;
        RECT 2578.030 3515.720 2651.710 3516.690 ;
        RECT 2652.550 3515.720 2726.230 3516.690 ;
        RECT 2727.070 3515.720 2800.750 3516.690 ;
        RECT 2801.590 3515.720 2875.270 3516.690 ;
        RECT 2876.110 3515.720 2914.010 3516.690 ;
        RECT 5.610 4.280 2914.010 3515.720 ;
        RECT 5.610 4.000 42.130 4.280 ;
        RECT 42.970 4.000 114.810 4.280 ;
        RECT 115.650 4.000 187.490 4.280 ;
        RECT 188.330 4.000 260.170 4.280 ;
        RECT 261.010 4.000 332.850 4.280 ;
        RECT 333.690 4.000 405.530 4.280 ;
        RECT 406.370 4.000 478.210 4.280 ;
        RECT 479.050 4.000 550.890 4.280 ;
        RECT 551.730 4.000 623.570 4.280 ;
        RECT 624.410 4.000 696.250 4.280 ;
        RECT 697.090 4.000 768.930 4.280 ;
        RECT 769.770 4.000 841.610 4.280 ;
        RECT 842.450 4.000 914.290 4.280 ;
        RECT 915.130 4.000 986.970 4.280 ;
        RECT 987.810 4.000 1059.650 4.280 ;
        RECT 1060.490 4.000 1132.330 4.280 ;
        RECT 1133.170 4.000 1205.010 4.280 ;
        RECT 1205.850 4.000 1277.690 4.280 ;
        RECT 1278.530 4.000 1350.370 4.280 ;
        RECT 1351.210 4.000 1423.050 4.280 ;
        RECT 1423.890 4.000 1495.730 4.280 ;
        RECT 1496.570 4.000 1568.410 4.280 ;
        RECT 1569.250 4.000 1641.090 4.280 ;
        RECT 1641.930 4.000 1713.770 4.280 ;
        RECT 1714.610 4.000 1786.450 4.280 ;
        RECT 1787.290 4.000 1859.130 4.280 ;
        RECT 1859.970 4.000 1931.810 4.280 ;
        RECT 1932.650 4.000 2004.490 4.280 ;
        RECT 2005.330 4.000 2077.170 4.280 ;
        RECT 2078.010 4.000 2149.850 4.280 ;
        RECT 2150.690 4.000 2222.530 4.280 ;
        RECT 2223.370 4.000 2295.210 4.280 ;
        RECT 2296.050 4.000 2367.890 4.280 ;
        RECT 2368.730 4.000 2440.570 4.280 ;
        RECT 2441.410 4.000 2513.250 4.280 ;
        RECT 2514.090 4.000 2585.930 4.280 ;
        RECT 2586.770 4.000 2658.610 4.280 ;
        RECT 2659.450 4.000 2731.290 4.280 ;
        RECT 2732.130 4.000 2803.970 4.280 ;
        RECT 2804.810 4.000 2876.650 4.280 ;
        RECT 2877.490 4.000 2914.010 4.280 ;
      LAYER met3 ;
        RECT 4.000 3409.200 2916.000 3507.945 ;
        RECT 4.400 3407.800 2916.000 3409.200 ;
        RECT 4.000 3402.400 2916.000 3407.800 ;
        RECT 4.400 3401.000 2916.000 3402.400 ;
        RECT 4.000 3395.600 2916.000 3401.000 ;
        RECT 4.400 3394.200 2916.000 3395.600 ;
        RECT 4.000 3388.800 2916.000 3394.200 ;
        RECT 4.400 3387.400 2916.000 3388.800 ;
        RECT 4.000 3382.000 2916.000 3387.400 ;
        RECT 4.400 3380.600 2916.000 3382.000 ;
        RECT 4.000 3375.200 2916.000 3380.600 ;
        RECT 4.400 3373.800 2916.000 3375.200 ;
        RECT 4.000 3368.400 2916.000 3373.800 ;
        RECT 4.400 3367.000 2916.000 3368.400 ;
        RECT 4.000 3361.600 2916.000 3367.000 ;
        RECT 4.400 3360.200 2916.000 3361.600 ;
        RECT 4.000 3354.800 2916.000 3360.200 ;
        RECT 4.400 3353.400 2916.000 3354.800 ;
        RECT 4.000 3348.000 2916.000 3353.400 ;
        RECT 4.400 3346.600 2916.000 3348.000 ;
        RECT 4.000 3341.200 2916.000 3346.600 ;
        RECT 4.400 3339.800 2916.000 3341.200 ;
        RECT 4.000 3334.400 2916.000 3339.800 ;
        RECT 4.400 3333.000 2916.000 3334.400 ;
        RECT 4.000 3327.600 2916.000 3333.000 ;
        RECT 4.400 3326.200 2916.000 3327.600 ;
        RECT 4.000 3320.800 2916.000 3326.200 ;
        RECT 4.400 3319.400 2916.000 3320.800 ;
        RECT 4.000 3314.000 2916.000 3319.400 ;
        RECT 4.400 3312.600 2916.000 3314.000 ;
        RECT 4.000 3307.200 2916.000 3312.600 ;
        RECT 4.400 3305.800 2916.000 3307.200 ;
        RECT 4.000 3300.400 2916.000 3305.800 ;
        RECT 4.400 3299.000 2916.000 3300.400 ;
        RECT 4.000 3293.600 2916.000 3299.000 ;
        RECT 4.400 3292.200 2916.000 3293.600 ;
        RECT 4.000 3286.800 2916.000 3292.200 ;
        RECT 4.400 3285.400 2916.000 3286.800 ;
        RECT 4.000 3280.000 2916.000 3285.400 ;
        RECT 4.400 3278.600 2916.000 3280.000 ;
        RECT 4.000 3273.200 2916.000 3278.600 ;
        RECT 4.400 3271.800 2916.000 3273.200 ;
        RECT 4.000 3266.400 2916.000 3271.800 ;
        RECT 4.400 3265.000 2916.000 3266.400 ;
        RECT 4.000 3259.600 2916.000 3265.000 ;
        RECT 4.400 3258.200 2915.600 3259.600 ;
        RECT 4.000 3252.800 2916.000 3258.200 ;
        RECT 4.400 3251.400 2916.000 3252.800 ;
        RECT 4.000 3246.000 2916.000 3251.400 ;
        RECT 4.400 3244.600 2916.000 3246.000 ;
        RECT 4.000 3239.200 2916.000 3244.600 ;
        RECT 4.400 3237.800 2916.000 3239.200 ;
        RECT 4.000 3232.400 2916.000 3237.800 ;
        RECT 4.400 3231.000 2916.000 3232.400 ;
        RECT 4.000 3225.600 2916.000 3231.000 ;
        RECT 4.400 3224.200 2916.000 3225.600 ;
        RECT 4.000 3218.800 2916.000 3224.200 ;
        RECT 4.400 3217.400 2916.000 3218.800 ;
        RECT 4.000 3212.000 2916.000 3217.400 ;
        RECT 4.400 3210.600 2915.600 3212.000 ;
        RECT 4.000 3205.200 2916.000 3210.600 ;
        RECT 4.400 3203.800 2916.000 3205.200 ;
        RECT 4.000 3198.400 2916.000 3203.800 ;
        RECT 4.400 3197.000 2916.000 3198.400 ;
        RECT 4.000 3191.600 2916.000 3197.000 ;
        RECT 4.400 3190.200 2916.000 3191.600 ;
        RECT 4.000 3184.800 2916.000 3190.200 ;
        RECT 4.400 3183.400 2916.000 3184.800 ;
        RECT 4.000 3178.000 2916.000 3183.400 ;
        RECT 4.400 3176.600 2916.000 3178.000 ;
        RECT 4.000 3171.200 2916.000 3176.600 ;
        RECT 4.400 3169.800 2916.000 3171.200 ;
        RECT 4.000 3164.400 2916.000 3169.800 ;
        RECT 4.400 3163.000 2915.600 3164.400 ;
        RECT 4.000 3157.600 2916.000 3163.000 ;
        RECT 4.400 3156.200 2916.000 3157.600 ;
        RECT 4.000 3150.800 2916.000 3156.200 ;
        RECT 4.400 3149.400 2916.000 3150.800 ;
        RECT 4.000 3144.000 2916.000 3149.400 ;
        RECT 4.400 3142.600 2916.000 3144.000 ;
        RECT 4.000 3137.200 2916.000 3142.600 ;
        RECT 4.400 3135.800 2916.000 3137.200 ;
        RECT 4.000 3130.400 2916.000 3135.800 ;
        RECT 4.400 3129.000 2916.000 3130.400 ;
        RECT 4.000 3123.600 2916.000 3129.000 ;
        RECT 4.400 3122.200 2916.000 3123.600 ;
        RECT 4.000 3116.800 2916.000 3122.200 ;
        RECT 4.400 3115.400 2915.600 3116.800 ;
        RECT 4.000 3110.000 2916.000 3115.400 ;
        RECT 4.400 3108.600 2916.000 3110.000 ;
        RECT 4.000 3103.200 2916.000 3108.600 ;
        RECT 4.400 3101.800 2916.000 3103.200 ;
        RECT 4.000 3096.400 2916.000 3101.800 ;
        RECT 4.400 3095.000 2916.000 3096.400 ;
        RECT 4.000 3089.600 2916.000 3095.000 ;
        RECT 4.400 3088.200 2916.000 3089.600 ;
        RECT 4.000 3082.800 2916.000 3088.200 ;
        RECT 4.400 3081.400 2916.000 3082.800 ;
        RECT 4.000 3076.000 2916.000 3081.400 ;
        RECT 4.400 3074.600 2916.000 3076.000 ;
        RECT 4.000 3069.200 2916.000 3074.600 ;
        RECT 4.400 3067.800 2915.600 3069.200 ;
        RECT 4.000 3062.400 2916.000 3067.800 ;
        RECT 4.400 3061.000 2916.000 3062.400 ;
        RECT 4.000 3055.600 2916.000 3061.000 ;
        RECT 4.400 3054.200 2916.000 3055.600 ;
        RECT 4.000 3048.800 2916.000 3054.200 ;
        RECT 4.400 3047.400 2916.000 3048.800 ;
        RECT 4.000 3042.000 2916.000 3047.400 ;
        RECT 4.400 3040.600 2916.000 3042.000 ;
        RECT 4.000 3035.200 2916.000 3040.600 ;
        RECT 4.400 3033.800 2916.000 3035.200 ;
        RECT 4.000 3028.400 2916.000 3033.800 ;
        RECT 4.400 3027.000 2916.000 3028.400 ;
        RECT 4.000 3021.600 2916.000 3027.000 ;
        RECT 4.400 3020.200 2915.600 3021.600 ;
        RECT 4.000 3014.800 2916.000 3020.200 ;
        RECT 4.400 3013.400 2916.000 3014.800 ;
        RECT 4.000 3008.000 2916.000 3013.400 ;
        RECT 4.400 3006.600 2916.000 3008.000 ;
        RECT 4.000 3001.200 2916.000 3006.600 ;
        RECT 4.400 2999.800 2916.000 3001.200 ;
        RECT 4.000 2994.400 2916.000 2999.800 ;
        RECT 4.400 2993.000 2916.000 2994.400 ;
        RECT 4.000 2987.600 2916.000 2993.000 ;
        RECT 4.400 2986.200 2916.000 2987.600 ;
        RECT 4.000 2980.800 2916.000 2986.200 ;
        RECT 4.400 2979.400 2916.000 2980.800 ;
        RECT 4.000 2974.000 2916.000 2979.400 ;
        RECT 4.400 2972.600 2915.600 2974.000 ;
        RECT 4.000 2967.200 2916.000 2972.600 ;
        RECT 4.400 2965.800 2916.000 2967.200 ;
        RECT 4.000 2960.400 2916.000 2965.800 ;
        RECT 4.400 2959.000 2916.000 2960.400 ;
        RECT 4.000 2953.600 2916.000 2959.000 ;
        RECT 4.400 2952.200 2916.000 2953.600 ;
        RECT 4.000 2946.800 2916.000 2952.200 ;
        RECT 4.400 2945.400 2916.000 2946.800 ;
        RECT 4.000 2940.000 2916.000 2945.400 ;
        RECT 4.400 2938.600 2916.000 2940.000 ;
        RECT 4.000 2933.200 2916.000 2938.600 ;
        RECT 4.400 2931.800 2916.000 2933.200 ;
        RECT 4.000 2926.400 2916.000 2931.800 ;
        RECT 4.400 2925.000 2915.600 2926.400 ;
        RECT 4.000 2919.600 2916.000 2925.000 ;
        RECT 4.400 2918.200 2916.000 2919.600 ;
        RECT 4.000 2912.800 2916.000 2918.200 ;
        RECT 4.400 2911.400 2916.000 2912.800 ;
        RECT 4.000 2906.000 2916.000 2911.400 ;
        RECT 4.400 2904.600 2916.000 2906.000 ;
        RECT 4.000 2899.200 2916.000 2904.600 ;
        RECT 4.400 2897.800 2916.000 2899.200 ;
        RECT 4.000 2892.400 2916.000 2897.800 ;
        RECT 4.400 2891.000 2916.000 2892.400 ;
        RECT 4.000 2885.600 2916.000 2891.000 ;
        RECT 4.400 2884.200 2916.000 2885.600 ;
        RECT 4.000 2878.800 2916.000 2884.200 ;
        RECT 4.400 2877.400 2915.600 2878.800 ;
        RECT 4.000 2872.000 2916.000 2877.400 ;
        RECT 4.400 2870.600 2916.000 2872.000 ;
        RECT 4.000 2865.200 2916.000 2870.600 ;
        RECT 4.400 2863.800 2916.000 2865.200 ;
        RECT 4.000 2858.400 2916.000 2863.800 ;
        RECT 4.400 2857.000 2916.000 2858.400 ;
        RECT 4.000 2851.600 2916.000 2857.000 ;
        RECT 4.400 2850.200 2916.000 2851.600 ;
        RECT 4.000 2844.800 2916.000 2850.200 ;
        RECT 4.400 2843.400 2916.000 2844.800 ;
        RECT 4.000 2838.000 2916.000 2843.400 ;
        RECT 4.400 2836.600 2916.000 2838.000 ;
        RECT 4.000 2831.200 2916.000 2836.600 ;
        RECT 4.400 2829.800 2915.600 2831.200 ;
        RECT 4.000 2824.400 2916.000 2829.800 ;
        RECT 4.400 2823.000 2916.000 2824.400 ;
        RECT 4.000 2817.600 2916.000 2823.000 ;
        RECT 4.400 2816.200 2916.000 2817.600 ;
        RECT 4.000 2810.800 2916.000 2816.200 ;
        RECT 4.400 2809.400 2916.000 2810.800 ;
        RECT 4.000 2804.000 2916.000 2809.400 ;
        RECT 4.400 2802.600 2916.000 2804.000 ;
        RECT 4.000 2797.200 2916.000 2802.600 ;
        RECT 4.400 2795.800 2916.000 2797.200 ;
        RECT 4.000 2790.400 2916.000 2795.800 ;
        RECT 4.400 2789.000 2916.000 2790.400 ;
        RECT 4.000 2783.600 2916.000 2789.000 ;
        RECT 4.400 2782.200 2915.600 2783.600 ;
        RECT 4.000 2776.800 2916.000 2782.200 ;
        RECT 4.400 2775.400 2916.000 2776.800 ;
        RECT 4.000 2770.000 2916.000 2775.400 ;
        RECT 4.400 2768.600 2916.000 2770.000 ;
        RECT 4.000 2763.200 2916.000 2768.600 ;
        RECT 4.400 2761.800 2916.000 2763.200 ;
        RECT 4.000 2756.400 2916.000 2761.800 ;
        RECT 4.400 2755.000 2916.000 2756.400 ;
        RECT 4.000 2749.600 2916.000 2755.000 ;
        RECT 4.400 2748.200 2916.000 2749.600 ;
        RECT 4.000 2742.800 2916.000 2748.200 ;
        RECT 4.400 2741.400 2916.000 2742.800 ;
        RECT 4.000 2736.000 2916.000 2741.400 ;
        RECT 4.400 2734.600 2915.600 2736.000 ;
        RECT 4.000 2729.200 2916.000 2734.600 ;
        RECT 4.400 2727.800 2916.000 2729.200 ;
        RECT 4.000 2722.400 2916.000 2727.800 ;
        RECT 4.400 2721.000 2916.000 2722.400 ;
        RECT 4.000 2715.600 2916.000 2721.000 ;
        RECT 4.400 2714.200 2916.000 2715.600 ;
        RECT 4.000 2708.800 2916.000 2714.200 ;
        RECT 4.400 2707.400 2916.000 2708.800 ;
        RECT 4.000 2702.000 2916.000 2707.400 ;
        RECT 4.400 2700.600 2916.000 2702.000 ;
        RECT 4.000 2695.200 2916.000 2700.600 ;
        RECT 4.400 2693.800 2916.000 2695.200 ;
        RECT 4.000 2688.400 2916.000 2693.800 ;
        RECT 4.400 2687.000 2915.600 2688.400 ;
        RECT 4.000 2681.600 2916.000 2687.000 ;
        RECT 4.400 2680.200 2916.000 2681.600 ;
        RECT 4.000 2674.800 2916.000 2680.200 ;
        RECT 4.400 2673.400 2916.000 2674.800 ;
        RECT 4.000 2668.000 2916.000 2673.400 ;
        RECT 4.400 2666.600 2916.000 2668.000 ;
        RECT 4.000 2661.200 2916.000 2666.600 ;
        RECT 4.400 2659.800 2916.000 2661.200 ;
        RECT 4.000 2654.400 2916.000 2659.800 ;
        RECT 4.400 2653.000 2916.000 2654.400 ;
        RECT 4.000 2647.600 2916.000 2653.000 ;
        RECT 4.400 2646.200 2916.000 2647.600 ;
        RECT 4.000 2640.800 2916.000 2646.200 ;
        RECT 4.400 2639.400 2915.600 2640.800 ;
        RECT 4.000 2634.000 2916.000 2639.400 ;
        RECT 4.400 2632.600 2916.000 2634.000 ;
        RECT 4.000 2627.200 2916.000 2632.600 ;
        RECT 4.400 2625.800 2916.000 2627.200 ;
        RECT 4.000 2620.400 2916.000 2625.800 ;
        RECT 4.400 2619.000 2916.000 2620.400 ;
        RECT 4.000 2613.600 2916.000 2619.000 ;
        RECT 4.400 2612.200 2916.000 2613.600 ;
        RECT 4.000 2606.800 2916.000 2612.200 ;
        RECT 4.400 2605.400 2916.000 2606.800 ;
        RECT 4.000 2600.000 2916.000 2605.400 ;
        RECT 4.400 2598.600 2916.000 2600.000 ;
        RECT 4.000 2593.200 2916.000 2598.600 ;
        RECT 4.400 2591.800 2915.600 2593.200 ;
        RECT 4.000 2586.400 2916.000 2591.800 ;
        RECT 4.400 2585.000 2916.000 2586.400 ;
        RECT 4.000 2579.600 2916.000 2585.000 ;
        RECT 4.400 2578.200 2916.000 2579.600 ;
        RECT 4.000 2572.800 2916.000 2578.200 ;
        RECT 4.400 2571.400 2916.000 2572.800 ;
        RECT 4.000 2566.000 2916.000 2571.400 ;
        RECT 4.400 2564.600 2916.000 2566.000 ;
        RECT 4.000 2559.200 2916.000 2564.600 ;
        RECT 4.400 2557.800 2916.000 2559.200 ;
        RECT 4.000 2552.400 2916.000 2557.800 ;
        RECT 4.400 2551.000 2916.000 2552.400 ;
        RECT 4.000 2545.600 2916.000 2551.000 ;
        RECT 4.400 2544.200 2915.600 2545.600 ;
        RECT 4.000 2538.800 2916.000 2544.200 ;
        RECT 4.400 2537.400 2916.000 2538.800 ;
        RECT 4.000 2532.000 2916.000 2537.400 ;
        RECT 4.400 2530.600 2916.000 2532.000 ;
        RECT 4.000 2525.200 2916.000 2530.600 ;
        RECT 4.400 2523.800 2916.000 2525.200 ;
        RECT 4.000 2518.400 2916.000 2523.800 ;
        RECT 4.400 2517.000 2916.000 2518.400 ;
        RECT 4.000 2511.600 2916.000 2517.000 ;
        RECT 4.400 2510.200 2916.000 2511.600 ;
        RECT 4.000 2504.800 2916.000 2510.200 ;
        RECT 4.400 2503.400 2916.000 2504.800 ;
        RECT 4.000 2498.000 2916.000 2503.400 ;
        RECT 4.400 2496.600 2915.600 2498.000 ;
        RECT 4.000 2491.200 2916.000 2496.600 ;
        RECT 4.400 2489.800 2916.000 2491.200 ;
        RECT 4.000 2484.400 2916.000 2489.800 ;
        RECT 4.400 2483.000 2916.000 2484.400 ;
        RECT 4.000 2477.600 2916.000 2483.000 ;
        RECT 4.400 2476.200 2916.000 2477.600 ;
        RECT 4.000 2470.800 2916.000 2476.200 ;
        RECT 4.400 2469.400 2916.000 2470.800 ;
        RECT 4.000 2464.000 2916.000 2469.400 ;
        RECT 4.400 2462.600 2916.000 2464.000 ;
        RECT 4.000 2457.200 2916.000 2462.600 ;
        RECT 4.400 2455.800 2916.000 2457.200 ;
        RECT 4.000 2450.400 2916.000 2455.800 ;
        RECT 4.400 2449.000 2915.600 2450.400 ;
        RECT 4.000 2443.600 2916.000 2449.000 ;
        RECT 4.400 2442.200 2916.000 2443.600 ;
        RECT 4.000 2436.800 2916.000 2442.200 ;
        RECT 4.400 2435.400 2916.000 2436.800 ;
        RECT 4.000 2430.000 2916.000 2435.400 ;
        RECT 4.400 2428.600 2916.000 2430.000 ;
        RECT 4.000 2423.200 2916.000 2428.600 ;
        RECT 4.400 2421.800 2916.000 2423.200 ;
        RECT 4.000 2416.400 2916.000 2421.800 ;
        RECT 4.400 2415.000 2916.000 2416.400 ;
        RECT 4.000 2409.600 2916.000 2415.000 ;
        RECT 4.400 2408.200 2916.000 2409.600 ;
        RECT 4.000 2402.800 2916.000 2408.200 ;
        RECT 4.400 2401.400 2915.600 2402.800 ;
        RECT 4.000 2396.000 2916.000 2401.400 ;
        RECT 4.400 2394.600 2916.000 2396.000 ;
        RECT 4.000 2389.200 2916.000 2394.600 ;
        RECT 4.400 2387.800 2916.000 2389.200 ;
        RECT 4.000 2382.400 2916.000 2387.800 ;
        RECT 4.400 2381.000 2916.000 2382.400 ;
        RECT 4.000 2375.600 2916.000 2381.000 ;
        RECT 4.400 2374.200 2916.000 2375.600 ;
        RECT 4.000 2368.800 2916.000 2374.200 ;
        RECT 4.400 2367.400 2916.000 2368.800 ;
        RECT 4.000 2362.000 2916.000 2367.400 ;
        RECT 4.400 2360.600 2916.000 2362.000 ;
        RECT 4.000 2355.200 2916.000 2360.600 ;
        RECT 4.400 2353.800 2915.600 2355.200 ;
        RECT 4.000 2348.400 2916.000 2353.800 ;
        RECT 4.400 2347.000 2916.000 2348.400 ;
        RECT 4.000 2341.600 2916.000 2347.000 ;
        RECT 4.400 2340.200 2916.000 2341.600 ;
        RECT 4.000 2334.800 2916.000 2340.200 ;
        RECT 4.400 2333.400 2916.000 2334.800 ;
        RECT 4.000 2328.000 2916.000 2333.400 ;
        RECT 4.400 2326.600 2916.000 2328.000 ;
        RECT 4.000 2321.200 2916.000 2326.600 ;
        RECT 4.400 2319.800 2916.000 2321.200 ;
        RECT 4.000 2314.400 2916.000 2319.800 ;
        RECT 4.400 2313.000 2916.000 2314.400 ;
        RECT 4.000 2307.600 2916.000 2313.000 ;
        RECT 4.400 2306.200 2915.600 2307.600 ;
        RECT 4.000 2300.800 2916.000 2306.200 ;
        RECT 4.400 2299.400 2916.000 2300.800 ;
        RECT 4.000 2294.000 2916.000 2299.400 ;
        RECT 4.400 2292.600 2916.000 2294.000 ;
        RECT 4.000 2287.200 2916.000 2292.600 ;
        RECT 4.400 2285.800 2916.000 2287.200 ;
        RECT 4.000 2280.400 2916.000 2285.800 ;
        RECT 4.400 2279.000 2916.000 2280.400 ;
        RECT 4.000 2273.600 2916.000 2279.000 ;
        RECT 4.400 2272.200 2916.000 2273.600 ;
        RECT 4.000 2266.800 2916.000 2272.200 ;
        RECT 4.400 2265.400 2916.000 2266.800 ;
        RECT 4.000 2260.000 2916.000 2265.400 ;
        RECT 4.400 2258.600 2915.600 2260.000 ;
        RECT 4.000 2253.200 2916.000 2258.600 ;
        RECT 4.400 2251.800 2916.000 2253.200 ;
        RECT 4.000 2246.400 2916.000 2251.800 ;
        RECT 4.400 2245.000 2916.000 2246.400 ;
        RECT 4.000 2239.600 2916.000 2245.000 ;
        RECT 4.400 2238.200 2916.000 2239.600 ;
        RECT 4.000 2232.800 2916.000 2238.200 ;
        RECT 4.400 2231.400 2916.000 2232.800 ;
        RECT 4.000 2226.000 2916.000 2231.400 ;
        RECT 4.400 2224.600 2916.000 2226.000 ;
        RECT 4.000 2219.200 2916.000 2224.600 ;
        RECT 4.400 2217.800 2916.000 2219.200 ;
        RECT 4.000 2212.400 2916.000 2217.800 ;
        RECT 4.400 2211.000 2915.600 2212.400 ;
        RECT 4.000 2205.600 2916.000 2211.000 ;
        RECT 4.400 2204.200 2916.000 2205.600 ;
        RECT 4.000 2198.800 2916.000 2204.200 ;
        RECT 4.400 2197.400 2916.000 2198.800 ;
        RECT 4.000 2192.000 2916.000 2197.400 ;
        RECT 4.400 2190.600 2916.000 2192.000 ;
        RECT 4.000 2185.200 2916.000 2190.600 ;
        RECT 4.400 2183.800 2916.000 2185.200 ;
        RECT 4.000 2178.400 2916.000 2183.800 ;
        RECT 4.400 2177.000 2916.000 2178.400 ;
        RECT 4.000 2171.600 2916.000 2177.000 ;
        RECT 4.400 2170.200 2916.000 2171.600 ;
        RECT 4.000 2164.800 2916.000 2170.200 ;
        RECT 4.400 2163.400 2915.600 2164.800 ;
        RECT 4.000 2158.000 2916.000 2163.400 ;
        RECT 4.400 2156.600 2916.000 2158.000 ;
        RECT 4.000 2151.200 2916.000 2156.600 ;
        RECT 4.400 2149.800 2916.000 2151.200 ;
        RECT 4.000 2144.400 2916.000 2149.800 ;
        RECT 4.400 2143.000 2916.000 2144.400 ;
        RECT 4.000 2137.600 2916.000 2143.000 ;
        RECT 4.400 2136.200 2916.000 2137.600 ;
        RECT 4.000 2130.800 2916.000 2136.200 ;
        RECT 4.400 2129.400 2916.000 2130.800 ;
        RECT 4.000 2124.000 2916.000 2129.400 ;
        RECT 4.400 2122.600 2916.000 2124.000 ;
        RECT 4.000 2117.200 2916.000 2122.600 ;
        RECT 4.400 2115.800 2915.600 2117.200 ;
        RECT 4.000 2110.400 2916.000 2115.800 ;
        RECT 4.400 2109.000 2916.000 2110.400 ;
        RECT 4.000 2103.600 2916.000 2109.000 ;
        RECT 4.400 2102.200 2916.000 2103.600 ;
        RECT 4.000 2096.800 2916.000 2102.200 ;
        RECT 4.400 2095.400 2916.000 2096.800 ;
        RECT 4.000 2090.000 2916.000 2095.400 ;
        RECT 4.400 2088.600 2916.000 2090.000 ;
        RECT 4.000 2083.200 2916.000 2088.600 ;
        RECT 4.400 2081.800 2916.000 2083.200 ;
        RECT 4.000 2076.400 2916.000 2081.800 ;
        RECT 4.400 2075.000 2916.000 2076.400 ;
        RECT 4.000 2069.600 2916.000 2075.000 ;
        RECT 4.400 2068.200 2915.600 2069.600 ;
        RECT 4.000 2062.800 2916.000 2068.200 ;
        RECT 4.400 2061.400 2916.000 2062.800 ;
        RECT 4.000 2056.000 2916.000 2061.400 ;
        RECT 4.400 2054.600 2916.000 2056.000 ;
        RECT 4.000 2049.200 2916.000 2054.600 ;
        RECT 4.400 2047.800 2916.000 2049.200 ;
        RECT 4.000 2042.400 2916.000 2047.800 ;
        RECT 4.400 2041.000 2916.000 2042.400 ;
        RECT 4.000 2035.600 2916.000 2041.000 ;
        RECT 4.400 2034.200 2916.000 2035.600 ;
        RECT 4.000 2028.800 2916.000 2034.200 ;
        RECT 4.400 2027.400 2916.000 2028.800 ;
        RECT 4.000 2022.000 2916.000 2027.400 ;
        RECT 4.400 2020.600 2915.600 2022.000 ;
        RECT 4.000 2015.200 2916.000 2020.600 ;
        RECT 4.400 2013.800 2916.000 2015.200 ;
        RECT 4.000 2008.400 2916.000 2013.800 ;
        RECT 4.400 2007.000 2916.000 2008.400 ;
        RECT 4.000 2001.600 2916.000 2007.000 ;
        RECT 4.400 2000.200 2916.000 2001.600 ;
        RECT 4.000 1994.800 2916.000 2000.200 ;
        RECT 4.400 1993.400 2916.000 1994.800 ;
        RECT 4.000 1988.000 2916.000 1993.400 ;
        RECT 4.400 1986.600 2916.000 1988.000 ;
        RECT 4.000 1981.200 2916.000 1986.600 ;
        RECT 4.400 1979.800 2916.000 1981.200 ;
        RECT 4.000 1974.400 2916.000 1979.800 ;
        RECT 4.400 1973.000 2915.600 1974.400 ;
        RECT 4.000 1967.600 2916.000 1973.000 ;
        RECT 4.400 1966.200 2916.000 1967.600 ;
        RECT 4.000 1960.800 2916.000 1966.200 ;
        RECT 4.400 1959.400 2916.000 1960.800 ;
        RECT 4.000 1954.000 2916.000 1959.400 ;
        RECT 4.400 1952.600 2916.000 1954.000 ;
        RECT 4.000 1947.200 2916.000 1952.600 ;
        RECT 4.400 1945.800 2916.000 1947.200 ;
        RECT 4.000 1940.400 2916.000 1945.800 ;
        RECT 4.400 1939.000 2916.000 1940.400 ;
        RECT 4.000 1933.600 2916.000 1939.000 ;
        RECT 4.400 1932.200 2916.000 1933.600 ;
        RECT 4.000 1926.800 2916.000 1932.200 ;
        RECT 4.400 1925.400 2915.600 1926.800 ;
        RECT 4.000 1920.000 2916.000 1925.400 ;
        RECT 4.400 1918.600 2916.000 1920.000 ;
        RECT 4.000 1913.200 2916.000 1918.600 ;
        RECT 4.400 1911.800 2916.000 1913.200 ;
        RECT 4.000 1906.400 2916.000 1911.800 ;
        RECT 4.400 1905.000 2916.000 1906.400 ;
        RECT 4.000 1899.600 2916.000 1905.000 ;
        RECT 4.400 1898.200 2916.000 1899.600 ;
        RECT 4.000 1892.800 2916.000 1898.200 ;
        RECT 4.400 1891.400 2916.000 1892.800 ;
        RECT 4.000 1886.000 2916.000 1891.400 ;
        RECT 4.400 1884.600 2916.000 1886.000 ;
        RECT 4.000 1879.200 2916.000 1884.600 ;
        RECT 4.400 1877.800 2915.600 1879.200 ;
        RECT 4.000 1872.400 2916.000 1877.800 ;
        RECT 4.400 1871.000 2916.000 1872.400 ;
        RECT 4.000 1865.600 2916.000 1871.000 ;
        RECT 4.400 1864.200 2916.000 1865.600 ;
        RECT 4.000 1858.800 2916.000 1864.200 ;
        RECT 4.400 1857.400 2916.000 1858.800 ;
        RECT 4.000 1852.000 2916.000 1857.400 ;
        RECT 4.400 1850.600 2916.000 1852.000 ;
        RECT 4.000 1845.200 2916.000 1850.600 ;
        RECT 4.400 1843.800 2916.000 1845.200 ;
        RECT 4.000 1838.400 2916.000 1843.800 ;
        RECT 4.400 1837.000 2916.000 1838.400 ;
        RECT 4.000 1831.600 2916.000 1837.000 ;
        RECT 4.400 1830.200 2915.600 1831.600 ;
        RECT 4.000 1824.800 2916.000 1830.200 ;
        RECT 4.400 1823.400 2916.000 1824.800 ;
        RECT 4.000 1818.000 2916.000 1823.400 ;
        RECT 4.400 1816.600 2916.000 1818.000 ;
        RECT 4.000 1811.200 2916.000 1816.600 ;
        RECT 4.400 1809.800 2916.000 1811.200 ;
        RECT 4.000 1804.400 2916.000 1809.800 ;
        RECT 4.400 1803.000 2916.000 1804.400 ;
        RECT 4.000 1797.600 2916.000 1803.000 ;
        RECT 4.400 1796.200 2916.000 1797.600 ;
        RECT 4.000 1790.800 2916.000 1796.200 ;
        RECT 4.400 1789.400 2916.000 1790.800 ;
        RECT 4.000 1784.000 2916.000 1789.400 ;
        RECT 4.400 1782.600 2915.600 1784.000 ;
        RECT 4.000 1777.200 2916.000 1782.600 ;
        RECT 4.400 1775.800 2916.000 1777.200 ;
        RECT 4.000 1770.400 2916.000 1775.800 ;
        RECT 4.400 1769.000 2916.000 1770.400 ;
        RECT 4.000 1763.600 2916.000 1769.000 ;
        RECT 4.400 1762.200 2916.000 1763.600 ;
        RECT 4.000 1756.800 2916.000 1762.200 ;
        RECT 4.400 1755.400 2916.000 1756.800 ;
        RECT 4.000 1750.000 2916.000 1755.400 ;
        RECT 4.400 1748.600 2916.000 1750.000 ;
        RECT 4.000 1743.200 2916.000 1748.600 ;
        RECT 4.400 1741.800 2916.000 1743.200 ;
        RECT 4.000 1736.400 2916.000 1741.800 ;
        RECT 4.400 1735.000 2915.600 1736.400 ;
        RECT 4.000 1729.600 2916.000 1735.000 ;
        RECT 4.400 1728.200 2916.000 1729.600 ;
        RECT 4.000 1722.800 2916.000 1728.200 ;
        RECT 4.400 1721.400 2916.000 1722.800 ;
        RECT 4.000 1716.000 2916.000 1721.400 ;
        RECT 4.400 1714.600 2916.000 1716.000 ;
        RECT 4.000 1709.200 2916.000 1714.600 ;
        RECT 4.400 1707.800 2916.000 1709.200 ;
        RECT 4.000 1702.400 2916.000 1707.800 ;
        RECT 4.400 1701.000 2916.000 1702.400 ;
        RECT 4.000 1695.600 2916.000 1701.000 ;
        RECT 4.400 1694.200 2916.000 1695.600 ;
        RECT 4.000 1688.800 2916.000 1694.200 ;
        RECT 4.400 1687.400 2915.600 1688.800 ;
        RECT 4.000 1682.000 2916.000 1687.400 ;
        RECT 4.400 1680.600 2916.000 1682.000 ;
        RECT 4.000 1675.200 2916.000 1680.600 ;
        RECT 4.400 1673.800 2916.000 1675.200 ;
        RECT 4.000 1668.400 2916.000 1673.800 ;
        RECT 4.400 1667.000 2916.000 1668.400 ;
        RECT 4.000 1661.600 2916.000 1667.000 ;
        RECT 4.400 1660.200 2916.000 1661.600 ;
        RECT 4.000 1654.800 2916.000 1660.200 ;
        RECT 4.400 1653.400 2916.000 1654.800 ;
        RECT 4.000 1648.000 2916.000 1653.400 ;
        RECT 4.400 1646.600 2916.000 1648.000 ;
        RECT 4.000 1641.200 2916.000 1646.600 ;
        RECT 4.400 1639.800 2915.600 1641.200 ;
        RECT 4.000 1634.400 2916.000 1639.800 ;
        RECT 4.400 1633.000 2916.000 1634.400 ;
        RECT 4.000 1627.600 2916.000 1633.000 ;
        RECT 4.400 1626.200 2916.000 1627.600 ;
        RECT 4.000 1620.800 2916.000 1626.200 ;
        RECT 4.400 1619.400 2916.000 1620.800 ;
        RECT 4.000 1614.000 2916.000 1619.400 ;
        RECT 4.400 1612.600 2916.000 1614.000 ;
        RECT 4.000 1607.200 2916.000 1612.600 ;
        RECT 4.400 1605.800 2916.000 1607.200 ;
        RECT 4.000 1600.400 2916.000 1605.800 ;
        RECT 4.400 1599.000 2916.000 1600.400 ;
        RECT 4.000 1593.600 2916.000 1599.000 ;
        RECT 4.400 1592.200 2915.600 1593.600 ;
        RECT 4.000 1586.800 2916.000 1592.200 ;
        RECT 4.400 1585.400 2916.000 1586.800 ;
        RECT 4.000 1580.000 2916.000 1585.400 ;
        RECT 4.400 1578.600 2916.000 1580.000 ;
        RECT 4.000 1573.200 2916.000 1578.600 ;
        RECT 4.400 1571.800 2916.000 1573.200 ;
        RECT 4.000 1566.400 2916.000 1571.800 ;
        RECT 4.400 1565.000 2916.000 1566.400 ;
        RECT 4.000 1559.600 2916.000 1565.000 ;
        RECT 4.400 1558.200 2916.000 1559.600 ;
        RECT 4.000 1552.800 2916.000 1558.200 ;
        RECT 4.400 1551.400 2916.000 1552.800 ;
        RECT 4.000 1546.000 2916.000 1551.400 ;
        RECT 4.400 1544.600 2915.600 1546.000 ;
        RECT 4.000 1539.200 2916.000 1544.600 ;
        RECT 4.400 1537.800 2916.000 1539.200 ;
        RECT 4.000 1532.400 2916.000 1537.800 ;
        RECT 4.400 1531.000 2916.000 1532.400 ;
        RECT 4.000 1525.600 2916.000 1531.000 ;
        RECT 4.400 1524.200 2916.000 1525.600 ;
        RECT 4.000 1518.800 2916.000 1524.200 ;
        RECT 4.400 1517.400 2916.000 1518.800 ;
        RECT 4.000 1512.000 2916.000 1517.400 ;
        RECT 4.400 1510.600 2916.000 1512.000 ;
        RECT 4.000 1505.200 2916.000 1510.600 ;
        RECT 4.400 1503.800 2916.000 1505.200 ;
        RECT 4.000 1498.400 2916.000 1503.800 ;
        RECT 4.400 1497.000 2915.600 1498.400 ;
        RECT 4.000 1491.600 2916.000 1497.000 ;
        RECT 4.400 1490.200 2916.000 1491.600 ;
        RECT 4.000 1484.800 2916.000 1490.200 ;
        RECT 4.400 1483.400 2916.000 1484.800 ;
        RECT 4.000 1478.000 2916.000 1483.400 ;
        RECT 4.400 1476.600 2916.000 1478.000 ;
        RECT 4.000 1471.200 2916.000 1476.600 ;
        RECT 4.400 1469.800 2916.000 1471.200 ;
        RECT 4.000 1464.400 2916.000 1469.800 ;
        RECT 4.400 1463.000 2916.000 1464.400 ;
        RECT 4.000 1457.600 2916.000 1463.000 ;
        RECT 4.400 1456.200 2916.000 1457.600 ;
        RECT 4.000 1450.800 2916.000 1456.200 ;
        RECT 4.400 1449.400 2915.600 1450.800 ;
        RECT 4.000 1444.000 2916.000 1449.400 ;
        RECT 4.400 1442.600 2916.000 1444.000 ;
        RECT 4.000 1437.200 2916.000 1442.600 ;
        RECT 4.400 1435.800 2916.000 1437.200 ;
        RECT 4.000 1430.400 2916.000 1435.800 ;
        RECT 4.400 1429.000 2916.000 1430.400 ;
        RECT 4.000 1423.600 2916.000 1429.000 ;
        RECT 4.400 1422.200 2916.000 1423.600 ;
        RECT 4.000 1416.800 2916.000 1422.200 ;
        RECT 4.400 1415.400 2916.000 1416.800 ;
        RECT 4.000 1410.000 2916.000 1415.400 ;
        RECT 4.400 1408.600 2916.000 1410.000 ;
        RECT 4.000 1403.200 2916.000 1408.600 ;
        RECT 4.400 1401.800 2915.600 1403.200 ;
        RECT 4.000 1396.400 2916.000 1401.800 ;
        RECT 4.400 1395.000 2916.000 1396.400 ;
        RECT 4.000 1389.600 2916.000 1395.000 ;
        RECT 4.400 1388.200 2916.000 1389.600 ;
        RECT 4.000 1382.800 2916.000 1388.200 ;
        RECT 4.400 1381.400 2916.000 1382.800 ;
        RECT 4.000 1376.000 2916.000 1381.400 ;
        RECT 4.400 1374.600 2916.000 1376.000 ;
        RECT 4.000 1369.200 2916.000 1374.600 ;
        RECT 4.400 1367.800 2916.000 1369.200 ;
        RECT 4.000 1362.400 2916.000 1367.800 ;
        RECT 4.400 1361.000 2916.000 1362.400 ;
        RECT 4.000 1355.600 2916.000 1361.000 ;
        RECT 4.400 1354.200 2915.600 1355.600 ;
        RECT 4.000 1348.800 2916.000 1354.200 ;
        RECT 4.400 1347.400 2916.000 1348.800 ;
        RECT 4.000 1342.000 2916.000 1347.400 ;
        RECT 4.400 1340.600 2916.000 1342.000 ;
        RECT 4.000 1335.200 2916.000 1340.600 ;
        RECT 4.400 1333.800 2916.000 1335.200 ;
        RECT 4.000 1328.400 2916.000 1333.800 ;
        RECT 4.400 1327.000 2916.000 1328.400 ;
        RECT 4.000 1321.600 2916.000 1327.000 ;
        RECT 4.400 1320.200 2916.000 1321.600 ;
        RECT 4.000 1314.800 2916.000 1320.200 ;
        RECT 4.400 1313.400 2916.000 1314.800 ;
        RECT 4.000 1308.000 2916.000 1313.400 ;
        RECT 4.400 1306.600 2915.600 1308.000 ;
        RECT 4.000 1301.200 2916.000 1306.600 ;
        RECT 4.400 1299.800 2916.000 1301.200 ;
        RECT 4.000 1294.400 2916.000 1299.800 ;
        RECT 4.400 1293.000 2916.000 1294.400 ;
        RECT 4.000 1287.600 2916.000 1293.000 ;
        RECT 4.400 1286.200 2916.000 1287.600 ;
        RECT 4.000 1280.800 2916.000 1286.200 ;
        RECT 4.400 1279.400 2916.000 1280.800 ;
        RECT 4.000 1274.000 2916.000 1279.400 ;
        RECT 4.400 1272.600 2916.000 1274.000 ;
        RECT 4.000 1267.200 2916.000 1272.600 ;
        RECT 4.400 1265.800 2916.000 1267.200 ;
        RECT 4.000 1260.400 2916.000 1265.800 ;
        RECT 4.400 1259.000 2915.600 1260.400 ;
        RECT 4.000 1253.600 2916.000 1259.000 ;
        RECT 4.400 1252.200 2916.000 1253.600 ;
        RECT 4.000 1246.800 2916.000 1252.200 ;
        RECT 4.400 1245.400 2916.000 1246.800 ;
        RECT 4.000 1240.000 2916.000 1245.400 ;
        RECT 4.400 1238.600 2916.000 1240.000 ;
        RECT 4.000 1233.200 2916.000 1238.600 ;
        RECT 4.400 1231.800 2916.000 1233.200 ;
        RECT 4.000 1226.400 2916.000 1231.800 ;
        RECT 4.400 1225.000 2916.000 1226.400 ;
        RECT 4.000 1219.600 2916.000 1225.000 ;
        RECT 4.400 1218.200 2916.000 1219.600 ;
        RECT 4.000 1212.800 2916.000 1218.200 ;
        RECT 4.400 1211.400 2915.600 1212.800 ;
        RECT 4.000 1206.000 2916.000 1211.400 ;
        RECT 4.400 1204.600 2916.000 1206.000 ;
        RECT 4.000 1199.200 2916.000 1204.600 ;
        RECT 4.400 1197.800 2916.000 1199.200 ;
        RECT 4.000 1192.400 2916.000 1197.800 ;
        RECT 4.400 1191.000 2916.000 1192.400 ;
        RECT 4.000 1185.600 2916.000 1191.000 ;
        RECT 4.400 1184.200 2916.000 1185.600 ;
        RECT 4.000 1178.800 2916.000 1184.200 ;
        RECT 4.400 1177.400 2916.000 1178.800 ;
        RECT 4.000 1172.000 2916.000 1177.400 ;
        RECT 4.400 1170.600 2916.000 1172.000 ;
        RECT 4.000 1165.200 2916.000 1170.600 ;
        RECT 4.400 1163.800 2915.600 1165.200 ;
        RECT 4.000 1158.400 2916.000 1163.800 ;
        RECT 4.400 1157.000 2916.000 1158.400 ;
        RECT 4.000 1151.600 2916.000 1157.000 ;
        RECT 4.400 1150.200 2916.000 1151.600 ;
        RECT 4.000 1144.800 2916.000 1150.200 ;
        RECT 4.400 1143.400 2916.000 1144.800 ;
        RECT 4.000 1138.000 2916.000 1143.400 ;
        RECT 4.400 1136.600 2916.000 1138.000 ;
        RECT 4.000 1131.200 2916.000 1136.600 ;
        RECT 4.400 1129.800 2916.000 1131.200 ;
        RECT 4.000 1124.400 2916.000 1129.800 ;
        RECT 4.400 1123.000 2916.000 1124.400 ;
        RECT 4.000 1117.600 2916.000 1123.000 ;
        RECT 4.400 1116.200 2915.600 1117.600 ;
        RECT 4.000 1110.800 2916.000 1116.200 ;
        RECT 4.400 1109.400 2916.000 1110.800 ;
        RECT 4.000 1104.000 2916.000 1109.400 ;
        RECT 4.400 1102.600 2916.000 1104.000 ;
        RECT 4.000 1097.200 2916.000 1102.600 ;
        RECT 4.400 1095.800 2916.000 1097.200 ;
        RECT 4.000 1090.400 2916.000 1095.800 ;
        RECT 4.400 1089.000 2916.000 1090.400 ;
        RECT 4.000 1083.600 2916.000 1089.000 ;
        RECT 4.400 1082.200 2916.000 1083.600 ;
        RECT 4.000 1076.800 2916.000 1082.200 ;
        RECT 4.400 1075.400 2916.000 1076.800 ;
        RECT 4.000 1070.000 2916.000 1075.400 ;
        RECT 4.400 1068.600 2915.600 1070.000 ;
        RECT 4.000 1063.200 2916.000 1068.600 ;
        RECT 4.400 1061.800 2916.000 1063.200 ;
        RECT 4.000 1056.400 2916.000 1061.800 ;
        RECT 4.400 1055.000 2916.000 1056.400 ;
        RECT 4.000 1049.600 2916.000 1055.000 ;
        RECT 4.400 1048.200 2916.000 1049.600 ;
        RECT 4.000 1042.800 2916.000 1048.200 ;
        RECT 4.400 1041.400 2916.000 1042.800 ;
        RECT 4.000 1036.000 2916.000 1041.400 ;
        RECT 4.400 1034.600 2916.000 1036.000 ;
        RECT 4.000 1029.200 2916.000 1034.600 ;
        RECT 4.400 1027.800 2916.000 1029.200 ;
        RECT 4.000 1022.400 2916.000 1027.800 ;
        RECT 4.400 1021.000 2915.600 1022.400 ;
        RECT 4.000 1015.600 2916.000 1021.000 ;
        RECT 4.400 1014.200 2916.000 1015.600 ;
        RECT 4.000 1008.800 2916.000 1014.200 ;
        RECT 4.400 1007.400 2916.000 1008.800 ;
        RECT 4.000 1002.000 2916.000 1007.400 ;
        RECT 4.400 1000.600 2916.000 1002.000 ;
        RECT 4.000 995.200 2916.000 1000.600 ;
        RECT 4.400 993.800 2916.000 995.200 ;
        RECT 4.000 988.400 2916.000 993.800 ;
        RECT 4.400 987.000 2916.000 988.400 ;
        RECT 4.000 981.600 2916.000 987.000 ;
        RECT 4.400 980.200 2916.000 981.600 ;
        RECT 4.000 974.800 2916.000 980.200 ;
        RECT 4.400 973.400 2915.600 974.800 ;
        RECT 4.000 968.000 2916.000 973.400 ;
        RECT 4.400 966.600 2916.000 968.000 ;
        RECT 4.000 961.200 2916.000 966.600 ;
        RECT 4.400 959.800 2916.000 961.200 ;
        RECT 4.000 954.400 2916.000 959.800 ;
        RECT 4.400 953.000 2916.000 954.400 ;
        RECT 4.000 947.600 2916.000 953.000 ;
        RECT 4.400 946.200 2916.000 947.600 ;
        RECT 4.000 940.800 2916.000 946.200 ;
        RECT 4.400 939.400 2916.000 940.800 ;
        RECT 4.000 934.000 2916.000 939.400 ;
        RECT 4.400 932.600 2916.000 934.000 ;
        RECT 4.000 927.200 2916.000 932.600 ;
        RECT 4.400 925.800 2915.600 927.200 ;
        RECT 4.000 920.400 2916.000 925.800 ;
        RECT 4.400 919.000 2916.000 920.400 ;
        RECT 4.000 913.600 2916.000 919.000 ;
        RECT 4.400 912.200 2916.000 913.600 ;
        RECT 4.000 906.800 2916.000 912.200 ;
        RECT 4.400 905.400 2916.000 906.800 ;
        RECT 4.000 900.000 2916.000 905.400 ;
        RECT 4.400 898.600 2916.000 900.000 ;
        RECT 4.000 893.200 2916.000 898.600 ;
        RECT 4.400 891.800 2916.000 893.200 ;
        RECT 4.000 886.400 2916.000 891.800 ;
        RECT 4.400 885.000 2916.000 886.400 ;
        RECT 4.000 879.600 2916.000 885.000 ;
        RECT 4.400 878.200 2915.600 879.600 ;
        RECT 4.000 872.800 2916.000 878.200 ;
        RECT 4.400 871.400 2916.000 872.800 ;
        RECT 4.000 866.000 2916.000 871.400 ;
        RECT 4.400 864.600 2916.000 866.000 ;
        RECT 4.000 859.200 2916.000 864.600 ;
        RECT 4.400 857.800 2916.000 859.200 ;
        RECT 4.000 852.400 2916.000 857.800 ;
        RECT 4.400 851.000 2916.000 852.400 ;
        RECT 4.000 845.600 2916.000 851.000 ;
        RECT 4.400 844.200 2916.000 845.600 ;
        RECT 4.000 838.800 2916.000 844.200 ;
        RECT 4.400 837.400 2916.000 838.800 ;
        RECT 4.000 832.000 2916.000 837.400 ;
        RECT 4.400 830.600 2915.600 832.000 ;
        RECT 4.000 825.200 2916.000 830.600 ;
        RECT 4.400 823.800 2916.000 825.200 ;
        RECT 4.000 818.400 2916.000 823.800 ;
        RECT 4.400 817.000 2916.000 818.400 ;
        RECT 4.000 811.600 2916.000 817.000 ;
        RECT 4.400 810.200 2916.000 811.600 ;
        RECT 4.000 804.800 2916.000 810.200 ;
        RECT 4.400 803.400 2916.000 804.800 ;
        RECT 4.000 798.000 2916.000 803.400 ;
        RECT 4.400 796.600 2916.000 798.000 ;
        RECT 4.000 791.200 2916.000 796.600 ;
        RECT 4.400 789.800 2916.000 791.200 ;
        RECT 4.000 784.400 2916.000 789.800 ;
        RECT 4.400 783.000 2915.600 784.400 ;
        RECT 4.000 777.600 2916.000 783.000 ;
        RECT 4.400 776.200 2916.000 777.600 ;
        RECT 4.000 770.800 2916.000 776.200 ;
        RECT 4.400 769.400 2916.000 770.800 ;
        RECT 4.000 764.000 2916.000 769.400 ;
        RECT 4.400 762.600 2916.000 764.000 ;
        RECT 4.000 757.200 2916.000 762.600 ;
        RECT 4.400 755.800 2916.000 757.200 ;
        RECT 4.000 750.400 2916.000 755.800 ;
        RECT 4.400 749.000 2916.000 750.400 ;
        RECT 4.000 743.600 2916.000 749.000 ;
        RECT 4.400 742.200 2916.000 743.600 ;
        RECT 4.000 736.800 2916.000 742.200 ;
        RECT 4.400 735.400 2915.600 736.800 ;
        RECT 4.000 730.000 2916.000 735.400 ;
        RECT 4.400 728.600 2916.000 730.000 ;
        RECT 4.000 723.200 2916.000 728.600 ;
        RECT 4.400 721.800 2916.000 723.200 ;
        RECT 4.000 716.400 2916.000 721.800 ;
        RECT 4.400 715.000 2916.000 716.400 ;
        RECT 4.000 709.600 2916.000 715.000 ;
        RECT 4.400 708.200 2916.000 709.600 ;
        RECT 4.000 702.800 2916.000 708.200 ;
        RECT 4.400 701.400 2916.000 702.800 ;
        RECT 4.000 696.000 2916.000 701.400 ;
        RECT 4.400 694.600 2916.000 696.000 ;
        RECT 4.000 689.200 2916.000 694.600 ;
        RECT 4.400 687.800 2915.600 689.200 ;
        RECT 4.000 682.400 2916.000 687.800 ;
        RECT 4.400 681.000 2916.000 682.400 ;
        RECT 4.000 675.600 2916.000 681.000 ;
        RECT 4.400 674.200 2916.000 675.600 ;
        RECT 4.000 668.800 2916.000 674.200 ;
        RECT 4.400 667.400 2916.000 668.800 ;
        RECT 4.000 662.000 2916.000 667.400 ;
        RECT 4.400 660.600 2916.000 662.000 ;
        RECT 4.000 655.200 2916.000 660.600 ;
        RECT 4.400 653.800 2916.000 655.200 ;
        RECT 4.000 648.400 2916.000 653.800 ;
        RECT 4.400 647.000 2916.000 648.400 ;
        RECT 4.000 641.600 2916.000 647.000 ;
        RECT 4.400 640.200 2915.600 641.600 ;
        RECT 4.000 634.800 2916.000 640.200 ;
        RECT 4.400 633.400 2916.000 634.800 ;
        RECT 4.000 628.000 2916.000 633.400 ;
        RECT 4.400 626.600 2916.000 628.000 ;
        RECT 4.000 621.200 2916.000 626.600 ;
        RECT 4.400 619.800 2916.000 621.200 ;
        RECT 4.000 614.400 2916.000 619.800 ;
        RECT 4.400 613.000 2916.000 614.400 ;
        RECT 4.000 607.600 2916.000 613.000 ;
        RECT 4.400 606.200 2916.000 607.600 ;
        RECT 4.000 600.800 2916.000 606.200 ;
        RECT 4.400 599.400 2916.000 600.800 ;
        RECT 4.000 594.000 2916.000 599.400 ;
        RECT 4.400 592.600 2915.600 594.000 ;
        RECT 4.000 587.200 2916.000 592.600 ;
        RECT 4.400 585.800 2916.000 587.200 ;
        RECT 4.000 580.400 2916.000 585.800 ;
        RECT 4.400 579.000 2916.000 580.400 ;
        RECT 4.000 573.600 2916.000 579.000 ;
        RECT 4.400 572.200 2916.000 573.600 ;
        RECT 4.000 566.800 2916.000 572.200 ;
        RECT 4.400 565.400 2916.000 566.800 ;
        RECT 4.000 560.000 2916.000 565.400 ;
        RECT 4.400 558.600 2916.000 560.000 ;
        RECT 4.000 553.200 2916.000 558.600 ;
        RECT 4.400 551.800 2916.000 553.200 ;
        RECT 4.000 546.400 2916.000 551.800 ;
        RECT 4.400 545.000 2915.600 546.400 ;
        RECT 4.000 539.600 2916.000 545.000 ;
        RECT 4.400 538.200 2916.000 539.600 ;
        RECT 4.000 532.800 2916.000 538.200 ;
        RECT 4.400 531.400 2916.000 532.800 ;
        RECT 4.000 526.000 2916.000 531.400 ;
        RECT 4.400 524.600 2916.000 526.000 ;
        RECT 4.000 519.200 2916.000 524.600 ;
        RECT 4.400 517.800 2916.000 519.200 ;
        RECT 4.000 512.400 2916.000 517.800 ;
        RECT 4.400 511.000 2916.000 512.400 ;
        RECT 4.000 505.600 2916.000 511.000 ;
        RECT 4.400 504.200 2916.000 505.600 ;
        RECT 4.000 498.800 2916.000 504.200 ;
        RECT 4.400 497.400 2915.600 498.800 ;
        RECT 4.000 492.000 2916.000 497.400 ;
        RECT 4.400 490.600 2916.000 492.000 ;
        RECT 4.000 485.200 2916.000 490.600 ;
        RECT 4.400 483.800 2916.000 485.200 ;
        RECT 4.000 478.400 2916.000 483.800 ;
        RECT 4.400 477.000 2916.000 478.400 ;
        RECT 4.000 471.600 2916.000 477.000 ;
        RECT 4.400 470.200 2916.000 471.600 ;
        RECT 4.000 464.800 2916.000 470.200 ;
        RECT 4.400 463.400 2916.000 464.800 ;
        RECT 4.000 458.000 2916.000 463.400 ;
        RECT 4.400 456.600 2916.000 458.000 ;
        RECT 4.000 451.200 2916.000 456.600 ;
        RECT 4.400 449.800 2915.600 451.200 ;
        RECT 4.000 444.400 2916.000 449.800 ;
        RECT 4.400 443.000 2916.000 444.400 ;
        RECT 4.000 437.600 2916.000 443.000 ;
        RECT 4.400 436.200 2916.000 437.600 ;
        RECT 4.000 430.800 2916.000 436.200 ;
        RECT 4.400 429.400 2916.000 430.800 ;
        RECT 4.000 424.000 2916.000 429.400 ;
        RECT 4.400 422.600 2916.000 424.000 ;
        RECT 4.000 417.200 2916.000 422.600 ;
        RECT 4.400 415.800 2916.000 417.200 ;
        RECT 4.000 410.400 2916.000 415.800 ;
        RECT 4.400 409.000 2916.000 410.400 ;
        RECT 4.000 403.600 2916.000 409.000 ;
        RECT 4.400 402.200 2915.600 403.600 ;
        RECT 4.000 396.800 2916.000 402.200 ;
        RECT 4.400 395.400 2916.000 396.800 ;
        RECT 4.000 390.000 2916.000 395.400 ;
        RECT 4.400 388.600 2916.000 390.000 ;
        RECT 4.000 383.200 2916.000 388.600 ;
        RECT 4.400 381.800 2916.000 383.200 ;
        RECT 4.000 376.400 2916.000 381.800 ;
        RECT 4.400 375.000 2916.000 376.400 ;
        RECT 4.000 369.600 2916.000 375.000 ;
        RECT 4.400 368.200 2916.000 369.600 ;
        RECT 4.000 362.800 2916.000 368.200 ;
        RECT 4.400 361.400 2916.000 362.800 ;
        RECT 4.000 356.000 2916.000 361.400 ;
        RECT 4.400 354.600 2915.600 356.000 ;
        RECT 4.000 349.200 2916.000 354.600 ;
        RECT 4.400 347.800 2916.000 349.200 ;
        RECT 4.000 342.400 2916.000 347.800 ;
        RECT 4.400 341.000 2916.000 342.400 ;
        RECT 4.000 335.600 2916.000 341.000 ;
        RECT 4.400 334.200 2916.000 335.600 ;
        RECT 4.000 328.800 2916.000 334.200 ;
        RECT 4.400 327.400 2916.000 328.800 ;
        RECT 4.000 322.000 2916.000 327.400 ;
        RECT 4.400 320.600 2916.000 322.000 ;
        RECT 4.000 315.200 2916.000 320.600 ;
        RECT 4.400 313.800 2916.000 315.200 ;
        RECT 4.000 308.400 2916.000 313.800 ;
        RECT 4.400 307.000 2915.600 308.400 ;
        RECT 4.000 301.600 2916.000 307.000 ;
        RECT 4.400 300.200 2916.000 301.600 ;
        RECT 4.000 294.800 2916.000 300.200 ;
        RECT 4.400 293.400 2916.000 294.800 ;
        RECT 4.000 288.000 2916.000 293.400 ;
        RECT 4.400 286.600 2916.000 288.000 ;
        RECT 4.000 281.200 2916.000 286.600 ;
        RECT 4.400 279.800 2916.000 281.200 ;
        RECT 4.000 274.400 2916.000 279.800 ;
        RECT 4.400 273.000 2916.000 274.400 ;
        RECT 4.000 267.600 2916.000 273.000 ;
        RECT 4.400 266.200 2916.000 267.600 ;
        RECT 4.000 260.800 2916.000 266.200 ;
        RECT 4.400 259.400 2915.600 260.800 ;
        RECT 4.000 254.000 2916.000 259.400 ;
        RECT 4.400 252.600 2916.000 254.000 ;
        RECT 4.000 247.200 2916.000 252.600 ;
        RECT 4.400 245.800 2916.000 247.200 ;
        RECT 4.000 240.400 2916.000 245.800 ;
        RECT 4.400 239.000 2916.000 240.400 ;
        RECT 4.000 233.600 2916.000 239.000 ;
        RECT 4.400 232.200 2916.000 233.600 ;
        RECT 4.000 226.800 2916.000 232.200 ;
        RECT 4.400 225.400 2916.000 226.800 ;
        RECT 4.000 220.000 2916.000 225.400 ;
        RECT 4.400 218.600 2916.000 220.000 ;
        RECT 4.000 213.200 2916.000 218.600 ;
        RECT 4.400 211.800 2915.600 213.200 ;
        RECT 4.000 206.400 2916.000 211.800 ;
        RECT 4.400 205.000 2916.000 206.400 ;
        RECT 4.000 199.600 2916.000 205.000 ;
        RECT 4.400 198.200 2916.000 199.600 ;
        RECT 4.000 192.800 2916.000 198.200 ;
        RECT 4.400 191.400 2916.000 192.800 ;
        RECT 4.000 186.000 2916.000 191.400 ;
        RECT 4.400 184.600 2916.000 186.000 ;
        RECT 4.000 179.200 2916.000 184.600 ;
        RECT 4.400 177.800 2916.000 179.200 ;
        RECT 4.000 172.400 2916.000 177.800 ;
        RECT 4.400 171.000 2916.000 172.400 ;
        RECT 4.000 165.600 2916.000 171.000 ;
        RECT 4.400 164.200 2915.600 165.600 ;
        RECT 4.000 158.800 2916.000 164.200 ;
        RECT 4.400 157.400 2916.000 158.800 ;
        RECT 4.000 152.000 2916.000 157.400 ;
        RECT 4.400 150.600 2916.000 152.000 ;
        RECT 4.000 145.200 2916.000 150.600 ;
        RECT 4.400 143.800 2916.000 145.200 ;
        RECT 4.000 138.400 2916.000 143.800 ;
        RECT 4.400 137.000 2916.000 138.400 ;
        RECT 4.000 131.600 2916.000 137.000 ;
        RECT 4.400 130.200 2916.000 131.600 ;
        RECT 4.000 124.800 2916.000 130.200 ;
        RECT 4.400 123.400 2916.000 124.800 ;
        RECT 4.000 118.000 2916.000 123.400 ;
        RECT 4.400 116.600 2915.600 118.000 ;
        RECT 4.000 111.200 2916.000 116.600 ;
        RECT 4.400 109.800 2916.000 111.200 ;
        RECT 4.000 104.400 2916.000 109.800 ;
        RECT 4.400 103.000 2916.000 104.400 ;
        RECT 4.000 97.600 2916.000 103.000 ;
        RECT 4.400 96.200 2916.000 97.600 ;
        RECT 4.000 90.800 2916.000 96.200 ;
        RECT 4.400 89.400 2916.000 90.800 ;
        RECT 4.000 84.000 2916.000 89.400 ;
        RECT 4.400 83.140 2916.000 84.000 ;
      LAYER met4 ;
        RECT 1085.895 83.135 1088.570 3507.945 ;
        RECT 1092.470 83.135 1093.370 3507.945 ;
        RECT 1097.270 83.135 1098.170 3507.945 ;
        RECT 1102.070 83.135 1102.970 3507.945 ;
        RECT 1106.870 83.135 1107.770 3507.945 ;
        RECT 1111.670 83.135 1112.570 3507.945 ;
        RECT 1116.470 1998.700 1117.370 3507.945 ;
        RECT 1121.270 1998.700 1122.170 3507.945 ;
        RECT 1126.070 1998.700 1268.570 3507.945 ;
        RECT 1116.470 1806.905 1268.570 1998.700 ;
        RECT 1272.470 1998.700 1273.370 3507.945 ;
        RECT 1277.270 1998.700 1278.170 3507.945 ;
        RECT 1282.070 1998.700 1282.970 3507.945 ;
        RECT 1272.470 1806.905 1282.970 1998.700 ;
        RECT 1286.870 1806.905 1287.770 3507.945 ;
        RECT 1291.670 1806.905 1292.570 3507.945 ;
        RECT 1296.470 1806.905 1297.370 3507.945 ;
        RECT 1301.270 1806.905 1302.170 3507.945 ;
        RECT 1306.070 1806.905 1448.570 3507.945 ;
        RECT 1452.470 1806.905 1453.370 3507.945 ;
        RECT 1457.270 1806.905 1458.170 3507.945 ;
        RECT 1462.070 1806.905 1462.970 3507.945 ;
        RECT 1466.870 1806.905 1467.770 3507.945 ;
        RECT 1471.670 1806.905 1472.570 3507.945 ;
        RECT 1476.470 1806.905 1477.370 3507.945 ;
        RECT 1481.270 1806.905 1482.170 3507.945 ;
        RECT 1486.070 1806.905 1628.570 3507.945 ;
        RECT 1116.470 1302.415 1628.570 1806.905 ;
        RECT 1116.470 1300.340 1268.570 1302.415 ;
        RECT 1116.470 83.135 1117.370 1300.340 ;
        RECT 1121.270 83.135 1122.170 1300.340 ;
        RECT 1126.070 83.135 1268.570 1300.340 ;
        RECT 1272.470 1300.340 1282.970 1302.415 ;
        RECT 1272.470 83.135 1273.370 1300.340 ;
        RECT 1277.270 83.135 1278.170 1300.340 ;
        RECT 1282.070 83.135 1282.970 1300.340 ;
        RECT 1286.870 83.135 1287.770 1302.415 ;
        RECT 1291.670 83.135 1292.570 1302.415 ;
        RECT 1296.470 83.135 1297.370 1302.415 ;
        RECT 1301.270 83.135 1302.170 1302.415 ;
        RECT 1306.070 83.135 1448.570 1302.415 ;
        RECT 1452.470 83.135 1453.370 1302.415 ;
        RECT 1457.270 83.135 1458.170 1302.415 ;
        RECT 1462.070 83.135 1462.970 1302.415 ;
        RECT 1466.870 83.135 1467.770 1302.415 ;
        RECT 1471.670 83.135 1472.570 1302.415 ;
        RECT 1476.470 83.135 1477.370 1302.415 ;
        RECT 1481.270 83.135 1482.170 1302.415 ;
        RECT 1486.070 83.135 1628.570 1302.415 ;
        RECT 1632.470 83.135 1633.370 3507.945 ;
        RECT 1637.270 83.135 1638.170 3507.945 ;
        RECT 1642.070 83.135 1642.970 3507.945 ;
        RECT 1646.870 83.135 1647.770 3507.945 ;
        RECT 1651.670 83.135 1652.570 3507.945 ;
        RECT 1656.470 83.135 1657.370 3507.945 ;
        RECT 1661.270 83.135 1662.170 3507.945 ;
        RECT 1666.070 83.135 1794.130 3507.945 ;
      LAYER met5 ;
        RECT 1087.100 1852.630 1794.380 1944.350 ;
        RECT 1087.100 1672.630 1794.380 1812.730 ;
        RECT 1093.680 1632.730 1794.380 1642.330 ;
        RECT 1087.100 1492.630 1794.380 1632.730 ;
        RECT 1093.680 1478.230 1794.380 1492.630 ;
        RECT 1087.100 1326.730 1794.380 1452.730 ;
  END
END user_project_wrapper
END LIBRARY

